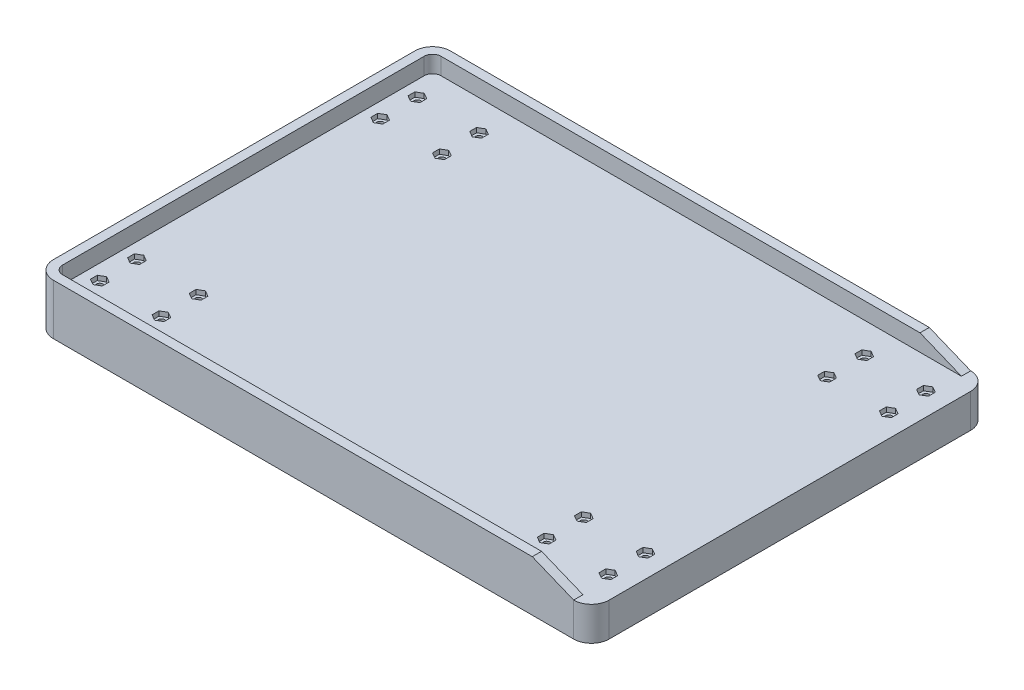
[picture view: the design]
ISO-10303-21;
HEADER;
FILE_DESCRIPTION(('STEP AP214'),'2;1');
FILE_NAME('part.step','',(''),(''),'','','');
FILE_SCHEMA(('AUTOMOTIVE_DESIGN { 1 0 10303 214 1 1 1 1 }'));
ENDSEC;
DATA;
#1=APPLICATION_CONTEXT('core data for automotive mechanical design processes');
#2=APPLICATION_PROTOCOL_DEFINITION('international standard','automotive_design',2000,#1);
#3=PRODUCT_CONTEXT('',#1,'mechanical');
#4=PRODUCT('Part','Part','',(#3));
#5=PRODUCT_RELATED_PRODUCT_CATEGORY('part','',(#4));
#6=PRODUCT_DEFINITION_FORMATION('','',#4);
#7=PRODUCT_DEFINITION_CONTEXT('part definition',#1,'design');
#8=PRODUCT_DEFINITION('design','',#6,#7);
#9=PRODUCT_DEFINITION_SHAPE('','',#8);
#10=(LENGTH_UNIT() NAMED_UNIT(*) SI_UNIT(.MILLI.,.METRE.));
#11=(NAMED_UNIT(*) PLANE_ANGLE_UNIT() SI_UNIT($,.RADIAN.));
#12=(NAMED_UNIT(*) SI_UNIT($,.STERADIAN.) SOLID_ANGLE_UNIT());
#13=UNCERTAINTY_MEASURE_WITH_UNIT(LENGTH_MEASURE(1.E-05),#10,'distance_accuracy_value','');
#14=(GEOMETRIC_REPRESENTATION_CONTEXT(3) GLOBAL_UNCERTAINTY_ASSIGNED_CONTEXT((#13)) GLOBAL_UNIT_ASSIGNED_CONTEXT((#10,
#11,#12)) REPRESENTATION_CONTEXT('',''));
#15=CARTESIAN_POINT('',(0.,0.,0.));
#16=DIRECTION('',(0.,0.,1.));
#17=DIRECTION('',(1.,0.,0.));
#18=AXIS2_PLACEMENT_3D('',#15,#16,#17);
#19=CARTESIAN_POINT('',(329.,60.,-214.));
#20=DIRECTION('',(-1.,0.,0.));
#21=DIRECTION('',(0.,0.,1.));
#22=AXIS2_PLACEMENT_3D('',#19,#20,#21);
#23=PLANE('',#22);
#24=DIRECTION('',(0.,0.,-1.));
#25=VECTOR('',#24,1.);
#26=CARTESIAN_POINT('',(329.,40.,-214.));
#27=LINE('',#26,#25);
#28=CARTESIAN_POINT('',(329.,40.,214.));
#29=VERTEX_POINT('',#28);
#30=CARTESIAN_POINT('',(329.,40.,-214.));
#31=VERTEX_POINT('',#30);
#32=EDGE_CURVE('E1550',#29,#31,#27,.T.);
#33=ORIENTED_EDGE('',*,*,#32,.F.);
#34=DIRECTION('',(0.,-1.,0.));
#35=VECTOR('',#34,1.);
#36=CARTESIAN_POINT('',(329.,60.,214.));
#37=LINE('',#36,#35);
#38=CARTESIAN_POINT('',(329.,0.,214.));
#39=VERTEX_POINT('',#38);
#40=EDGE_CURVE('E1606',#29,#39,#37,.T.);
#41=ORIENTED_EDGE('',*,*,#40,.T.);
#42=DIRECTION('',(0.,0.,-1.));
#43=VECTOR('',#42,1.);
#44=CARTESIAN_POINT('',(329.,0.,-214.));
#45=LINE('',#44,#43);
#46=CARTESIAN_POINT('',(329.,0.,-214.));
#47=VERTEX_POINT('',#46);
#48=EDGE_CURVE('E1583',#39,#47,#45,.T.);
#49=ORIENTED_EDGE('',*,*,#48,.T.);
#50=DIRECTION('',(0.,-1.,0.));
#51=VECTOR('',#50,1.);
#52=CARTESIAN_POINT('',(329.,60.,-214.));
#53=LINE('',#52,#51);
#54=EDGE_CURVE('E1604',#31,#47,#53,.T.);
#55=ORIENTED_EDGE('',*,*,#54,.F.);
#56=EDGE_LOOP('',(#33,#41,#49,#55));
#57=FACE_BOUND('',#56,.T.);
#58=ADVANCED_FACE('F44',(#57),#23,.F.);
#59=CARTESIAN_POINT('',(-308.,60.,214.));
#60=DIRECTION('',(0.,-1.,0.));
#61=DIRECTION('',(0.,0.,-1.));
#62=AXIS2_PLACEMENT_3D('',#59,#60,#61);
#63=CYLINDRICAL_SURFACE('',#62,21.0000000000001);
#64=CARTESIAN_POINT('',(-308.,0.,214.));
#65=DIRECTION('',(0.,1.,0.));
#66=DIRECTION('',(0.,0.,1.));
#67=AXIS2_PLACEMENT_3D('',#64,#65,#66);
#68=CIRCLE('',#67,21.0000000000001);
#69=CARTESIAN_POINT('',(-329.,0.,214.));
#70=VERTEX_POINT('',#69);
#71=CARTESIAN_POINT('',(-308.,0.,235.));
#72=VERTEX_POINT('',#71);
#73=EDGE_CURVE('E1560',#70,#72,#68,.T.);
#74=ORIENTED_EDGE('',*,*,#73,.T.);
#75=DIRECTION('',(0.,-1.,0.));
#76=VECTOR('',#75,1.);
#77=CARTESIAN_POINT('',(-308.,60.,235.));
#78=LINE('',#77,#76);
#79=CARTESIAN_POINT('',(-308.,60.,235.));
#80=VERTEX_POINT('',#79);
#81=EDGE_CURVE('E1610',#80,#72,#78,.T.);
#82=ORIENTED_EDGE('',*,*,#81,.F.);
#83=CARTESIAN_POINT('',(-308.,60.,214.));
#84=DIRECTION('',(0.,1.,0.));
#85=DIRECTION('',(0.,0.,1.));
#86=AXIS2_PLACEMENT_3D('',#83,#84,#85);
#87=CIRCLE('',#86,21.0000000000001);
#88=CARTESIAN_POINT('',(-329.,60.,214.));
#89=VERTEX_POINT('',#88);
#90=EDGE_CURVE('E1561',#89,#80,#87,.T.);
#91=ORIENTED_EDGE('',*,*,#90,.F.);
#92=DIRECTION('',(0.,-1.,0.));
#93=VECTOR('',#92,1.);
#94=CARTESIAN_POINT('',(-329.,60.,214.));
#95=LINE('',#94,#93);
#96=EDGE_CURVE('E1574',#89,#70,#95,.T.);
#97=ORIENTED_EDGE('',*,*,#96,.T.);
#98=EDGE_LOOP('',(#74,#82,#91,#97));
#99=FACE_BOUND('',#98,.T.);
#100=ADVANCED_FACE('F46',(#99),#63,.T.);
#101=CARTESIAN_POINT('',(-308.,60.,235.));
#102=DIRECTION('',(0.,0.,-1.));
#103=DIRECTION('',(-1.,0.,0.));
#104=AXIS2_PLACEMENT_3D('',#101,#102,#103);
#105=PLANE('',#104);
#106=DIRECTION('',(0.,-1.,0.));
#107=VECTOR('',#106,1.);
#108=CARTESIAN_POINT('',(308.,60.,235.));
#109=LINE('',#108,#107);
#110=CARTESIAN_POINT('',(308.,40.,235.));
#111=VERTEX_POINT('',#110);
#112=CARTESIAN_POINT('',(308.,0.,235.));
#113=VERTEX_POINT('',#112);
#114=EDGE_CURVE('E1608',#111,#113,#109,.T.);
#115=ORIENTED_EDGE('',*,*,#114,.F.);
#116=DIRECTION('',(-0.925847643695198,0.377896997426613,0.));
#117=VECTOR('',#116,1.);
#118=CARTESIAN_POINT('',(-227.028918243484,258.379150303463,235.));
#119=LINE('',#118,#117);
#120=CARTESIAN_POINT('',(259.,60.,235.));
#121=VERTEX_POINT('',#120);
#122=EDGE_CURVE('E1518',#111,#121,#119,.T.);
#123=ORIENTED_EDGE('',*,*,#122,.T.);
#124=DIRECTION('',(1.,0.,0.));
#125=VECTOR('',#124,1.);
#126=CARTESIAN_POINT('',(-308.,60.,235.));
#127=LINE('',#126,#125);
#128=EDGE_CURVE('E1564',#80,#121,#127,.T.);
#129=ORIENTED_EDGE('',*,*,#128,.F.);
#130=ORIENTED_EDGE('',*,*,#81,.T.);
#131=DIRECTION('',(1.,0.,0.));
#132=VECTOR('',#131,1.);
#133=CARTESIAN_POINT('',(-308.,0.,235.));
#134=LINE('',#133,#132);
#135=EDGE_CURVE('E1577',#72,#113,#134,.T.);
#136=ORIENTED_EDGE('',*,*,#135,.T.);
#137=EDGE_LOOP('',(#115,#123,#129,#130,#136));
#138=FACE_BOUND('',#137,.T.);
#139=ADVANCED_FACE('F1732',(#138),#105,.F.);
#140=CARTESIAN_POINT('',(308.,60.,214.));
#141=DIRECTION('',(0.,-1.,0.));
#142=DIRECTION('',(0.,0.,-1.));
#143=AXIS2_PLACEMENT_3D('',#140,#141,#142);
#144=CYLINDRICAL_SURFACE('',#143,21.);
#145=CARTESIAN_POINT('',(308.,40.,214.));
#146=DIRECTION('',(0.,1.,0.));
#147=DIRECTION('',(0.,0.,1.));
#148=AXIS2_PLACEMENT_3D('',#145,#146,#147);
#149=CIRCLE('',#148,21.);
#150=EDGE_CURVE('E1558',#111,#29,#149,.T.);
#151=ORIENTED_EDGE('',*,*,#150,.F.);
#152=ORIENTED_EDGE('',*,*,#114,.T.);
#153=CARTESIAN_POINT('',(308.,0.,214.));
#154=DIRECTION('',(0.,1.,0.));
#155=DIRECTION('',(0.,0.,1.));
#156=AXIS2_PLACEMENT_3D('',#153,#154,#155);
#157=CIRCLE('',#156,21.);
#158=EDGE_CURVE('E1580',#113,#39,#157,.T.);
#159=ORIENTED_EDGE('',*,*,#158,.T.);
#160=ORIENTED_EDGE('',*,*,#40,.F.);
#161=EDGE_LOOP('',(#151,#152,#159,#160));
#162=FACE_BOUND('',#161,.T.);
#163=ADVANCED_FACE('F1739',(#162),#144,.T.);
#164=CARTESIAN_POINT('',(308.,60.,-214.));
#165=DIRECTION('',(0.,-1.,0.));
#166=DIRECTION('',(0.,0.,-1.));
#167=AXIS2_PLACEMENT_3D('',#164,#165,#166);
#168=CYLINDRICAL_SURFACE('',#167,21.);
#169=DIRECTION('',(0.,-1.,0.));
#170=VECTOR('',#169,1.);
#171=CARTESIAN_POINT('',(308.,60.,-235.));
#172=LINE('',#171,#170);
#173=CARTESIAN_POINT('',(308.,40.,-235.));
#174=VERTEX_POINT('',#173);
#175=CARTESIAN_POINT('',(308.,0.,-235.));
#176=VERTEX_POINT('',#175);
#177=EDGE_CURVE('E1602',#174,#176,#172,.T.);
#178=ORIENTED_EDGE('',*,*,#177,.F.);
#179=CARTESIAN_POINT('',(308.,40.,-214.));
#180=DIRECTION('',(0.,1.,0.));
#181=DIRECTION('',(0.,0.,1.));
#182=AXIS2_PLACEMENT_3D('',#179,#180,#181);
#183=CIRCLE('',#182,21.);
#184=EDGE_CURVE('E53',#31,#174,#183,.T.);
#185=ORIENTED_EDGE('',*,*,#184,.F.);
#186=ORIENTED_EDGE('',*,*,#54,.T.);
#187=CARTESIAN_POINT('',(308.,0.,-214.));
#188=DIRECTION('',(0.,1.,0.));
#189=DIRECTION('',(0.,0.,-1.));
#190=AXIS2_PLACEMENT_3D('',#187,#188,#189);
#191=CIRCLE('',#190,21.);
#192=EDGE_CURVE('E1586',#47,#176,#191,.T.);
#193=ORIENTED_EDGE('',*,*,#192,.T.);
#194=EDGE_LOOP('',(#178,#185,#186,#193));
#195=FACE_BOUND('',#194,.T.);
#196=ADVANCED_FACE('F1737',(#195),#168,.T.);
#197=CARTESIAN_POINT('',(-308.,60.,-235.));
#198=DIRECTION('',(0.,0.,1.));
#199=DIRECTION('',(1.,0.,0.));
#200=AXIS2_PLACEMENT_3D('',#197,#198,#199);
#201=PLANE('',#200);
#202=DIRECTION('',(-1.,0.,0.));
#203=VECTOR('',#202,1.);
#204=CARTESIAN_POINT('',(-308.,60.,-235.));
#205=LINE('',#204,#203);
#206=CARTESIAN_POINT('',(259.,60.,-235.));
#207=VERTEX_POINT('',#206);
#208=CARTESIAN_POINT('',(-308.,60.,-235.));
#209=VERTEX_POINT('',#208);
#210=EDGE_CURVE('E1568',#207,#209,#205,.T.);
#211=ORIENTED_EDGE('',*,*,#210,.F.);
#212=DIRECTION('',(0.925847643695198,-0.377896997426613,0.));
#213=VECTOR('',#212,1.);
#214=CARTESIAN_POINT('',(-227.028918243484,258.379150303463,-235.));
#215=LINE('',#214,#213);
#216=EDGE_CURVE('E1515',#207,#174,#215,.T.);
#217=ORIENTED_EDGE('',*,*,#216,.T.);
#218=ORIENTED_EDGE('',*,*,#177,.T.);
#219=DIRECTION('',(-1.,0.,0.));
#220=VECTOR('',#219,1.);
#221=CARTESIAN_POINT('',(-308.,0.,-235.));
#222=LINE('',#221,#220);
#223=CARTESIAN_POINT('',(-308.,0.,-235.));
#224=VERTEX_POINT('',#223);
#225=EDGE_CURVE('E1589',#176,#224,#222,.T.);
#226=ORIENTED_EDGE('',*,*,#225,.T.);
#227=DIRECTION('',(0.,-1.,0.));
#228=VECTOR('',#227,1.);
#229=CARTESIAN_POINT('',(-308.,60.,-235.));
#230=LINE('',#229,#228);
#231=EDGE_CURVE('E1599',#209,#224,#230,.T.);
#232=ORIENTED_EDGE('',*,*,#231,.F.);
#233=EDGE_LOOP('',(#211,#217,#218,#226,#232));
#234=FACE_BOUND('',#233,.T.);
#235=ADVANCED_FACE('F1782',(#234),#201,.F.);
#236=CARTESIAN_POINT('',(-308.,60.,-214.));
#237=DIRECTION('',(0.,-1.,0.));
#238=DIRECTION('',(0.,0.,-1.));
#239=AXIS2_PLACEMENT_3D('',#236,#237,#238);
#240=CYLINDRICAL_SURFACE('',#239,21.0000000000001);
#241=CARTESIAN_POINT('',(-308.,0.,-214.));
#242=DIRECTION('',(0.,1.,0.));
#243=DIRECTION('',(0.,0.,1.));
#244=AXIS2_PLACEMENT_3D('',#241,#242,#243);
#245=CIRCLE('',#244,21.0000000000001);
#246=CARTESIAN_POINT('',(-329.,0.,-214.));
#247=VERTEX_POINT('',#246);
#248=EDGE_CURVE('E1591',#224,#247,#245,.T.);
#249=ORIENTED_EDGE('',*,*,#248,.T.);
#250=DIRECTION('',(0.,-1.,0.));
#251=VECTOR('',#250,1.);
#252=CARTESIAN_POINT('',(-329.,60.,-214.));
#253=LINE('',#252,#251);
#254=CARTESIAN_POINT('',(-329.,60.,-214.));
#255=VERTEX_POINT('',#254);
#256=EDGE_CURVE('E1596',#255,#247,#253,.T.);
#257=ORIENTED_EDGE('',*,*,#256,.F.);
#258=CARTESIAN_POINT('',(-308.,60.,-214.));
#259=DIRECTION('',(0.,1.,0.));
#260=DIRECTION('',(0.,0.,1.));
#261=AXIS2_PLACEMENT_3D('',#258,#259,#260);
#262=CIRCLE('',#261,21.0000000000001);
#263=EDGE_CURVE('E1570',#209,#255,#262,.T.);
#264=ORIENTED_EDGE('',*,*,#263,.F.);
#265=ORIENTED_EDGE('',*,*,#231,.T.);
#266=EDGE_LOOP('',(#249,#257,#264,#265));
#267=FACE_BOUND('',#266,.T.);
#268=ADVANCED_FACE('F1822',(#267),#240,.T.);
#269=CARTESIAN_POINT('',(-329.,60.,-214.));
#270=DIRECTION('',(1.,0.,0.));
#271=DIRECTION('',(0.,0.,-1.));
#272=AXIS2_PLACEMENT_3D('',#269,#270,#271);
#273=PLANE('',#272);
#274=DIRECTION('',(0.,0.,1.));
#275=VECTOR('',#274,1.);
#276=CARTESIAN_POINT('',(-329.,0.,-214.));
#277=LINE('',#276,#275);
#278=EDGE_CURVE('E1565',#247,#70,#277,.T.);
#279=ORIENTED_EDGE('',*,*,#278,.T.);
#280=ORIENTED_EDGE('',*,*,#96,.F.);
#281=DIRECTION('',(0.,0.,1.));
#282=VECTOR('',#281,1.);
#283=CARTESIAN_POINT('',(-329.,60.,-214.));
#284=LINE('',#283,#282);
#285=EDGE_CURVE('E1572',#255,#89,#284,.T.);
#286=ORIENTED_EDGE('',*,*,#285,.F.);
#287=ORIENTED_EDGE('',*,*,#256,.T.);
#288=EDGE_LOOP('',(#279,#280,#286,#287));
#289=FACE_BOUND('',#288,.T.);
#290=ADVANCED_FACE('F1816',(#289),#273,.F.);
#291=CARTESIAN_POINT('',(-308.,60.,214.));
#292=DIRECTION('',(0.,1.,0.));
#293=DIRECTION('',(0.,0.,1.));
#294=AXIS2_PLACEMENT_3D('',#291,#292,#293);
#295=PLANE('',#294);
#296=DIRECTION('',(0.,0.,1.));
#297=VECTOR('',#296,1.);
#298=CARTESIAN_POINT('',(259.,60.,-300.));
#299=LINE('',#298,#297);
#300=CARTESIAN_POINT('',(259.,60.0000000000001,-224.));
#301=VERTEX_POINT('',#300);
#302=EDGE_CURVE('E1510',#207,#301,#299,.T.);
#303=ORIENTED_EDGE('',*,*,#302,.F.);
#304=ORIENTED_EDGE('',*,*,#210,.T.);
#305=ORIENTED_EDGE('',*,*,#263,.T.);
#306=ORIENTED_EDGE('',*,*,#285,.T.);
#307=ORIENTED_EDGE('',*,*,#90,.T.);
#308=ORIENTED_EDGE('',*,*,#128,.T.);
#309=CARTESIAN_POINT('',(259.,60.,224.));
#310=VERTEX_POINT('',#309);
#311=EDGE_CURVE('E1495',#310,#121,#299,.T.);
#312=ORIENTED_EDGE('',*,*,#311,.F.);
#313=DIRECTION('',(1.,0.,0.));
#314=VECTOR('',#313,1.);
#315=CARTESIAN_POINT('',(352.266350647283,60.,224.));
#316=LINE('',#315,#314);
#317=CARTESIAN_POINT('',(-308.,60.,224.));
#318=VERTEX_POINT('',#317);
#319=EDGE_CURVE('E1525',#318,#310,#316,.T.);
#320=ORIENTED_EDGE('',*,*,#319,.F.);
#321=CARTESIAN_POINT('',(-308.,60.,214.));
#322=DIRECTION('',(0.,1.,0.));
#323=DIRECTION('',(0.,0.,1.));
#324=AXIS2_PLACEMENT_3D('',#321,#322,#323);
#325=CIRCLE('',#324,10.0000000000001);
#326=CARTESIAN_POINT('',(-318.,60.,214.));
#327=VERTEX_POINT('',#326);
#328=EDGE_CURVE('E1543',#327,#318,#325,.T.);
#329=ORIENTED_EDGE('',*,*,#328,.F.);
#330=DIRECTION('',(0.,0.,1.));
#331=VECTOR('',#330,1.);
#332=CARTESIAN_POINT('',(-318.,60.,-214.));
#333=LINE('',#332,#331);
#334=CARTESIAN_POINT('',(-318.,60.,-214.));
#335=VERTEX_POINT('',#334);
#336=EDGE_CURVE('E1540',#335,#327,#333,.T.);
#337=ORIENTED_EDGE('',*,*,#336,.F.);
#338=CARTESIAN_POINT('',(-308.,60.,-214.));
#339=DIRECTION('',(0.,1.,0.));
#340=DIRECTION('',(0.,0.,1.));
#341=AXIS2_PLACEMENT_3D('',#338,#339,#340);
#342=CIRCLE('',#341,10.0000000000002);
#343=CARTESIAN_POINT('',(-308.,60.,-224.));
#344=VERTEX_POINT('',#343);
#345=EDGE_CURVE('E1521',#344,#335,#342,.T.);
#346=ORIENTED_EDGE('',*,*,#345,.F.);
#347=DIRECTION('',(-1.,0.,0.));
#348=VECTOR('',#347,1.);
#349=CARTESIAN_POINT('',(-308.,60.,-224.));
#350=LINE('',#349,#348);
#351=EDGE_CURVE('E1613',#301,#344,#350,.T.);
#352=ORIENTED_EDGE('',*,*,#351,.F.);
#353=EDGE_LOOP('',(#303,#304,#305,#306,#307,#308,#312,#320,#329,#337,#346,#352));
#354=FACE_BOUND('',#353,.T.);
#355=ADVANCED_FACE('F1763',(#354),#295,.T.);
#356=CARTESIAN_POINT('',(-308.,0.,214.));
#357=DIRECTION('',(0.,1.,0.));
#358=DIRECTION('',(0.,0.,1.));
#359=AXIS2_PLACEMENT_3D('',#356,#357,#358);
#360=PLANE('',#359);
#361=CARTESIAN_POINT('',(302.,0.,-188.));
#362=DIRECTION('',(0.,1.,0.));
#363=DIRECTION('',(0.,0.,1.));
#364=AXIS2_PLACEMENT_3D('',#361,#362,#363);
#365=CIRCLE('',#364,3.99999999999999);
#366=CARTESIAN_POINT('',(302.,0.,-184.));
#367=VERTEX_POINT('',#366);
#368=EDGE_CURVE('E1681',#367,#367,#365,.T.);
#369=ORIENTED_EDGE('',*,*,#368,.T.);
#370=EDGE_LOOP('',(#369));
#371=FACE_BOUND('',#370,.T.);
#372=CARTESIAN_POINT('',(302.,0.,-144.));
#373=DIRECTION('',(0.,1.,0.));
#374=DIRECTION('',(0.,0.,1.));
#375=AXIS2_PLACEMENT_3D('',#372,#373,#374);
#376=CIRCLE('',#375,3.99999999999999);
#377=CARTESIAN_POINT('',(302.,0.,-140.));
#378=VERTEX_POINT('',#377);
#379=EDGE_CURVE('E1671',#378,#378,#376,.T.);
#380=ORIENTED_EDGE('',*,*,#379,.T.);
#381=EDGE_LOOP('',(#380));
#382=FACE_BOUND('',#381,.T.);
#383=CARTESIAN_POINT('',(229.,0.,-144.));
#384=DIRECTION('',(0.,1.,0.));
#385=DIRECTION('',(0.,0.,1.));
#386=AXIS2_PLACEMENT_3D('',#383,#384,#385);
#387=CIRCLE('',#386,3.99999999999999);
#388=CARTESIAN_POINT('',(229.,0.,-140.));
#389=VERTEX_POINT('',#388);
#390=EDGE_CURVE('E1668',#389,#389,#387,.T.);
#391=ORIENTED_EDGE('',*,*,#390,.T.);
#392=EDGE_LOOP('',(#391));
#393=FACE_BOUND('',#392,.T.);
#394=CARTESIAN_POINT('',(229.,0.,-188.));
#395=DIRECTION('',(0.,1.,0.));
#396=DIRECTION('',(0.,0.,1.));
#397=AXIS2_PLACEMENT_3D('',#394,#395,#396);
#398=CIRCLE('',#397,3.99999999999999);
#399=CARTESIAN_POINT('',(229.,0.,-184.));
#400=VERTEX_POINT('',#399);
#401=EDGE_CURVE('E1665',#400,#400,#398,.T.);
#402=ORIENTED_EDGE('',*,*,#401,.T.);
#403=EDGE_LOOP('',(#402));
#404=FACE_BOUND('',#403,.T.);
#405=CARTESIAN_POINT('',(302.,0.,144.));
#406=DIRECTION('',(0.,1.,0.));
#407=DIRECTION('',(0.,0.,1.));
#408=AXIS2_PLACEMENT_3D('',#405,#406,#407);
#409=CIRCLE('',#408,3.99999999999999);
#410=CARTESIAN_POINT('',(302.,0.,148.));
#411=VERTEX_POINT('',#410);
#412=EDGE_CURVE('E1661',#411,#411,#409,.T.);
#413=ORIENTED_EDGE('',*,*,#412,.T.);
#414=EDGE_LOOP('',(#413));
#415=FACE_BOUND('',#414,.T.);
#416=CARTESIAN_POINT('',(302.,0.,188.));
#417=DIRECTION('',(0.,1.,0.));
#418=DIRECTION('',(0.,0.,1.));
#419=AXIS2_PLACEMENT_3D('',#416,#417,#418);
#420=CIRCLE('',#419,3.99999999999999);
#421=CARTESIAN_POINT('',(302.,0.,192.));
#422=VERTEX_POINT('',#421);
#423=EDGE_CURVE('E1657',#422,#422,#420,.T.);
#424=ORIENTED_EDGE('',*,*,#423,.T.);
#425=EDGE_LOOP('',(#424));
#426=FACE_BOUND('',#425,.T.);
#427=CARTESIAN_POINT('',(229.,0.,188.));
#428=DIRECTION('',(0.,1.,0.));
#429=DIRECTION('',(0.,0.,1.));
#430=AXIS2_PLACEMENT_3D('',#427,#428,#429);
#431=CIRCLE('',#430,3.99999999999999);
#432=CARTESIAN_POINT('',(229.,0.,192.));
#433=VERTEX_POINT('',#432);
#434=EDGE_CURVE('E1653',#433,#433,#431,.T.);
#435=ORIENTED_EDGE('',*,*,#434,.T.);
#436=EDGE_LOOP('',(#435));
#437=FACE_BOUND('',#436,.T.);
#438=CARTESIAN_POINT('',(229.,0.,144.));
#439=DIRECTION('',(0.,1.,0.));
#440=DIRECTION('',(0.,0.,1.));
#441=AXIS2_PLACEMENT_3D('',#438,#439,#440);
#442=CIRCLE('',#441,3.99999999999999);
#443=CARTESIAN_POINT('',(229.,0.,148.));
#444=VERTEX_POINT('',#443);
#445=EDGE_CURVE('E1649',#444,#444,#442,.T.);
#446=ORIENTED_EDGE('',*,*,#445,.T.);
#447=EDGE_LOOP('',(#446));
#448=FACE_BOUND('',#447,.T.);
#449=CARTESIAN_POINT('',(-227.,0.,144.));
#450=DIRECTION('',(0.,1.,0.));
#451=DIRECTION('',(0.,0.,1.));
#452=AXIS2_PLACEMENT_3D('',#449,#450,#451);
#453=CIRCLE('',#452,3.99999999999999);
#454=CARTESIAN_POINT('',(-227.,0.,148.));
#455=VERTEX_POINT('',#454);
#456=EDGE_CURVE('E1645',#455,#455,#453,.T.);
#457=ORIENTED_EDGE('',*,*,#456,.T.);
#458=EDGE_LOOP('',(#457));
#459=FACE_BOUND('',#458,.T.);
#460=CARTESIAN_POINT('',(-227.,0.,188.));
#461=DIRECTION('',(0.,1.,0.));
#462=DIRECTION('',(0.,0.,1.));
#463=AXIS2_PLACEMENT_3D('',#460,#461,#462);
#464=CIRCLE('',#463,3.99999999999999);
#465=CARTESIAN_POINT('',(-227.,0.,192.));
#466=VERTEX_POINT('',#465);
#467=EDGE_CURVE('E1641',#466,#466,#464,.T.);
#468=ORIENTED_EDGE('',*,*,#467,.T.);
#469=EDGE_LOOP('',(#468));
#470=FACE_BOUND('',#469,.T.);
#471=CARTESIAN_POINT('',(-300.,0.,188.));
#472=DIRECTION('',(0.,1.,0.));
#473=DIRECTION('',(0.,0.,1.));
#474=AXIS2_PLACEMENT_3D('',#471,#472,#473);
#475=CIRCLE('',#474,3.99999999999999);
#476=CARTESIAN_POINT('',(-300.,0.,192.));
#477=VERTEX_POINT('',#476);
#478=EDGE_CURVE('E1637',#477,#477,#475,.T.);
#479=ORIENTED_EDGE('',*,*,#478,.T.);
#480=EDGE_LOOP('',(#479));
#481=FACE_BOUND('',#480,.T.);
#482=CARTESIAN_POINT('',(-300.,0.,144.));
#483=DIRECTION('',(0.,1.,0.));
#484=DIRECTION('',(0.,0.,1.));
#485=AXIS2_PLACEMENT_3D('',#482,#483,#484);
#486=CIRCLE('',#485,3.99999999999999);
#487=CARTESIAN_POINT('',(-300.,0.,148.));
#488=VERTEX_POINT('',#487);
#489=EDGE_CURVE('E1633',#488,#488,#486,.T.);
#490=ORIENTED_EDGE('',*,*,#489,.T.);
#491=EDGE_LOOP('',(#490));
#492=FACE_BOUND('',#491,.T.);
#493=CARTESIAN_POINT('',(-227.,0.,-188.));
#494=DIRECTION('',(0.,1.,0.));
#495=DIRECTION('',(0.,0.,1.));
#496=AXIS2_PLACEMENT_3D('',#493,#494,#495);
#497=CIRCLE('',#496,3.99999999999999);
#498=CARTESIAN_POINT('',(-227.,0.,-184.));
#499=VERTEX_POINT('',#498);
#500=EDGE_CURVE('E1629',#499,#499,#497,.T.);
#501=ORIENTED_EDGE('',*,*,#500,.T.);
#502=EDGE_LOOP('',(#501));
#503=FACE_BOUND('',#502,.T.);
#504=CARTESIAN_POINT('',(-227.,0.,-144.));
#505=DIRECTION('',(0.,1.,0.));
#506=DIRECTION('',(0.,0.,1.));
#507=AXIS2_PLACEMENT_3D('',#504,#505,#506);
#508=CIRCLE('',#507,3.99999999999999);
#509=CARTESIAN_POINT('',(-227.,0.,-140.));
#510=VERTEX_POINT('',#509);
#511=EDGE_CURVE('E1625',#510,#510,#508,.T.);
#512=ORIENTED_EDGE('',*,*,#511,.T.);
#513=EDGE_LOOP('',(#512));
#514=FACE_BOUND('',#513,.T.);
#515=CARTESIAN_POINT('',(-300.,0.,-144.));
#516=DIRECTION('',(0.,1.,0.));
#517=DIRECTION('',(0.,0.,1.));
#518=AXIS2_PLACEMENT_3D('',#515,#516,#517);
#519=CIRCLE('',#518,3.99999999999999);
#520=CARTESIAN_POINT('',(-300.,0.,-140.));
#521=VERTEX_POINT('',#520);
#522=EDGE_CURVE('E1621',#521,#521,#519,.T.);
#523=ORIENTED_EDGE('',*,*,#522,.T.);
#524=EDGE_LOOP('',(#523));
#525=FACE_BOUND('',#524,.T.);
#526=CARTESIAN_POINT('',(-300.,0.,-188.));
#527=DIRECTION('',(0.,1.,0.));
#528=DIRECTION('',(0.,0.,1.));
#529=AXIS2_PLACEMENT_3D('',#526,#527,#528);
#530=CIRCLE('',#529,3.99999999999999);
#531=CARTESIAN_POINT('',(-300.,0.,-184.));
#532=VERTEX_POINT('',#531);
#533=EDGE_CURVE('E756',#532,#532,#530,.T.);
#534=ORIENTED_EDGE('',*,*,#533,.T.);
#535=EDGE_LOOP('',(#534));
#536=FACE_BOUND('',#535,.T.);
#537=ORIENTED_EDGE('',*,*,#73,.F.);
#538=ORIENTED_EDGE('',*,*,#278,.F.);
#539=ORIENTED_EDGE('',*,*,#248,.F.);
#540=ORIENTED_EDGE('',*,*,#225,.F.);
#541=ORIENTED_EDGE('',*,*,#192,.F.);
#542=ORIENTED_EDGE('',*,*,#48,.F.);
#543=ORIENTED_EDGE('',*,*,#158,.F.);
#544=ORIENTED_EDGE('',*,*,#135,.F.);
#545=EDGE_LOOP('',(#537,#538,#539,#540,#541,#542,#543,#544));
#546=FACE_BOUND('',#545,.T.);
#547=ADVANCED_FACE('F1708',(#371,#382,#393,#404,#415,#426,#437,#448,#459,#470,#481,#492,#503,
#514,#525,#536,#546),#360,.F.);
#548=CARTESIAN_POINT('',(-308.,40.,214.));
#549=DIRECTION('',(0.,1.,0.));
#550=DIRECTION('',(0.,0.,1.));
#551=AXIS2_PLACEMENT_3D('',#548,#549,#550);
#552=PLANE('',#551);
#553=DIRECTION('',(0.,0.,-1.));
#554=VECTOR('',#553,1.);
#555=CARTESIAN_POINT('',(309.,40.,192.041451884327));
#556=LINE('',#555,#554);
#557=CARTESIAN_POINT('',(309.,40.,192.041451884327));
#558=VERTEX_POINT('',#557);
#559=CARTESIAN_POINT('',(309.,40.,183.958548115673));
#560=VERTEX_POINT('',#559);
#561=EDGE_CURVE('E61',#558,#560,#556,.T.);
#562=ORIENTED_EDGE('',*,*,#561,.F.);
#563=DIRECTION('',(0.866025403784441,0.,-0.499999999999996));
#564=VECTOR('',#563,1.);
#565=CARTESIAN_POINT('',(302.,40.,196.082903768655));
#566=LINE('',#565,#564);
#567=CARTESIAN_POINT('',(302.,40.,196.082903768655));
#568=VERTEX_POINT('',#567);
#569=EDGE_CURVE('E750',#568,#558,#566,.T.);
#570=ORIENTED_EDGE('',*,*,#569,.F.);
#571=DIRECTION('',(0.866025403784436,0.,0.500000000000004));
#572=VECTOR('',#571,1.);
#573=CARTESIAN_POINT('',(295.,40.,192.041451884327));
#574=LINE('',#573,#572);
#575=CARTESIAN_POINT('',(295.,40.,192.041451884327));
#576=VERTEX_POINT('',#575);
#577=EDGE_CURVE('E753',#576,#568,#574,.T.);
#578=ORIENTED_EDGE('',*,*,#577,.F.);
#579=DIRECTION('',(0.,0.,1.));
#580=VECTOR('',#579,1.);
#581=CARTESIAN_POINT('',(295.,40.,183.958548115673));
#582=LINE('',#581,#580);
#583=CARTESIAN_POINT('',(295.,40.,183.958548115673));
#584=VERTEX_POINT('',#583);
#585=EDGE_CURVE('E773',#584,#576,#582,.T.);
#586=ORIENTED_EDGE('',*,*,#585,.F.);
#587=DIRECTION('',(-0.866025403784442,0.,0.499999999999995));
#588=VECTOR('',#587,1.);
#589=CARTESIAN_POINT('',(302.,40.,179.917096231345));
#590=LINE('',#589,#588);
#591=CARTESIAN_POINT('',(302.,40.,179.917096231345));
#592=VERTEX_POINT('',#591);
#593=EDGE_CURVE('E770',#592,#584,#590,.T.);
#594=ORIENTED_EDGE('',*,*,#593,.F.);
#595=DIRECTION('',(-0.866025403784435,0.,-0.500000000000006));
#596=VECTOR('',#595,1.);
#597=CARTESIAN_POINT('',(309.,40.,183.958548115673));
#598=LINE('',#597,#596);
#599=EDGE_CURVE('E767',#560,#592,#598,.T.);
#600=ORIENTED_EDGE('',*,*,#599,.F.);
#601=EDGE_LOOP('',(#562,#570,#578,#586,#594,#600));
#602=FACE_BOUND('',#601,.T.);
#603=DIRECTION('',(0.,0.,-1.));
#604=VECTOR('',#603,1.);
#605=CARTESIAN_POINT('',(309.,40.,148.041451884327));
#606=LINE('',#605,#604);
#607=CARTESIAN_POINT('',(309.,40.,148.041451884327));
#608=VERTEX_POINT('',#607);
#609=CARTESIAN_POINT('',(309.,40.,139.958548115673));
#610=VERTEX_POINT('',#609);
#611=EDGE_CURVE('E69',#608,#610,#606,.T.);
#612=ORIENTED_EDGE('',*,*,#611,.F.);
#613=DIRECTION('',(0.866025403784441,0.,-0.499999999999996));
#614=VECTOR('',#613,1.);
#615=CARTESIAN_POINT('',(302.,40.,152.082903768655));
#616=LINE('',#615,#614);
#617=CARTESIAN_POINT('',(302.,40.,152.082903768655));
#618=VERTEX_POINT('',#617);
#619=EDGE_CURVE('E791',#618,#608,#616,.T.);
#620=ORIENTED_EDGE('',*,*,#619,.F.);
#621=DIRECTION('',(0.866025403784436,0.,0.500000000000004));
#622=VECTOR('',#621,1.);
#623=CARTESIAN_POINT('',(295.,40.,148.041451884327));
#624=LINE('',#623,#622);
#625=CARTESIAN_POINT('',(295.,40.,148.041451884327));
#626=VERTEX_POINT('',#625);
#627=EDGE_CURVE('E817',#626,#618,#624,.T.);
#628=ORIENTED_EDGE('',*,*,#627,.F.);
#629=DIRECTION('',(0.,0.,1.));
#630=VECTOR('',#629,1.);
#631=CARTESIAN_POINT('',(295.,40.,139.958548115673));
#632=LINE('',#631,#630);
#633=CARTESIAN_POINT('',(295.,40.,139.958548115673));
#634=VERTEX_POINT('',#633);
#635=EDGE_CURVE('E814',#634,#626,#632,.T.);
#636=ORIENTED_EDGE('',*,*,#635,.F.);
#637=DIRECTION('',(-0.866025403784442,0.,0.499999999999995));
#638=VECTOR('',#637,1.);
#639=CARTESIAN_POINT('',(302.,40.,135.917096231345));
#640=LINE('',#639,#638);
#641=CARTESIAN_POINT('',(302.,40.,135.917096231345));
#642=VERTEX_POINT('',#641);
#643=EDGE_CURVE('E811',#642,#634,#640,.T.);
#644=ORIENTED_EDGE('',*,*,#643,.F.);
#645=DIRECTION('',(-0.866025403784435,0.,-0.500000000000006));
#646=VECTOR('',#645,1.);
#647=CARTESIAN_POINT('',(309.,40.,139.958548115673));
#648=LINE('',#647,#646);
#649=EDGE_CURVE('E808',#610,#642,#648,.T.);
#650=ORIENTED_EDGE('',*,*,#649,.F.);
#651=EDGE_LOOP('',(#612,#620,#628,#636,#644,#650));
#652=FACE_BOUND('',#651,.T.);
#653=DIRECTION('',(0.,0.,-1.));
#654=VECTOR('',#653,1.);
#655=CARTESIAN_POINT('',(236.,40.,192.041451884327));
#656=LINE('',#655,#654);
#657=CARTESIAN_POINT('',(236.,40.,192.041451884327));
#658=VERTEX_POINT('',#657);
#659=CARTESIAN_POINT('',(236.,40.,183.958548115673));
#660=VERTEX_POINT('',#659);
#661=EDGE_CURVE('E824',#658,#660,#656,.T.);
#662=ORIENTED_EDGE('',*,*,#661,.F.);
#663=DIRECTION('',(0.866025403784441,0.,-0.499999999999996));
#664=VECTOR('',#663,1.);
#665=CARTESIAN_POINT('',(229.,40.,196.082903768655));
#666=LINE('',#665,#664);
#667=CARTESIAN_POINT('',(229.,40.,196.082903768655));
#668=VERTEX_POINT('',#667);
#669=EDGE_CURVE('E838',#668,#658,#666,.T.);
#670=ORIENTED_EDGE('',*,*,#669,.F.);
#671=DIRECTION('',(0.866025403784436,0.,0.500000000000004));
#672=VECTOR('',#671,1.);
#673=CARTESIAN_POINT('',(222.,40.,192.041451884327));
#674=LINE('',#673,#672);
#675=CARTESIAN_POINT('',(222.,40.,192.041451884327));
#676=VERTEX_POINT('',#675);
#677=EDGE_CURVE('E864',#676,#668,#674,.T.);
#678=ORIENTED_EDGE('',*,*,#677,.F.);
#679=DIRECTION('',(0.,0.,1.));
#680=VECTOR('',#679,1.);
#681=CARTESIAN_POINT('',(222.,40.,183.958548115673));
#682=LINE('',#681,#680);
#683=CARTESIAN_POINT('',(222.,40.,183.958548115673));
#684=VERTEX_POINT('',#683);
#685=EDGE_CURVE('E861',#684,#676,#682,.T.);
#686=ORIENTED_EDGE('',*,*,#685,.F.);
#687=DIRECTION('',(-0.866025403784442,0.,0.499999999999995));
#688=VECTOR('',#687,1.);
#689=CARTESIAN_POINT('',(229.,40.,179.917096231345));
#690=LINE('',#689,#688);
#691=CARTESIAN_POINT('',(229.,40.,179.917096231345));
#692=VERTEX_POINT('',#691);
#693=EDGE_CURVE('E858',#692,#684,#690,.T.);
#694=ORIENTED_EDGE('',*,*,#693,.F.);
#695=DIRECTION('',(-0.866025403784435,0.,-0.500000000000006));
#696=VECTOR('',#695,1.);
#697=CARTESIAN_POINT('',(236.,40.,183.958548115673));
#698=LINE('',#697,#696);
#699=EDGE_CURVE('E855',#660,#692,#698,.T.);
#700=ORIENTED_EDGE('',*,*,#699,.F.);
#701=EDGE_LOOP('',(#662,#670,#678,#686,#694,#700));
#702=FACE_BOUND('',#701,.T.);
#703=DIRECTION('',(0.,0.,-1.));
#704=VECTOR('',#703,1.);
#705=CARTESIAN_POINT('',(236.,40.,148.041451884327));
#706=LINE('',#705,#704);
#707=CARTESIAN_POINT('',(236.,40.,148.041451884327));
#708=VERTEX_POINT('',#707);
#709=CARTESIAN_POINT('',(236.,40.,139.958548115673));
#710=VERTEX_POINT('',#709);
#711=EDGE_CURVE('E871',#708,#710,#706,.T.);
#712=ORIENTED_EDGE('',*,*,#711,.F.);
#713=DIRECTION('',(0.866025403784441,0.,-0.499999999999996));
#714=VECTOR('',#713,1.);
#715=CARTESIAN_POINT('',(229.,40.,152.082903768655));
#716=LINE('',#715,#714);
#717=CARTESIAN_POINT('',(229.,40.,152.082903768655));
#718=VERTEX_POINT('',#717);
#719=EDGE_CURVE('E886',#718,#708,#716,.T.);
#720=ORIENTED_EDGE('',*,*,#719,.F.);
#721=DIRECTION('',(0.866025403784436,0.,0.500000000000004));
#722=VECTOR('',#721,1.);
#723=CARTESIAN_POINT('',(222.,40.,148.041451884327));
#724=LINE('',#723,#722);
#725=CARTESIAN_POINT('',(222.,40.,148.041451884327));
#726=VERTEX_POINT('',#725);
#727=EDGE_CURVE('E912',#726,#718,#724,.T.);
#728=ORIENTED_EDGE('',*,*,#727,.F.);
#729=DIRECTION('',(0.,0.,1.));
#730=VECTOR('',#729,1.);
#731=CARTESIAN_POINT('',(222.,40.,139.958548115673));
#732=LINE('',#731,#730);
#733=CARTESIAN_POINT('',(222.,40.,139.958548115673));
#734=VERTEX_POINT('',#733);
#735=EDGE_CURVE('E909',#734,#726,#732,.T.);
#736=ORIENTED_EDGE('',*,*,#735,.F.);
#737=DIRECTION('',(-0.866025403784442,0.,0.499999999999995));
#738=VECTOR('',#737,1.);
#739=CARTESIAN_POINT('',(229.,40.,135.917096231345));
#740=LINE('',#739,#738);
#741=CARTESIAN_POINT('',(229.,40.,135.917096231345));
#742=VERTEX_POINT('',#741);
#743=EDGE_CURVE('E906',#742,#734,#740,.T.);
#744=ORIENTED_EDGE('',*,*,#743,.F.);
#745=DIRECTION('',(-0.866025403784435,0.,-0.500000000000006));
#746=VECTOR('',#745,1.);
#747=CARTESIAN_POINT('',(236.,40.,139.958548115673));
#748=LINE('',#747,#746);
#749=EDGE_CURVE('E903',#710,#742,#748,.T.);
#750=ORIENTED_EDGE('',*,*,#749,.F.);
#751=EDGE_LOOP('',(#712,#720,#728,#736,#744,#750));
#752=FACE_BOUND('',#751,.T.);
#753=DIRECTION('',(0.,0.,-1.));
#754=VECTOR('',#753,1.);
#755=CARTESIAN_POINT('',(-220.,40.,192.041451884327));
#756=LINE('',#755,#754);
#757=CARTESIAN_POINT('',(-220.,40.,192.041451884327));
#758=VERTEX_POINT('',#757);
#759=CARTESIAN_POINT('',(-220.,40.,183.958548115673));
#760=VERTEX_POINT('',#759);
#761=EDGE_CURVE('E919',#758,#760,#756,.T.);
#762=ORIENTED_EDGE('',*,*,#761,.F.);
#763=DIRECTION('',(0.866025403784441,0.,-0.499999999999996));
#764=VECTOR('',#763,1.);
#765=CARTESIAN_POINT('',(-227.,40.,196.082903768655));
#766=LINE('',#765,#764);
#767=CARTESIAN_POINT('',(-227.,40.,196.082903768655));
#768=VERTEX_POINT('',#767);
#769=EDGE_CURVE('E934',#768,#758,#766,.T.);
#770=ORIENTED_EDGE('',*,*,#769,.F.);
#771=DIRECTION('',(0.866025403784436,0.,0.500000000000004));
#772=VECTOR('',#771,1.);
#773=CARTESIAN_POINT('',(-234.,40.,192.041451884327));
#774=LINE('',#773,#772);
#775=CARTESIAN_POINT('',(-234.,40.,192.041451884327));
#776=VERTEX_POINT('',#775);
#777=EDGE_CURVE('E960',#776,#768,#774,.T.);
#778=ORIENTED_EDGE('',*,*,#777,.F.);
#779=DIRECTION('',(0.,0.,1.));
#780=VECTOR('',#779,1.);
#781=CARTESIAN_POINT('',(-234.,40.,183.958548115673));
#782=LINE('',#781,#780);
#783=CARTESIAN_POINT('',(-234.,40.,183.958548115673));
#784=VERTEX_POINT('',#783);
#785=EDGE_CURVE('E957',#784,#776,#782,.T.);
#786=ORIENTED_EDGE('',*,*,#785,.F.);
#787=DIRECTION('',(-0.866025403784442,0.,0.499999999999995));
#788=VECTOR('',#787,1.);
#789=CARTESIAN_POINT('',(-227.,40.,179.917096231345));
#790=LINE('',#789,#788);
#791=CARTESIAN_POINT('',(-227.,40.,179.917096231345));
#792=VERTEX_POINT('',#791);
#793=EDGE_CURVE('E954',#792,#784,#790,.T.);
#794=ORIENTED_EDGE('',*,*,#793,.F.);
#795=DIRECTION('',(-0.866025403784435,0.,-0.500000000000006));
#796=VECTOR('',#795,1.);
#797=CARTESIAN_POINT('',(-220.,40.,183.958548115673));
#798=LINE('',#797,#796);
#799=EDGE_CURVE('E951',#760,#792,#798,.T.);
#800=ORIENTED_EDGE('',*,*,#799,.F.);
#801=EDGE_LOOP('',(#762,#770,#778,#786,#794,#800));
#802=FACE_BOUND('',#801,.T.);
#803=DIRECTION('',(0.,0.,-1.));
#804=VECTOR('',#803,1.);
#805=CARTESIAN_POINT('',(-293.,40.,192.041451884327));
#806=LINE('',#805,#804);
#807=CARTESIAN_POINT('',(-293.,40.,192.041451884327));
#808=VERTEX_POINT('',#807);
#809=CARTESIAN_POINT('',(-293.,40.,183.958548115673));
#810=VERTEX_POINT('',#809);
#811=EDGE_CURVE('E967',#808,#810,#806,.T.);
#812=ORIENTED_EDGE('',*,*,#811,.F.);
#813=DIRECTION('',(0.866025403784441,0.,-0.499999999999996));
#814=VECTOR('',#813,1.);
#815=CARTESIAN_POINT('',(-300.,40.,196.082903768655));
#816=LINE('',#815,#814);
#817=CARTESIAN_POINT('',(-300.,40.,196.082903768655));
#818=VERTEX_POINT('',#817);
#819=EDGE_CURVE('E982',#818,#808,#816,.T.);
#820=ORIENTED_EDGE('',*,*,#819,.F.);
#821=DIRECTION('',(0.866025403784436,0.,0.500000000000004));
#822=VECTOR('',#821,1.);
#823=CARTESIAN_POINT('',(-307.,40.,192.041451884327));
#824=LINE('',#823,#822);
#825=CARTESIAN_POINT('',(-307.,40.,192.041451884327));
#826=VERTEX_POINT('',#825);
#827=EDGE_CURVE('E1008',#826,#818,#824,.T.);
#828=ORIENTED_EDGE('',*,*,#827,.F.);
#829=DIRECTION('',(0.,0.,1.));
#830=VECTOR('',#829,1.);
#831=CARTESIAN_POINT('',(-307.,40.,183.958548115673));
#832=LINE('',#831,#830);
#833=CARTESIAN_POINT('',(-307.,40.,183.958548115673));
#834=VERTEX_POINT('',#833);
#835=EDGE_CURVE('E1005',#834,#826,#832,.T.);
#836=ORIENTED_EDGE('',*,*,#835,.F.);
#837=DIRECTION('',(-0.866025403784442,0.,0.499999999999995));
#838=VECTOR('',#837,1.);
#839=CARTESIAN_POINT('',(-300.,40.,179.917096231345));
#840=LINE('',#839,#838);
#841=CARTESIAN_POINT('',(-300.,40.,179.917096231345));
#842=VERTEX_POINT('',#841);
#843=EDGE_CURVE('E1002',#842,#834,#840,.T.);
#844=ORIENTED_EDGE('',*,*,#843,.F.);
#845=DIRECTION('',(-0.866025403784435,0.,-0.500000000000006));
#846=VECTOR('',#845,1.);
#847=CARTESIAN_POINT('',(-293.,40.,183.958548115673));
#848=LINE('',#847,#846);
#849=EDGE_CURVE('E999',#810,#842,#848,.T.);
#850=ORIENTED_EDGE('',*,*,#849,.F.);
#851=EDGE_LOOP('',(#812,#820,#828,#836,#844,#850));
#852=FACE_BOUND('',#851,.T.);
#853=DIRECTION('',(0.,0.,-1.));
#854=VECTOR('',#853,1.);
#855=CARTESIAN_POINT('',(-220.,40.,148.041451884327));
#856=LINE('',#855,#854);
#857=CARTESIAN_POINT('',(-220.,40.,148.041451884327));
#858=VERTEX_POINT('',#857);
#859=CARTESIAN_POINT('',(-220.,40.,139.958548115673));
#860=VERTEX_POINT('',#859);
#861=EDGE_CURVE('E1015',#858,#860,#856,.T.);
#862=ORIENTED_EDGE('',*,*,#861,.F.);
#863=DIRECTION('',(0.866025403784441,0.,-0.499999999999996));
#864=VECTOR('',#863,1.);
#865=CARTESIAN_POINT('',(-227.,40.,152.082903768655));
#866=LINE('',#865,#864);
#867=CARTESIAN_POINT('',(-227.,40.,152.082903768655));
#868=VERTEX_POINT('',#867);
#869=EDGE_CURVE('E1030',#868,#858,#866,.T.);
#870=ORIENTED_EDGE('',*,*,#869,.F.);
#871=DIRECTION('',(0.866025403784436,0.,0.500000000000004));
#872=VECTOR('',#871,1.);
#873=CARTESIAN_POINT('',(-234.,40.,148.041451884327));
#874=LINE('',#873,#872);
#875=CARTESIAN_POINT('',(-234.,40.,148.041451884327));
#876=VERTEX_POINT('',#875);
#877=EDGE_CURVE('E1056',#876,#868,#874,.T.);
#878=ORIENTED_EDGE('',*,*,#877,.F.);
#879=DIRECTION('',(0.,0.,1.));
#880=VECTOR('',#879,1.);
#881=CARTESIAN_POINT('',(-234.,40.,139.958548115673));
#882=LINE('',#881,#880);
#883=CARTESIAN_POINT('',(-234.,40.,139.958548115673));
#884=VERTEX_POINT('',#883);
#885=EDGE_CURVE('E1053',#884,#876,#882,.T.);
#886=ORIENTED_EDGE('',*,*,#885,.F.);
#887=DIRECTION('',(-0.866025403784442,0.,0.499999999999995));
#888=VECTOR('',#887,1.);
#889=CARTESIAN_POINT('',(-227.,40.,135.917096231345));
#890=LINE('',#889,#888);
#891=CARTESIAN_POINT('',(-227.,40.,135.917096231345));
#892=VERTEX_POINT('',#891);
#893=EDGE_CURVE('E1050',#892,#884,#890,.T.);
#894=ORIENTED_EDGE('',*,*,#893,.F.);
#895=DIRECTION('',(-0.866025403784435,0.,-0.500000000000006));
#896=VECTOR('',#895,1.);
#897=CARTESIAN_POINT('',(-220.,40.,139.958548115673));
#898=LINE('',#897,#896);
#899=EDGE_CURVE('E1047',#860,#892,#898,.T.);
#900=ORIENTED_EDGE('',*,*,#899,.F.);
#901=EDGE_LOOP('',(#862,#870,#878,#886,#894,#900));
#902=FACE_BOUND('',#901,.T.);
#903=DIRECTION('',(0.,0.,-1.));
#904=VECTOR('',#903,1.);
#905=CARTESIAN_POINT('',(-293.,40.,148.041451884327));
#906=LINE('',#905,#904);
#907=CARTESIAN_POINT('',(-293.,40.,148.041451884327));
#908=VERTEX_POINT('',#907);
#909=CARTESIAN_POINT('',(-293.,40.,139.958548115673));
#910=VERTEX_POINT('',#909);
#911=EDGE_CURVE('E1063',#908,#910,#906,.T.);
#912=ORIENTED_EDGE('',*,*,#911,.F.);
#913=DIRECTION('',(0.866025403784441,0.,-0.499999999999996));
#914=VECTOR('',#913,1.);
#915=CARTESIAN_POINT('',(-300.,40.,152.082903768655));
#916=LINE('',#915,#914);
#917=CARTESIAN_POINT('',(-300.,40.,152.082903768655));
#918=VERTEX_POINT('',#917);
#919=EDGE_CURVE('E1078',#918,#908,#916,.T.);
#920=ORIENTED_EDGE('',*,*,#919,.F.);
#921=DIRECTION('',(0.866025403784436,0.,0.500000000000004));
#922=VECTOR('',#921,1.);
#923=CARTESIAN_POINT('',(-307.,40.,148.041451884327));
#924=LINE('',#923,#922);
#925=CARTESIAN_POINT('',(-307.,40.,148.041451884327));
#926=VERTEX_POINT('',#925);
#927=EDGE_CURVE('E1104',#926,#918,#924,.T.);
#928=ORIENTED_EDGE('',*,*,#927,.F.);
#929=DIRECTION('',(0.,0.,1.));
#930=VECTOR('',#929,1.);
#931=CARTESIAN_POINT('',(-307.,40.,139.958548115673));
#932=LINE('',#931,#930);
#933=CARTESIAN_POINT('',(-307.,40.,139.958548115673));
#934=VERTEX_POINT('',#933);
#935=EDGE_CURVE('E1101',#934,#926,#932,.T.);
#936=ORIENTED_EDGE('',*,*,#935,.F.);
#937=DIRECTION('',(-0.866025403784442,0.,0.499999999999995));
#938=VECTOR('',#937,1.);
#939=CARTESIAN_POINT('',(-300.,40.,135.917096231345));
#940=LINE('',#939,#938);
#941=CARTESIAN_POINT('',(-300.,40.,135.917096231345));
#942=VERTEX_POINT('',#941);
#943=EDGE_CURVE('E1098',#942,#934,#940,.T.);
#944=ORIENTED_EDGE('',*,*,#943,.F.);
#945=DIRECTION('',(-0.866025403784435,0.,-0.500000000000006));
#946=VECTOR('',#945,1.);
#947=CARTESIAN_POINT('',(-293.,40.,139.958548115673));
#948=LINE('',#947,#946);
#949=EDGE_CURVE('E1095',#910,#942,#948,.T.);
#950=ORIENTED_EDGE('',*,*,#949,.F.);
#951=EDGE_LOOP('',(#912,#920,#928,#936,#944,#950));
#952=FACE_BOUND('',#951,.T.);
#953=DIRECTION('',(0.,0.,-1.));
#954=VECTOR('',#953,1.);
#955=CARTESIAN_POINT('',(-220.,40.,-139.958548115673));
#956=LINE('',#955,#954);
#957=CARTESIAN_POINT('',(-220.,40.,-139.958548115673));
#958=VERTEX_POINT('',#957);
#959=CARTESIAN_POINT('',(-220.,40.,-148.041451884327));
#960=VERTEX_POINT('',#959);
#961=EDGE_CURVE('E1111',#958,#960,#956,.T.);
#962=ORIENTED_EDGE('',*,*,#961,.F.);
#963=DIRECTION('',(0.866025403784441,0.,-0.499999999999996));
#964=VECTOR('',#963,1.);
#965=CARTESIAN_POINT('',(-227.,40.,-135.917096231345));
#966=LINE('',#965,#964);
#967=CARTESIAN_POINT('',(-227.,40.,-135.917096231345));
#968=VERTEX_POINT('',#967);
#969=EDGE_CURVE('E1126',#968,#958,#966,.T.);
#970=ORIENTED_EDGE('',*,*,#969,.F.);
#971=DIRECTION('',(0.866025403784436,0.,0.500000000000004));
#972=VECTOR('',#971,1.);
#973=CARTESIAN_POINT('',(-234.,40.,-139.958548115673));
#974=LINE('',#973,#972);
#975=CARTESIAN_POINT('',(-234.,40.,-139.958548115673));
#976=VERTEX_POINT('',#975);
#977=EDGE_CURVE('E1152',#976,#968,#974,.T.);
#978=ORIENTED_EDGE('',*,*,#977,.F.);
#979=DIRECTION('',(0.,0.,1.));
#980=VECTOR('',#979,1.);
#981=CARTESIAN_POINT('',(-234.,40.,-148.041451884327));
#982=LINE('',#981,#980);
#983=CARTESIAN_POINT('',(-234.,40.,-148.041451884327));
#984=VERTEX_POINT('',#983);
#985=EDGE_CURVE('E1149',#984,#976,#982,.T.);
#986=ORIENTED_EDGE('',*,*,#985,.F.);
#987=DIRECTION('',(-0.866025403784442,0.,0.499999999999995));
#988=VECTOR('',#987,1.);
#989=CARTESIAN_POINT('',(-227.,40.,-152.082903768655));
#990=LINE('',#989,#988);
#991=CARTESIAN_POINT('',(-227.,40.,-152.082903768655));
#992=VERTEX_POINT('',#991);
#993=EDGE_CURVE('E1146',#992,#984,#990,.T.);
#994=ORIENTED_EDGE('',*,*,#993,.F.);
#995=DIRECTION('',(-0.866025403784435,0.,-0.500000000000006));
#996=VECTOR('',#995,1.);
#997=CARTESIAN_POINT('',(-220.,40.,-148.041451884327));
#998=LINE('',#997,#996);
#999=EDGE_CURVE('E1143',#960,#992,#998,.T.);
#1000=ORIENTED_EDGE('',*,*,#999,.F.);
#1001=EDGE_LOOP('',(#962,#970,#978,#986,#994,#1000));
#1002=FACE_BOUND('',#1001,.T.);
#1003=DIRECTION('',(0.,0.,-1.));
#1004=VECTOR('',#1003,1.);
#1005=CARTESIAN_POINT('',(-293.,40.,-139.958548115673));
#1006=LINE('',#1005,#1004);
#1007=CARTESIAN_POINT('',(-293.,40.,-139.958548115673));
#1008=VERTEX_POINT('',#1007);
#1009=CARTESIAN_POINT('',(-293.,40.,-148.041451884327));
#1010=VERTEX_POINT('',#1009);
#1011=EDGE_CURVE('E1159',#1008,#1010,#1006,.T.);
#1012=ORIENTED_EDGE('',*,*,#1011,.F.);
#1013=DIRECTION('',(0.866025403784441,0.,-0.499999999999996));
#1014=VECTOR('',#1013,1.);
#1015=CARTESIAN_POINT('',(-300.,40.,-135.917096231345));
#1016=LINE('',#1015,#1014);
#1017=CARTESIAN_POINT('',(-300.,40.,-135.917096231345));
#1018=VERTEX_POINT('',#1017);
#1019=EDGE_CURVE('E1174',#1018,#1008,#1016,.T.);
#1020=ORIENTED_EDGE('',*,*,#1019,.F.);
#1021=DIRECTION('',(0.866025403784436,0.,0.500000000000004));
#1022=VECTOR('',#1021,1.);
#1023=CARTESIAN_POINT('',(-307.,40.,-139.958548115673));
#1024=LINE('',#1023,#1022);
#1025=CARTESIAN_POINT('',(-307.,40.,-139.958548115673));
#1026=VERTEX_POINT('',#1025);
#1027=EDGE_CURVE('E1200',#1026,#1018,#1024,.T.);
#1028=ORIENTED_EDGE('',*,*,#1027,.F.);
#1029=DIRECTION('',(0.,0.,1.));
#1030=VECTOR('',#1029,1.);
#1031=CARTESIAN_POINT('',(-307.,40.,-148.041451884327));
#1032=LINE('',#1031,#1030);
#1033=CARTESIAN_POINT('',(-307.,40.,-148.041451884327));
#1034=VERTEX_POINT('',#1033);
#1035=EDGE_CURVE('E1197',#1034,#1026,#1032,.T.);
#1036=ORIENTED_EDGE('',*,*,#1035,.F.);
#1037=DIRECTION('',(-0.866025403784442,0.,0.499999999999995));
#1038=VECTOR('',#1037,1.);
#1039=CARTESIAN_POINT('',(-300.,40.,-152.082903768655));
#1040=LINE('',#1039,#1038);
#1041=CARTESIAN_POINT('',(-300.,40.,-152.082903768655));
#1042=VERTEX_POINT('',#1041);
#1043=EDGE_CURVE('E1194',#1042,#1034,#1040,.T.);
#1044=ORIENTED_EDGE('',*,*,#1043,.F.);
#1045=DIRECTION('',(-0.866025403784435,0.,-0.500000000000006));
#1046=VECTOR('',#1045,1.);
#1047=CARTESIAN_POINT('',(-293.,40.,-148.041451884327));
#1048=LINE('',#1047,#1046);
#1049=EDGE_CURVE('E1191',#1010,#1042,#1048,.T.);
#1050=ORIENTED_EDGE('',*,*,#1049,.F.);
#1051=EDGE_LOOP('',(#1012,#1020,#1028,#1036,#1044,#1050));
#1052=FACE_BOUND('',#1051,.T.);
#1053=DIRECTION('',(0.,0.,-1.));
#1054=VECTOR('',#1053,1.);
#1055=CARTESIAN_POINT('',(-293.,40.,-183.958548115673));
#1056=LINE('',#1055,#1054);
#1057=CARTESIAN_POINT('',(-293.,40.,-183.958548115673));
#1058=VERTEX_POINT('',#1057);
#1059=CARTESIAN_POINT('',(-293.,40.,-192.041451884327));
#1060=VERTEX_POINT('',#1059);
#1061=EDGE_CURVE('E1207',#1058,#1060,#1056,.T.);
#1062=ORIENTED_EDGE('',*,*,#1061,.F.);
#1063=DIRECTION('',(0.866025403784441,0.,-0.499999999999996));
#1064=VECTOR('',#1063,1.);
#1065=CARTESIAN_POINT('',(-300.,40.,-179.917096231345));
#1066=LINE('',#1065,#1064);
#1067=CARTESIAN_POINT('',(-300.,40.,-179.917096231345));
#1068=VERTEX_POINT('',#1067);
#1069=EDGE_CURVE('E1222',#1068,#1058,#1066,.T.);
#1070=ORIENTED_EDGE('',*,*,#1069,.F.);
#1071=DIRECTION('',(0.866025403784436,0.,0.500000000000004));
#1072=VECTOR('',#1071,1.);
#1073=CARTESIAN_POINT('',(-307.,40.,-183.958548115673));
#1074=LINE('',#1073,#1072);
#1075=CARTESIAN_POINT('',(-307.,40.,-183.958548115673));
#1076=VERTEX_POINT('',#1075);
#1077=EDGE_CURVE('E1248',#1076,#1068,#1074,.T.);
#1078=ORIENTED_EDGE('',*,*,#1077,.F.);
#1079=DIRECTION('',(0.,0.,1.));
#1080=VECTOR('',#1079,1.);
#1081=CARTESIAN_POINT('',(-307.,40.,-192.041451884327));
#1082=LINE('',#1081,#1080);
#1083=CARTESIAN_POINT('',(-307.,40.,-192.041451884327));
#1084=VERTEX_POINT('',#1083);
#1085=EDGE_CURVE('E1245',#1084,#1076,#1082,.T.);
#1086=ORIENTED_EDGE('',*,*,#1085,.F.);
#1087=DIRECTION('',(-0.866025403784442,0.,0.499999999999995));
#1088=VECTOR('',#1087,1.);
#1089=CARTESIAN_POINT('',(-300.,40.,-196.082903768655));
#1090=LINE('',#1089,#1088);
#1091=CARTESIAN_POINT('',(-300.,40.,-196.082903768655));
#1092=VERTEX_POINT('',#1091);
#1093=EDGE_CURVE('E1242',#1092,#1084,#1090,.T.);
#1094=ORIENTED_EDGE('',*,*,#1093,.F.);
#1095=DIRECTION('',(-0.866025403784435,0.,-0.500000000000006));
#1096=VECTOR('',#1095,1.);
#1097=CARTESIAN_POINT('',(-293.,40.,-192.041451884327));
#1098=LINE('',#1097,#1096);
#1099=EDGE_CURVE('E1239',#1060,#1092,#1098,.T.);
#1100=ORIENTED_EDGE('',*,*,#1099,.F.);
#1101=EDGE_LOOP('',(#1062,#1070,#1078,#1086,#1094,#1100));
#1102=FACE_BOUND('',#1101,.T.);
#1103=DIRECTION('',(0.,0.,-1.));
#1104=VECTOR('',#1103,1.);
#1105=CARTESIAN_POINT('',(-220.,40.,-183.958548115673));
#1106=LINE('',#1105,#1104);
#1107=CARTESIAN_POINT('',(-220.,40.,-183.958548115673));
#1108=VERTEX_POINT('',#1107);
#1109=CARTESIAN_POINT('',(-220.,40.,-192.041451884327));
#1110=VERTEX_POINT('',#1109);
#1111=EDGE_CURVE('E1255',#1108,#1110,#1106,.T.);
#1112=ORIENTED_EDGE('',*,*,#1111,.F.);
#1113=DIRECTION('',(0.866025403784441,0.,-0.499999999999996));
#1114=VECTOR('',#1113,1.);
#1115=CARTESIAN_POINT('',(-227.,40.,-179.917096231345));
#1116=LINE('',#1115,#1114);
#1117=CARTESIAN_POINT('',(-227.,40.,-179.917096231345));
#1118=VERTEX_POINT('',#1117);
#1119=EDGE_CURVE('E1270',#1118,#1108,#1116,.T.);
#1120=ORIENTED_EDGE('',*,*,#1119,.F.);
#1121=DIRECTION('',(0.866025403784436,0.,0.500000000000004));
#1122=VECTOR('',#1121,1.);
#1123=CARTESIAN_POINT('',(-234.,40.,-183.958548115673));
#1124=LINE('',#1123,#1122);
#1125=CARTESIAN_POINT('',(-234.,40.,-183.958548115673));
#1126=VERTEX_POINT('',#1125);
#1127=EDGE_CURVE('E1296',#1126,#1118,#1124,.T.);
#1128=ORIENTED_EDGE('',*,*,#1127,.F.);
#1129=DIRECTION('',(0.,0.,1.));
#1130=VECTOR('',#1129,1.);
#1131=CARTESIAN_POINT('',(-234.,40.,-192.041451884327));
#1132=LINE('',#1131,#1130);
#1133=CARTESIAN_POINT('',(-234.,40.,-192.041451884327));
#1134=VERTEX_POINT('',#1133);
#1135=EDGE_CURVE('E1293',#1134,#1126,#1132,.T.);
#1136=ORIENTED_EDGE('',*,*,#1135,.F.);
#1137=DIRECTION('',(-0.866025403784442,0.,0.499999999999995));
#1138=VECTOR('',#1137,1.);
#1139=CARTESIAN_POINT('',(-227.,40.,-196.082903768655));
#1140=LINE('',#1139,#1138);
#1141=CARTESIAN_POINT('',(-227.,40.,-196.082903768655));
#1142=VERTEX_POINT('',#1141);
#1143=EDGE_CURVE('E1290',#1142,#1134,#1140,.T.);
#1144=ORIENTED_EDGE('',*,*,#1143,.F.);
#1145=DIRECTION('',(-0.866025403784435,0.,-0.500000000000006));
#1146=VECTOR('',#1145,1.);
#1147=CARTESIAN_POINT('',(-220.,40.,-192.041451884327));
#1148=LINE('',#1147,#1146);
#1149=EDGE_CURVE('E1287',#1110,#1142,#1148,.T.);
#1150=ORIENTED_EDGE('',*,*,#1149,.F.);
#1151=EDGE_LOOP('',(#1112,#1120,#1128,#1136,#1144,#1150));
#1152=FACE_BOUND('',#1151,.T.);
#1153=DIRECTION('',(0.,0.,-1.));
#1154=VECTOR('',#1153,1.);
#1155=CARTESIAN_POINT('',(236.,40.,-183.958548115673));
#1156=LINE('',#1155,#1154);
#1157=CARTESIAN_POINT('',(236.,40.,-183.958548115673));
#1158=VERTEX_POINT('',#1157);
#1159=CARTESIAN_POINT('',(236.,40.,-192.041451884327));
#1160=VERTEX_POINT('',#1159);
#1161=EDGE_CURVE('E1303',#1158,#1160,#1156,.T.);
#1162=ORIENTED_EDGE('',*,*,#1161,.F.);
#1163=DIRECTION('',(0.866025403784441,0.,-0.499999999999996));
#1164=VECTOR('',#1163,1.);
#1165=CARTESIAN_POINT('',(229.,40.,-179.917096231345));
#1166=LINE('',#1165,#1164);
#1167=CARTESIAN_POINT('',(229.,40.,-179.917096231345));
#1168=VERTEX_POINT('',#1167);
#1169=EDGE_CURVE('E1318',#1168,#1158,#1166,.T.);
#1170=ORIENTED_EDGE('',*,*,#1169,.F.);
#1171=DIRECTION('',(0.866025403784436,0.,0.500000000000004));
#1172=VECTOR('',#1171,1.);
#1173=CARTESIAN_POINT('',(222.,40.,-183.958548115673));
#1174=LINE('',#1173,#1172);
#1175=CARTESIAN_POINT('',(222.,40.,-183.958548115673));
#1176=VERTEX_POINT('',#1175);
#1177=EDGE_CURVE('E1344',#1176,#1168,#1174,.T.);
#1178=ORIENTED_EDGE('',*,*,#1177,.F.);
#1179=DIRECTION('',(0.,0.,1.));
#1180=VECTOR('',#1179,1.);
#1181=CARTESIAN_POINT('',(222.,40.,-192.041451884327));
#1182=LINE('',#1181,#1180);
#1183=CARTESIAN_POINT('',(222.,40.,-192.041451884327));
#1184=VERTEX_POINT('',#1183);
#1185=EDGE_CURVE('E1341',#1184,#1176,#1182,.T.);
#1186=ORIENTED_EDGE('',*,*,#1185,.F.);
#1187=DIRECTION('',(-0.866025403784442,0.,0.499999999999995));
#1188=VECTOR('',#1187,1.);
#1189=CARTESIAN_POINT('',(229.,40.,-196.082903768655));
#1190=LINE('',#1189,#1188);
#1191=CARTESIAN_POINT('',(229.,40.,-196.082903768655));
#1192=VERTEX_POINT('',#1191);
#1193=EDGE_CURVE('E1338',#1192,#1184,#1190,.T.);
#1194=ORIENTED_EDGE('',*,*,#1193,.F.);
#1195=DIRECTION('',(-0.866025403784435,0.,-0.500000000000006));
#1196=VECTOR('',#1195,1.);
#1197=CARTESIAN_POINT('',(236.,40.,-192.041451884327));
#1198=LINE('',#1197,#1196);
#1199=EDGE_CURVE('E1335',#1160,#1192,#1198,.T.);
#1200=ORIENTED_EDGE('',*,*,#1199,.F.);
#1201=EDGE_LOOP('',(#1162,#1170,#1178,#1186,#1194,#1200));
#1202=FACE_BOUND('',#1201,.T.);
#1203=DIRECTION('',(0.,0.,-1.));
#1204=VECTOR('',#1203,1.);
#1205=CARTESIAN_POINT('',(236.,40.,-139.958548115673));
#1206=LINE('',#1205,#1204);
#1207=CARTESIAN_POINT('',(236.,40.,-139.958548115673));
#1208=VERTEX_POINT('',#1207);
#1209=CARTESIAN_POINT('',(236.,40.,-148.041451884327));
#1210=VERTEX_POINT('',#1209);
#1211=EDGE_CURVE('E1351',#1208,#1210,#1206,.T.);
#1212=ORIENTED_EDGE('',*,*,#1211,.F.);
#1213=DIRECTION('',(0.866025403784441,0.,-0.499999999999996));
#1214=VECTOR('',#1213,1.);
#1215=CARTESIAN_POINT('',(229.,40.,-135.917096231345));
#1216=LINE('',#1215,#1214);
#1217=CARTESIAN_POINT('',(229.,40.,-135.917096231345));
#1218=VERTEX_POINT('',#1217);
#1219=EDGE_CURVE('E1366',#1218,#1208,#1216,.T.);
#1220=ORIENTED_EDGE('',*,*,#1219,.F.);
#1221=DIRECTION('',(0.866025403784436,0.,0.500000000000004));
#1222=VECTOR('',#1221,1.);
#1223=CARTESIAN_POINT('',(222.,40.,-139.958548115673));
#1224=LINE('',#1223,#1222);
#1225=CARTESIAN_POINT('',(222.,40.,-139.958548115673));
#1226=VERTEX_POINT('',#1225);
#1227=EDGE_CURVE('E1392',#1226,#1218,#1224,.T.);
#1228=ORIENTED_EDGE('',*,*,#1227,.F.);
#1229=DIRECTION('',(0.,0.,1.));
#1230=VECTOR('',#1229,1.);
#1231=CARTESIAN_POINT('',(222.,40.,-148.041451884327));
#1232=LINE('',#1231,#1230);
#1233=CARTESIAN_POINT('',(222.,40.,-148.041451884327));
#1234=VERTEX_POINT('',#1233);
#1235=EDGE_CURVE('E1389',#1234,#1226,#1232,.T.);
#1236=ORIENTED_EDGE('',*,*,#1235,.F.);
#1237=DIRECTION('',(-0.866025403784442,0.,0.499999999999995));
#1238=VECTOR('',#1237,1.);
#1239=CARTESIAN_POINT('',(229.,40.,-152.082903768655));
#1240=LINE('',#1239,#1238);
#1241=CARTESIAN_POINT('',(229.,40.,-152.082903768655));
#1242=VERTEX_POINT('',#1241);
#1243=EDGE_CURVE('E1386',#1242,#1234,#1240,.T.);
#1244=ORIENTED_EDGE('',*,*,#1243,.F.);
#1245=DIRECTION('',(-0.866025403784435,0.,-0.500000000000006));
#1246=VECTOR('',#1245,1.);
#1247=CARTESIAN_POINT('',(236.,40.,-148.041451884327));
#1248=LINE('',#1247,#1246);
#1249=EDGE_CURVE('E1383',#1210,#1242,#1248,.T.);
#1250=ORIENTED_EDGE('',*,*,#1249,.F.);
#1251=EDGE_LOOP('',(#1212,#1220,#1228,#1236,#1244,#1250));
#1252=FACE_BOUND('',#1251,.T.);
#1253=DIRECTION('',(0.866025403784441,0.,-0.499999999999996));
#1254=VECTOR('',#1253,1.);
#1255=CARTESIAN_POINT('',(302.,40.,-179.917096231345));
#1256=LINE('',#1255,#1254);
#1257=CARTESIAN_POINT('',(302.,40.,-179.917096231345));
#1258=VERTEX_POINT('',#1257);
#1259=CARTESIAN_POINT('',(309.,40.,-183.958548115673));
#1260=VERTEX_POINT('',#1259);
#1261=EDGE_CURVE('E1399',#1258,#1260,#1256,.T.);
#1262=ORIENTED_EDGE('',*,*,#1261,.F.);
#1263=DIRECTION('',(0.866025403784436,0.,0.500000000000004));
#1264=VECTOR('',#1263,1.);
#1265=CARTESIAN_POINT('',(295.,40.,-183.958548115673));
#1266=LINE('',#1265,#1264);
#1267=CARTESIAN_POINT('',(295.,40.,-183.958548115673));
#1268=VERTEX_POINT('',#1267);
#1269=EDGE_CURVE('E1414',#1268,#1258,#1266,.T.);
#1270=ORIENTED_EDGE('',*,*,#1269,.F.);
#1271=DIRECTION('',(0.,0.,1.));
#1272=VECTOR('',#1271,1.);
#1273=CARTESIAN_POINT('',(295.,40.,-192.041451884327));
#1274=LINE('',#1273,#1272);
#1275=CARTESIAN_POINT('',(295.,40.,-192.041451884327));
#1276=VERTEX_POINT('',#1275);
#1277=EDGE_CURVE('E1440',#1276,#1268,#1274,.T.);
#1278=ORIENTED_EDGE('',*,*,#1277,.F.);
#1279=DIRECTION('',(-0.866025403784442,0.,0.499999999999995));
#1280=VECTOR('',#1279,1.);
#1281=CARTESIAN_POINT('',(302.,40.,-196.082903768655));
#1282=LINE('',#1281,#1280);
#1283=CARTESIAN_POINT('',(302.,40.,-196.082903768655));
#1284=VERTEX_POINT('',#1283);
#1285=EDGE_CURVE('E1437',#1284,#1276,#1282,.T.);
#1286=ORIENTED_EDGE('',*,*,#1285,.F.);
#1287=DIRECTION('',(-0.866025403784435,0.,-0.500000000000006));
#1288=VECTOR('',#1287,1.);
#1289=CARTESIAN_POINT('',(309.,40.,-192.041451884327));
#1290=LINE('',#1289,#1288);
#1291=CARTESIAN_POINT('',(309.,40.,-192.041451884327));
#1292=VERTEX_POINT('',#1291);
#1293=EDGE_CURVE('E1434',#1292,#1284,#1290,.T.);
#1294=ORIENTED_EDGE('',*,*,#1293,.F.);
#1295=DIRECTION('',(0.,0.,-1.));
#1296=VECTOR('',#1295,1.);
#1297=CARTESIAN_POINT('',(309.,40.,-183.958548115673));
#1298=LINE('',#1297,#1296);
#1299=EDGE_CURVE('E1431',#1260,#1292,#1298,.T.);
#1300=ORIENTED_EDGE('',*,*,#1299,.F.);
#1301=EDGE_LOOP('',(#1262,#1270,#1278,#1286,#1294,#1300));
#1302=FACE_BOUND('',#1301,.T.);
#1303=DIRECTION('',(0.,0.,-1.));
#1304=VECTOR('',#1303,1.);
#1305=CARTESIAN_POINT('',(309.,40.,-139.958548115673));
#1306=LINE('',#1305,#1304);
#1307=CARTESIAN_POINT('',(309.,40.,-139.958548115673));
#1308=VERTEX_POINT('',#1307);
#1309=CARTESIAN_POINT('',(309.,40.,-148.041451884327));
#1310=VERTEX_POINT('',#1309);
#1311=EDGE_CURVE('E1447',#1308,#1310,#1306,.T.);
#1312=ORIENTED_EDGE('',*,*,#1311,.F.);
#1313=DIRECTION('',(0.866025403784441,0.,-0.499999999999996));
#1314=VECTOR('',#1313,1.);
#1315=CARTESIAN_POINT('',(302.,40.,-135.917096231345));
#1316=LINE('',#1315,#1314);
#1317=CARTESIAN_POINT('',(302.,40.,-135.917096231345));
#1318=VERTEX_POINT('',#1317);
#1319=EDGE_CURVE('E1462',#1318,#1308,#1316,.T.);
#1320=ORIENTED_EDGE('',*,*,#1319,.F.);
#1321=DIRECTION('',(0.866025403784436,0.,0.500000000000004));
#1322=VECTOR('',#1321,1.);
#1323=CARTESIAN_POINT('',(295.,40.,-139.958548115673));
#1324=LINE('',#1323,#1322);
#1325=CARTESIAN_POINT('',(295.,40.,-139.958548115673));
#1326=VERTEX_POINT('',#1325);
#1327=EDGE_CURVE('E1488',#1326,#1318,#1324,.T.);
#1328=ORIENTED_EDGE('',*,*,#1327,.F.);
#1329=DIRECTION('',(0.,0.,1.));
#1330=VECTOR('',#1329,1.);
#1331=CARTESIAN_POINT('',(295.,40.,-148.041451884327));
#1332=LINE('',#1331,#1330);
#1333=CARTESIAN_POINT('',(295.,40.,-148.041451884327));
#1334=VERTEX_POINT('',#1333);
#1335=EDGE_CURVE('E1485',#1334,#1326,#1332,.T.);
#1336=ORIENTED_EDGE('',*,*,#1335,.F.);
#1337=DIRECTION('',(-0.866025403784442,0.,0.499999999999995));
#1338=VECTOR('',#1337,1.);
#1339=CARTESIAN_POINT('',(302.,40.,-152.082903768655));
#1340=LINE('',#1339,#1338);
#1341=CARTESIAN_POINT('',(302.,40.,-152.082903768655));
#1342=VERTEX_POINT('',#1341);
#1343=EDGE_CURVE('E1482',#1342,#1334,#1340,.T.);
#1344=ORIENTED_EDGE('',*,*,#1343,.F.);
#1345=DIRECTION('',(-0.866025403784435,0.,-0.500000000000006));
#1346=VECTOR('',#1345,1.);
#1347=CARTESIAN_POINT('',(309.,40.,-148.041451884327));
#1348=LINE('',#1347,#1346);
#1349=EDGE_CURVE('E1479',#1310,#1342,#1348,.T.);
#1350=ORIENTED_EDGE('',*,*,#1349,.F.);
#1351=EDGE_LOOP('',(#1312,#1320,#1328,#1336,#1344,#1350));
#1352=FACE_BOUND('',#1351,.T.);
#1353=DIRECTION('',(1.,0.,0.));
#1354=VECTOR('',#1353,1.);
#1355=CARTESIAN_POINT('',(-308.,40.,224.));
#1356=LINE('',#1355,#1354);
#1357=CARTESIAN_POINT('',(-308.,40.,224.));
#1358=VERTEX_POINT('',#1357);
#1359=CARTESIAN_POINT('',(308.,40.,224.));
#1360=VERTEX_POINT('',#1359);
#1361=EDGE_CURVE('E1534',#1358,#1360,#1356,.T.);
#1362=ORIENTED_EDGE('',*,*,#1361,.T.);
#1363=DIRECTION('',(0.,0.,1.));
#1364=VECTOR('',#1363,1.);
#1365=CARTESIAN_POINT('',(308.,40.,-300.));
#1366=LINE('',#1365,#1364);
#1367=EDGE_CURVE('E1506',#1360,#111,#1366,.T.);
#1368=ORIENTED_EDGE('',*,*,#1367,.T.);
#1369=ORIENTED_EDGE('',*,*,#150,.T.);
#1370=ORIENTED_EDGE('',*,*,#32,.T.);
#1371=ORIENTED_EDGE('',*,*,#184,.T.);
#1372=CARTESIAN_POINT('',(308.,40.,-224.));
#1373=VERTEX_POINT('',#1372);
#1374=EDGE_CURVE('E1509',#174,#1373,#1366,.T.);
#1375=ORIENTED_EDGE('',*,*,#1374,.T.);
#1376=DIRECTION('',(-1.,0.,0.));
#1377=VECTOR('',#1376,1.);
#1378=CARTESIAN_POINT('',(308.,40.,-224.));
#1379=LINE('',#1378,#1377);
#1380=CARTESIAN_POINT('',(-308.,40.,-224.));
#1381=VERTEX_POINT('',#1380);
#1382=EDGE_CURVE('E1522',#1373,#1381,#1379,.T.);
#1383=ORIENTED_EDGE('',*,*,#1382,.T.);
#1384=CARTESIAN_POINT('',(-308.,40.,-214.));
#1385=DIRECTION('',(0.,1.,0.));
#1386=DIRECTION('',(0.,0.,1.));
#1387=AXIS2_PLACEMENT_3D('',#1384,#1385,#1386);
#1388=CIRCLE('',#1387,10.0000000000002);
#1389=CARTESIAN_POINT('',(-318.,40.,-214.));
#1390=VERTEX_POINT('',#1389);
#1391=EDGE_CURVE('E1524',#1381,#1390,#1388,.T.);
#1392=ORIENTED_EDGE('',*,*,#1391,.T.);
#1393=DIRECTION('',(0.,0.,1.));
#1394=VECTOR('',#1393,1.);
#1395=CARTESIAN_POINT('',(-318.,40.,-214.));
#1396=LINE('',#1395,#1394);
#1397=CARTESIAN_POINT('',(-318.,40.,214.));
#1398=VERTEX_POINT('',#1397);
#1399=EDGE_CURVE('E1528',#1390,#1398,#1396,.T.);
#1400=ORIENTED_EDGE('',*,*,#1399,.T.);
#1401=CARTESIAN_POINT('',(-308.,40.,214.));
#1402=DIRECTION('',(0.,1.,0.));
#1403=DIRECTION('',(0.,0.,1.));
#1404=AXIS2_PLACEMENT_3D('',#1401,#1402,#1403);
#1405=CIRCLE('',#1404,10.0000000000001);
#1406=EDGE_CURVE('E1531',#1398,#1358,#1405,.T.);
#1407=ORIENTED_EDGE('',*,*,#1406,.T.);
#1408=EDGE_LOOP('',(#1362,#1368,#1369,#1370,#1371,#1375,#1383,#1392,#1400,#1407));
#1409=FACE_BOUND('',#1408,.T.);
#1410=ADVANCED_FACE('F1755',(#602,#652,#702,#752,#802,#852,#902,#952,#1002,#1052,#1102,#1152,
#1202,#1252,#1302,#1352,#1409),#552,.T.);
#1411=CARTESIAN_POINT('',(352.266350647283,40.,224.));
#1412=DIRECTION('',(0.,0.,1.));
#1413=DIRECTION('',(1.,0.,0.));
#1414=AXIS2_PLACEMENT_3D('',#1411,#1412,#1413);
#1415=PLANE('',#1414);
#1416=ORIENTED_EDGE('',*,*,#319,.T.);
#1417=DIRECTION('',(0.925847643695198,-0.377896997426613,0.));
#1418=VECTOR('',#1417,1.);
#1419=CARTESIAN_POINT('',(345.944843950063,24.512308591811,224.));
#1420=LINE('',#1419,#1418);
#1421=EDGE_CURVE('E1512',#310,#1360,#1420,.T.);
#1422=ORIENTED_EDGE('',*,*,#1421,.T.);
#1423=ORIENTED_EDGE('',*,*,#1361,.F.);
#1424=DIRECTION('',(0.,1.,0.));
#1425=VECTOR('',#1424,1.);
#1426=CARTESIAN_POINT('',(-308.,40.,224.));
#1427=LINE('',#1426,#1425);
#1428=EDGE_CURVE('E1548',#1358,#318,#1427,.T.);
#1429=ORIENTED_EDGE('',*,*,#1428,.T.);
#1430=EDGE_LOOP('',(#1416,#1422,#1423,#1429));
#1431=FACE_BOUND('',#1430,.T.);
#1432=ADVANCED_FACE('F1759',(#1431),#1415,.F.);
#1433=CARTESIAN_POINT('',(308.,40.,-224.));
#1434=DIRECTION('',(0.,0.,-1.));
#1435=DIRECTION('',(-1.,0.,0.));
#1436=AXIS2_PLACEMENT_3D('',#1433,#1434,#1435);
#1437=PLANE('',#1436);
#1438=ORIENTED_EDGE('',*,*,#1382,.F.);
#1439=DIRECTION('',(-0.925847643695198,0.377896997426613,0.));
#1440=VECTOR('',#1439,1.);
#1441=CARTESIAN_POINT('',(308.,40.,-224.));
#1442=LINE('',#1441,#1440);
#1443=EDGE_CURVE('E13',#1373,#301,#1442,.T.);
#1444=ORIENTED_EDGE('',*,*,#1443,.T.);
#1445=ORIENTED_EDGE('',*,*,#351,.T.);
#1446=DIRECTION('',(0.,1.,0.));
#1447=VECTOR('',#1446,1.);
#1448=CARTESIAN_POINT('',(-308.,40.,-224.));
#1449=LINE('',#1448,#1447);
#1450=EDGE_CURVE('E1537',#1381,#344,#1449,.T.);
#1451=ORIENTED_EDGE('',*,*,#1450,.F.);
#1452=EDGE_LOOP('',(#1438,#1444,#1445,#1451));
#1453=FACE_BOUND('',#1452,.T.);
#1454=ADVANCED_FACE('F1792',(#1453),#1437,.F.);
#1455=CARTESIAN_POINT('',(-308.,40.,214.));
#1456=DIRECTION('',(0.,1.,0.));
#1457=DIRECTION('',(0.,0.,1.));
#1458=AXIS2_PLACEMENT_3D('',#1455,#1456,#1457);
#1459=CYLINDRICAL_SURFACE('',#1458,10.0000000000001);
#1460=ORIENTED_EDGE('',*,*,#328,.T.);
#1461=ORIENTED_EDGE('',*,*,#1428,.F.);
#1462=ORIENTED_EDGE('',*,*,#1406,.F.);
#1463=DIRECTION('',(0.,1.,0.));
#1464=VECTOR('',#1463,1.);
#1465=CARTESIAN_POINT('',(-318.,40.,214.));
#1466=LINE('',#1465,#1464);
#1467=EDGE_CURVE('E1551',#1398,#327,#1466,.T.);
#1468=ORIENTED_EDGE('',*,*,#1467,.T.);
#1469=EDGE_LOOP('',(#1460,#1461,#1462,#1468));
#1470=FACE_BOUND('',#1469,.T.);
#1471=ADVANCED_FACE('F1800',(#1470),#1459,.F.);
#1472=CARTESIAN_POINT('',(-318.,40.,-214.));
#1473=DIRECTION('',(-1.,0.,0.));
#1474=DIRECTION('',(0.,0.,1.));
#1475=AXIS2_PLACEMENT_3D('',#1472,#1473,#1474);
#1476=PLANE('',#1475);
#1477=ORIENTED_EDGE('',*,*,#336,.T.);
#1478=ORIENTED_EDGE('',*,*,#1467,.F.);
#1479=ORIENTED_EDGE('',*,*,#1399,.F.);
#1480=DIRECTION('',(0.,1.,0.));
#1481=VECTOR('',#1480,1.);
#1482=CARTESIAN_POINT('',(-318.,40.,-214.));
#1483=LINE('',#1482,#1481);
#1484=EDGE_CURVE('E1553',#1390,#335,#1483,.T.);
#1485=ORIENTED_EDGE('',*,*,#1484,.T.);
#1486=EDGE_LOOP('',(#1477,#1478,#1479,#1485));
#1487=FACE_BOUND('',#1486,.T.);
#1488=ADVANCED_FACE('F1798',(#1487),#1476,.F.);
#1489=CARTESIAN_POINT('',(-308.,40.,-214.));
#1490=DIRECTION('',(0.,1.,0.));
#1491=DIRECTION('',(0.,0.,1.));
#1492=AXIS2_PLACEMENT_3D('',#1489,#1490,#1491);
#1493=CYLINDRICAL_SURFACE('',#1492,10.0000000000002);
#1494=ORIENTED_EDGE('',*,*,#345,.T.);
#1495=ORIENTED_EDGE('',*,*,#1484,.F.);
#1496=ORIENTED_EDGE('',*,*,#1391,.F.);
#1497=ORIENTED_EDGE('',*,*,#1450,.T.);
#1498=EDGE_LOOP('',(#1494,#1495,#1496,#1497));
#1499=FACE_BOUND('',#1498,.T.);
#1500=ADVANCED_FACE('F1795',(#1499),#1493,.F.);
#1501=CARTESIAN_POINT('',(308.,40.,-300.));
#1502=DIRECTION('',(-0.377896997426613,-0.925847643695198,0.));
#1503=DIRECTION('',(0.925847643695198,-0.377896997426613,0.));
#1504=AXIS2_PLACEMENT_3D('',#1501,#1502,#1503);
#1505=PLANE('',#1504);
#1506=ORIENTED_EDGE('',*,*,#302,.T.);
#1507=ORIENTED_EDGE('',*,*,#1443,.F.);
#1508=ORIENTED_EDGE('',*,*,#1374,.F.);
#1509=ORIENTED_EDGE('',*,*,#216,.F.);
#1510=EDGE_LOOP('',(#1506,#1507,#1508,#1509));
#1511=FACE_BOUND('',#1510,.T.);
#1512=ADVANCED_FACE('F1785',(#1511),#1505,.F.);
#1513=ORIENTED_EDGE('',*,*,#1367,.F.);
#1514=ORIENTED_EDGE('',*,*,#1421,.F.);
#1515=ORIENTED_EDGE('',*,*,#311,.T.);
#1516=ORIENTED_EDGE('',*,*,#122,.F.);
#1517=EDGE_LOOP('',(#1513,#1514,#1515,#1516));
#1518=FACE_BOUND('',#1517,.T.);
#1519=ADVANCED_FACE('F1753',(#1518),#1505,.F.);
#1520=CARTESIAN_POINT('',(309.,34.5,-139.958548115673));
#1521=DIRECTION('',(1.,0.,0.));
#1522=DIRECTION('',(0.,0.,-1.));
#1523=AXIS2_PLACEMENT_3D('',#1520,#1521,#1522);
#1524=PLANE('',#1523);
#1525=ORIENTED_EDGE('',*,*,#1311,.T.);
#1526=DIRECTION('',(0.,1.,0.));
#1527=VECTOR('',#1526,1.);
#1528=CARTESIAN_POINT('',(309.,34.5,-148.041451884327));
#1529=LINE('',#1528,#1527);
#1530=CARTESIAN_POINT('',(309.,34.5,-148.041451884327));
#1531=VERTEX_POINT('',#1530);
#1532=EDGE_CURVE('E1477',#1531,#1310,#1529,.T.);
#1533=ORIENTED_EDGE('',*,*,#1532,.F.);
#1534=DIRECTION('',(0.,0.,-1.));
#1535=VECTOR('',#1534,1.);
#1536=CARTESIAN_POINT('',(309.,34.5,-139.958548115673));
#1537=LINE('',#1536,#1535);
#1538=CARTESIAN_POINT('',(309.,34.5,-139.958548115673));
#1539=VERTEX_POINT('',#1538);
#1540=EDGE_CURVE('E1458',#1539,#1531,#1537,.T.);
#1541=ORIENTED_EDGE('',*,*,#1540,.F.);
#1542=DIRECTION('',(0.,1.,0.));
#1543=VECTOR('',#1542,1.);
#1544=CARTESIAN_POINT('',(309.,34.5,-139.958548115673));
#1545=LINE('',#1544,#1543);
#1546=EDGE_CURVE('E1493',#1539,#1308,#1545,.T.);
#1547=ORIENTED_EDGE('',*,*,#1546,.T.);
#1548=EDGE_LOOP('',(#1525,#1533,#1541,#1547));
#1549=FACE_BOUND('',#1548,.T.);
#1550=ADVANCED_FACE('F1926',(#1549),#1524,.F.);
#1551=CARTESIAN_POINT('',(302.,34.5,-135.917096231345));
#1552=DIRECTION('',(0.499999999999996,0.,0.866025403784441));
#1553=DIRECTION('',(0.866025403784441,0.,-0.499999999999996));
#1554=AXIS2_PLACEMENT_3D('',#1551,#1552,#1553);
#1555=PLANE('',#1554);
#1556=ORIENTED_EDGE('',*,*,#1319,.T.);
#1557=ORIENTED_EDGE('',*,*,#1546,.F.);
#1558=DIRECTION('',(0.866025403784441,0.,-0.499999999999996));
#1559=VECTOR('',#1558,1.);
#1560=CARTESIAN_POINT('',(302.,34.5,-135.917096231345));
#1561=LINE('',#1560,#1559);
#1562=CARTESIAN_POINT('',(302.,34.5,-135.917096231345));
#1563=VERTEX_POINT('',#1562);
#1564=EDGE_CURVE('E1474',#1563,#1539,#1561,.T.);
#1565=ORIENTED_EDGE('',*,*,#1564,.F.);
#1566=DIRECTION('',(0.,1.,0.));
#1567=VECTOR('',#1566,1.);
#1568=CARTESIAN_POINT('',(302.,34.5,-135.917096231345));
#1569=LINE('',#1568,#1567);
#1570=EDGE_CURVE('E1496',#1563,#1318,#1569,.T.);
#1571=ORIENTED_EDGE('',*,*,#1570,.T.);
#1572=EDGE_LOOP('',(#1556,#1557,#1565,#1571));
#1573=FACE_BOUND('',#1572,.T.);
#1574=ADVANCED_FACE('F1940',(#1573),#1555,.F.);
#1575=CARTESIAN_POINT('',(295.,34.5,-139.958548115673));
#1576=DIRECTION('',(-0.500000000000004,0.,0.866025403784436));
#1577=DIRECTION('',(0.866025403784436,0.,0.500000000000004));
#1578=AXIS2_PLACEMENT_3D('',#1575,#1576,#1577);
#1579=PLANE('',#1578);
#1580=ORIENTED_EDGE('',*,*,#1327,.T.);
#1581=ORIENTED_EDGE('',*,*,#1570,.F.);
#1582=DIRECTION('',(0.866025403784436,0.,0.500000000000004));
#1583=VECTOR('',#1582,1.);
#1584=CARTESIAN_POINT('',(295.,34.5,-139.958548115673));
#1585=LINE('',#1584,#1583);
#1586=CARTESIAN_POINT('',(295.,34.5,-139.958548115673));
#1587=VERTEX_POINT('',#1586);
#1588=EDGE_CURVE('E1471',#1587,#1563,#1585,.T.);
#1589=ORIENTED_EDGE('',*,*,#1588,.F.);
#1590=DIRECTION('',(0.,1.,0.));
#1591=VECTOR('',#1590,1.);
#1592=CARTESIAN_POINT('',(295.,34.5,-139.958548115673));
#1593=LINE('',#1592,#1591);
#1594=EDGE_CURVE('E1498',#1587,#1326,#1593,.T.);
#1595=ORIENTED_EDGE('',*,*,#1594,.T.);
#1596=EDGE_LOOP('',(#1580,#1581,#1589,#1595));
#1597=FACE_BOUND('',#1596,.T.);
#1598=ADVANCED_FACE('F1950',(#1597),#1579,.F.);
#1599=CARTESIAN_POINT('',(295.,34.5,-148.041451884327));
#1600=DIRECTION('',(-1.,0.,0.));
#1601=DIRECTION('',(0.,0.,1.));
#1602=AXIS2_PLACEMENT_3D('',#1599,#1600,#1601);
#1603=PLANE('',#1602);
#1604=ORIENTED_EDGE('',*,*,#1335,.T.);
#1605=ORIENTED_EDGE('',*,*,#1594,.F.);
#1606=DIRECTION('',(0.,0.,1.));
#1607=VECTOR('',#1606,1.);
#1608=CARTESIAN_POINT('',(295.,34.5,-148.041451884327));
#1609=LINE('',#1608,#1607);
#1610=CARTESIAN_POINT('',(295.,34.5,-148.041451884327));
#1611=VERTEX_POINT('',#1610);
#1612=EDGE_CURVE('E1468',#1611,#1587,#1609,.T.);
#1613=ORIENTED_EDGE('',*,*,#1612,.F.);
#1614=DIRECTION('',(0.,1.,0.));
#1615=VECTOR('',#1614,1.);
#1616=CARTESIAN_POINT('',(295.,34.5,-148.041451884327));
#1617=LINE('',#1616,#1615);
#1618=EDGE_CURVE('E1500',#1611,#1334,#1617,.T.);
#1619=ORIENTED_EDGE('',*,*,#1618,.T.);
#1620=EDGE_LOOP('',(#1604,#1605,#1613,#1619));
#1621=FACE_BOUND('',#1620,.T.);
#1622=ADVANCED_FACE('F1960',(#1621),#1603,.F.);
#1623=CARTESIAN_POINT('',(302.,34.5,-152.082903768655));
#1624=DIRECTION('',(-0.499999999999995,0.,-0.866025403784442));
#1625=DIRECTION('',(-0.866025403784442,0.,0.499999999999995));
#1626=AXIS2_PLACEMENT_3D('',#1623,#1624,#1625);
#1627=PLANE('',#1626);
#1628=ORIENTED_EDGE('',*,*,#1343,.T.);
#1629=ORIENTED_EDGE('',*,*,#1618,.F.);
#1630=DIRECTION('',(-0.866025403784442,0.,0.499999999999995));
#1631=VECTOR('',#1630,1.);
#1632=CARTESIAN_POINT('',(302.,34.5,-152.082903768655));
#1633=LINE('',#1632,#1631);
#1634=CARTESIAN_POINT('',(302.,34.5,-152.082903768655));
#1635=VERTEX_POINT('',#1634);
#1636=EDGE_CURVE('E1465',#1635,#1611,#1633,.T.);
#1637=ORIENTED_EDGE('',*,*,#1636,.F.);
#1638=DIRECTION('',(0.,1.,0.));
#1639=VECTOR('',#1638,1.);
#1640=CARTESIAN_POINT('',(302.,34.5,-152.082903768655));
#1641=LINE('',#1640,#1639);
#1642=EDGE_CURVE('E1502',#1635,#1342,#1641,.T.);
#1643=ORIENTED_EDGE('',*,*,#1642,.T.);
#1644=EDGE_LOOP('',(#1628,#1629,#1637,#1643));
#1645=FACE_BOUND('',#1644,.T.);
#1646=ADVANCED_FACE('F1970',(#1645),#1627,.F.);
#1647=CARTESIAN_POINT('',(309.,34.5,-148.041451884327));
#1648=DIRECTION('',(0.500000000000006,0.,-0.866025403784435));
#1649=DIRECTION('',(-0.866025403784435,0.,-0.500000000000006));
#1650=AXIS2_PLACEMENT_3D('',#1647,#1648,#1649);
#1651=PLANE('',#1650);
#1652=ORIENTED_EDGE('',*,*,#1349,.T.);
#1653=ORIENTED_EDGE('',*,*,#1642,.F.);
#1654=DIRECTION('',(-0.866025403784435,0.,-0.500000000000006));
#1655=VECTOR('',#1654,1.);
#1656=CARTESIAN_POINT('',(309.,34.5,-148.041451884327));
#1657=LINE('',#1656,#1655);
#1658=EDGE_CURVE('E1461',#1531,#1635,#1657,.T.);
#1659=ORIENTED_EDGE('',*,*,#1658,.F.);
#1660=ORIENTED_EDGE('',*,*,#1532,.T.);
#1661=EDGE_LOOP('',(#1652,#1653,#1659,#1660));
#1662=FACE_BOUND('',#1661,.T.);
#1663=ADVANCED_FACE('F1980',(#1662),#1651,.F.);
#1664=CARTESIAN_POINT('',(0.,34.5,0.));
#1665=DIRECTION('',(0.,1.,0.));
#1666=DIRECTION('',(0.,0.,1.));
#1667=AXIS2_PLACEMENT_3D('',#1664,#1665,#1666);
#1668=PLANE('',#1667);
#1669=CARTESIAN_POINT('',(302.,34.5,-144.));
#1670=DIRECTION('',(0.,1.,0.));
#1671=DIRECTION('',(0.,0.,1.));
#1672=AXIS2_PLACEMENT_3D('',#1669,#1670,#1671);
#1673=CIRCLE('',#1672,3.99999999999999);
#1674=CARTESIAN_POINT('',(302.,34.5,-140.));
#1675=VERTEX_POINT('',#1674);
#1676=EDGE_CURVE('E1669',#1675,#1675,#1673,.T.);
#1677=ORIENTED_EDGE('',*,*,#1676,.F.);
#1678=EDGE_LOOP('',(#1677));
#1679=FACE_BOUND('',#1678,.T.);
#1680=ORIENTED_EDGE('',*,*,#1540,.T.);
#1681=ORIENTED_EDGE('',*,*,#1658,.T.);
#1682=ORIENTED_EDGE('',*,*,#1636,.T.);
#1683=ORIENTED_EDGE('',*,*,#1612,.T.);
#1684=ORIENTED_EDGE('',*,*,#1588,.T.);
#1685=ORIENTED_EDGE('',*,*,#1564,.T.);
#1686=EDGE_LOOP('',(#1680,#1681,#1682,#1683,#1684,#1685));
#1687=FACE_BOUND('',#1686,.T.);
#1688=ADVANCED_FACE('F1990',(#1679,#1687),#1668,.T.);
#1689=CARTESIAN_POINT('',(302.,34.5,-179.917096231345));
#1690=DIRECTION('',(0.499999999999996,0.,0.866025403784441));
#1691=DIRECTION('',(0.866025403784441,0.,-0.499999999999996));
#1692=AXIS2_PLACEMENT_3D('',#1689,#1690,#1691);
#1693=PLANE('',#1692);
#1694=ORIENTED_EDGE('',*,*,#1261,.T.);
#1695=DIRECTION('',(0.,1.,0.));
#1696=VECTOR('',#1695,1.);
#1697=CARTESIAN_POINT('',(309.,34.5,-183.958548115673));
#1698=LINE('',#1697,#1696);
#1699=CARTESIAN_POINT('',(309.,34.5,-183.958548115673));
#1700=VERTEX_POINT('',#1699);
#1701=EDGE_CURVE('E1429',#1700,#1260,#1698,.T.);
#1702=ORIENTED_EDGE('',*,*,#1701,.F.);
#1703=DIRECTION('',(0.866025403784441,0.,-0.499999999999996));
#1704=VECTOR('',#1703,1.);
#1705=CARTESIAN_POINT('',(302.,34.5,-179.917096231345));
#1706=LINE('',#1705,#1704);
#1707=CARTESIAN_POINT('',(302.,34.5,-179.917096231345));
#1708=VERTEX_POINT('',#1707);
#1709=EDGE_CURVE('E1410',#1708,#1700,#1706,.T.);
#1710=ORIENTED_EDGE('',*,*,#1709,.F.);
#1711=DIRECTION('',(0.,1.,0.));
#1712=VECTOR('',#1711,1.);
#1713=CARTESIAN_POINT('',(302.,34.5,-179.917096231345));
#1714=LINE('',#1713,#1712);
#1715=EDGE_CURVE('E1445',#1708,#1258,#1714,.T.);
#1716=ORIENTED_EDGE('',*,*,#1715,.T.);
#1717=EDGE_LOOP('',(#1694,#1702,#1710,#1716));
#1718=FACE_BOUND('',#1717,.T.);
#1719=ADVANCED_FACE('F1998',(#1718),#1693,.F.);
#1720=CARTESIAN_POINT('',(295.,34.5,-183.958548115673));
#1721=DIRECTION('',(-0.500000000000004,0.,0.866025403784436));
#1722=DIRECTION('',(0.866025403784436,0.,0.500000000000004));
#1723=AXIS2_PLACEMENT_3D('',#1720,#1721,#1722);
#1724=PLANE('',#1723);
#1725=ORIENTED_EDGE('',*,*,#1269,.T.);
#1726=ORIENTED_EDGE('',*,*,#1715,.F.);
#1727=DIRECTION('',(0.866025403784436,0.,0.500000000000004));
#1728=VECTOR('',#1727,1.);
#1729=CARTESIAN_POINT('',(295.,34.5,-183.958548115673));
#1730=LINE('',#1729,#1728);
#1731=CARTESIAN_POINT('',(295.,34.5,-183.958548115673));
#1732=VERTEX_POINT('',#1731);
#1733=EDGE_CURVE('E1426',#1732,#1708,#1730,.T.);
#1734=ORIENTED_EDGE('',*,*,#1733,.F.);
#1735=DIRECTION('',(0.,1.,0.));
#1736=VECTOR('',#1735,1.);
#1737=CARTESIAN_POINT('',(295.,34.5,-183.958548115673));
#1738=LINE('',#1737,#1736);
#1739=EDGE_CURVE('E1448',#1732,#1268,#1738,.T.);
#1740=ORIENTED_EDGE('',*,*,#1739,.T.);
#1741=EDGE_LOOP('',(#1725,#1726,#1734,#1740));
#1742=FACE_BOUND('',#1741,.T.);
#1743=ADVANCED_FACE('F2003',(#1742),#1724,.F.);
#1744=CARTESIAN_POINT('',(295.,34.5,-192.041451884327));
#1745=DIRECTION('',(-1.,0.,0.));
#1746=DIRECTION('',(0.,0.,1.));
#1747=AXIS2_PLACEMENT_3D('',#1744,#1745,#1746);
#1748=PLANE('',#1747);
#1749=ORIENTED_EDGE('',*,*,#1277,.T.);
#1750=ORIENTED_EDGE('',*,*,#1739,.F.);
#1751=DIRECTION('',(0.,0.,1.));
#1752=VECTOR('',#1751,1.);
#1753=CARTESIAN_POINT('',(295.,34.5,-192.041451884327));
#1754=LINE('',#1753,#1752);
#1755=CARTESIAN_POINT('',(295.,34.5,-192.041451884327));
#1756=VERTEX_POINT('',#1755);
#1757=EDGE_CURVE('E1423',#1756,#1732,#1754,.T.);
#1758=ORIENTED_EDGE('',*,*,#1757,.F.);
#1759=DIRECTION('',(0.,1.,0.));
#1760=VECTOR('',#1759,1.);
#1761=CARTESIAN_POINT('',(295.,34.5,-192.041451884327));
#1762=LINE('',#1761,#1760);
#1763=EDGE_CURVE('E1450',#1756,#1276,#1762,.T.);
#1764=ORIENTED_EDGE('',*,*,#1763,.T.);
#1765=EDGE_LOOP('',(#1749,#1750,#1758,#1764));
#1766=FACE_BOUND('',#1765,.T.);
#1767=ADVANCED_FACE('F2013',(#1766),#1748,.F.);
#1768=CARTESIAN_POINT('',(302.,34.5,-196.082903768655));
#1769=DIRECTION('',(-0.499999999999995,0.,-0.866025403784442));
#1770=DIRECTION('',(-0.866025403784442,0.,0.499999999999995));
#1771=AXIS2_PLACEMENT_3D('',#1768,#1769,#1770);
#1772=PLANE('',#1771);
#1773=ORIENTED_EDGE('',*,*,#1285,.T.);
#1774=ORIENTED_EDGE('',*,*,#1763,.F.);
#1775=DIRECTION('',(-0.866025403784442,0.,0.499999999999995));
#1776=VECTOR('',#1775,1.);
#1777=CARTESIAN_POINT('',(302.,34.5,-196.082903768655));
#1778=LINE('',#1777,#1776);
#1779=CARTESIAN_POINT('',(302.,34.5,-196.082903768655));
#1780=VERTEX_POINT('',#1779);
#1781=EDGE_CURVE('E1420',#1780,#1756,#1778,.T.);
#1782=ORIENTED_EDGE('',*,*,#1781,.F.);
#1783=DIRECTION('',(0.,1.,0.));
#1784=VECTOR('',#1783,1.);
#1785=CARTESIAN_POINT('',(302.,34.5,-196.082903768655));
#1786=LINE('',#1785,#1784);
#1787=EDGE_CURVE('E1452',#1780,#1284,#1786,.T.);
#1788=ORIENTED_EDGE('',*,*,#1787,.T.);
#1789=EDGE_LOOP('',(#1773,#1774,#1782,#1788));
#1790=FACE_BOUND('',#1789,.T.);
#1791=ADVANCED_FACE('F2023',(#1790),#1772,.F.);
#1792=CARTESIAN_POINT('',(309.,34.5,-192.041451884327));
#1793=DIRECTION('',(0.500000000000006,0.,-0.866025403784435));
#1794=DIRECTION('',(-0.866025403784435,0.,-0.500000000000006));
#1795=AXIS2_PLACEMENT_3D('',#1792,#1793,#1794);
#1796=PLANE('',#1795);
#1797=ORIENTED_EDGE('',*,*,#1293,.T.);
#1798=ORIENTED_EDGE('',*,*,#1787,.F.);
#1799=DIRECTION('',(-0.866025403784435,0.,-0.500000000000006));
#1800=VECTOR('',#1799,1.);
#1801=CARTESIAN_POINT('',(309.,34.5,-192.041451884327));
#1802=LINE('',#1801,#1800);
#1803=CARTESIAN_POINT('',(309.,34.5,-192.041451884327));
#1804=VERTEX_POINT('',#1803);
#1805=EDGE_CURVE('E1417',#1804,#1780,#1802,.T.);
#1806=ORIENTED_EDGE('',*,*,#1805,.F.);
#1807=DIRECTION('',(0.,1.,0.));
#1808=VECTOR('',#1807,1.);
#1809=CARTESIAN_POINT('',(309.,34.5,-192.041451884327));
#1810=LINE('',#1809,#1808);
#1811=EDGE_CURVE('E1454',#1804,#1292,#1810,.T.);
#1812=ORIENTED_EDGE('',*,*,#1811,.T.);
#1813=EDGE_LOOP('',(#1797,#1798,#1806,#1812));
#1814=FACE_BOUND('',#1813,.T.);
#1815=ADVANCED_FACE('F2033',(#1814),#1796,.F.);
#1816=CARTESIAN_POINT('',(309.,34.5,-183.958548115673));
#1817=DIRECTION('',(1.,0.,0.));
#1818=DIRECTION('',(0.,0.,-1.));
#1819=AXIS2_PLACEMENT_3D('',#1816,#1817,#1818);
#1820=PLANE('',#1819);
#1821=ORIENTED_EDGE('',*,*,#1299,.T.);
#1822=ORIENTED_EDGE('',*,*,#1811,.F.);
#1823=DIRECTION('',(0.,0.,-1.));
#1824=VECTOR('',#1823,1.);
#1825=CARTESIAN_POINT('',(309.,34.5,-183.958548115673));
#1826=LINE('',#1825,#1824);
#1827=EDGE_CURVE('E1413',#1700,#1804,#1826,.T.);
#1828=ORIENTED_EDGE('',*,*,#1827,.F.);
#1829=ORIENTED_EDGE('',*,*,#1701,.T.);
#1830=EDGE_LOOP('',(#1821,#1822,#1828,#1829));
#1831=FACE_BOUND('',#1830,.T.);
#1832=ADVANCED_FACE('F2043',(#1831),#1820,.F.);
#1833=CARTESIAN_POINT('',(0.,34.5,0.));
#1834=DIRECTION('',(0.,1.,0.));
#1835=DIRECTION('',(0.,0.,1.));
#1836=AXIS2_PLACEMENT_3D('',#1833,#1834,#1835);
#1837=PLANE('',#1836);
#1838=CARTESIAN_POINT('',(302.,34.5,-188.));
#1839=DIRECTION('',(0.,1.,0.));
#1840=DIRECTION('',(0.,0.,1.));
#1841=AXIS2_PLACEMENT_3D('',#1838,#1839,#1840);
#1842=CIRCLE('',#1841,3.99999999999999);
#1843=CARTESIAN_POINT('',(302.,34.5,-184.));
#1844=VERTEX_POINT('',#1843);
#1845=EDGE_CURVE('E48',#1844,#1844,#1842,.T.);
#1846=ORIENTED_EDGE('',*,*,#1845,.F.);
#1847=EDGE_LOOP('',(#1846));
#1848=FACE_BOUND('',#1847,.T.);
#1849=ORIENTED_EDGE('',*,*,#1709,.T.);
#1850=ORIENTED_EDGE('',*,*,#1827,.T.);
#1851=ORIENTED_EDGE('',*,*,#1805,.T.);
#1852=ORIENTED_EDGE('',*,*,#1781,.T.);
#1853=ORIENTED_EDGE('',*,*,#1757,.T.);
#1854=ORIENTED_EDGE('',*,*,#1733,.T.);
#1855=EDGE_LOOP('',(#1849,#1850,#1851,#1852,#1853,#1854));
#1856=FACE_BOUND('',#1855,.T.);
#1857=ADVANCED_FACE('F2053',(#1848,#1856),#1837,.T.);
#1858=CARTESIAN_POINT('',(236.,34.5,-139.958548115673));
#1859=DIRECTION('',(1.,0.,0.));
#1860=DIRECTION('',(0.,0.,-1.));
#1861=AXIS2_PLACEMENT_3D('',#1858,#1859,#1860);
#1862=PLANE('',#1861);
#1863=ORIENTED_EDGE('',*,*,#1211,.T.);
#1864=DIRECTION('',(0.,1.,0.));
#1865=VECTOR('',#1864,1.);
#1866=CARTESIAN_POINT('',(236.,34.5,-148.041451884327));
#1867=LINE('',#1866,#1865);
#1868=CARTESIAN_POINT('',(236.,34.5,-148.041451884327));
#1869=VERTEX_POINT('',#1868);
#1870=EDGE_CURVE('E1381',#1869,#1210,#1867,.T.);
#1871=ORIENTED_EDGE('',*,*,#1870,.F.);
#1872=DIRECTION('',(0.,0.,-1.));
#1873=VECTOR('',#1872,1.);
#1874=CARTESIAN_POINT('',(236.,34.5,-139.958548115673));
#1875=LINE('',#1874,#1873);
#1876=CARTESIAN_POINT('',(236.,34.5,-139.958548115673));
#1877=VERTEX_POINT('',#1876);
#1878=EDGE_CURVE('E1362',#1877,#1869,#1875,.T.);
#1879=ORIENTED_EDGE('',*,*,#1878,.F.);
#1880=DIRECTION('',(0.,1.,0.));
#1881=VECTOR('',#1880,1.);
#1882=CARTESIAN_POINT('',(236.,34.5,-139.958548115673));
#1883=LINE('',#1882,#1881);
#1884=EDGE_CURVE('E1397',#1877,#1208,#1883,.T.);
#1885=ORIENTED_EDGE('',*,*,#1884,.T.);
#1886=EDGE_LOOP('',(#1863,#1871,#1879,#1885));
#1887=FACE_BOUND('',#1886,.T.);
#1888=ADVANCED_FACE('F2061',(#1887),#1862,.F.);
#1889=CARTESIAN_POINT('',(229.,34.5,-135.917096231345));
#1890=DIRECTION('',(0.499999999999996,0.,0.866025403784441));
#1891=DIRECTION('',(0.866025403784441,0.,-0.499999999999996));
#1892=AXIS2_PLACEMENT_3D('',#1889,#1890,#1891);
#1893=PLANE('',#1892);
#1894=ORIENTED_EDGE('',*,*,#1219,.T.);
#1895=ORIENTED_EDGE('',*,*,#1884,.F.);
#1896=DIRECTION('',(0.866025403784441,0.,-0.499999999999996));
#1897=VECTOR('',#1896,1.);
#1898=CARTESIAN_POINT('',(229.,34.5,-135.917096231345));
#1899=LINE('',#1898,#1897);
#1900=CARTESIAN_POINT('',(229.,34.5,-135.917096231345));
#1901=VERTEX_POINT('',#1900);
#1902=EDGE_CURVE('E1378',#1901,#1877,#1899,.T.);
#1903=ORIENTED_EDGE('',*,*,#1902,.F.);
#1904=DIRECTION('',(0.,1.,0.));
#1905=VECTOR('',#1904,1.);
#1906=CARTESIAN_POINT('',(229.,34.5,-135.917096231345));
#1907=LINE('',#1906,#1905);
#1908=EDGE_CURVE('E1400',#1901,#1218,#1907,.T.);
#1909=ORIENTED_EDGE('',*,*,#1908,.T.);
#1910=EDGE_LOOP('',(#1894,#1895,#1903,#1909));
#1911=FACE_BOUND('',#1910,.T.);
#1912=ADVANCED_FACE('F2066',(#1911),#1893,.F.);
#1913=CARTESIAN_POINT('',(222.,34.5,-139.958548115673));
#1914=DIRECTION('',(-0.500000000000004,0.,0.866025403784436));
#1915=DIRECTION('',(0.866025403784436,0.,0.500000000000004));
#1916=AXIS2_PLACEMENT_3D('',#1913,#1914,#1915);
#1917=PLANE('',#1916);
#1918=ORIENTED_EDGE('',*,*,#1227,.T.);
#1919=ORIENTED_EDGE('',*,*,#1908,.F.);
#1920=DIRECTION('',(0.866025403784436,0.,0.500000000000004));
#1921=VECTOR('',#1920,1.);
#1922=CARTESIAN_POINT('',(222.,34.5,-139.958548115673));
#1923=LINE('',#1922,#1921);
#1924=CARTESIAN_POINT('',(222.,34.5,-139.958548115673));
#1925=VERTEX_POINT('',#1924);
#1926=EDGE_CURVE('E1375',#1925,#1901,#1923,.T.);
#1927=ORIENTED_EDGE('',*,*,#1926,.F.);
#1928=DIRECTION('',(0.,1.,0.));
#1929=VECTOR('',#1928,1.);
#1930=CARTESIAN_POINT('',(222.,34.5,-139.958548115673));
#1931=LINE('',#1930,#1929);
#1932=EDGE_CURVE('E1402',#1925,#1226,#1931,.T.);
#1933=ORIENTED_EDGE('',*,*,#1932,.T.);
#1934=EDGE_LOOP('',(#1918,#1919,#1927,#1933));
#1935=FACE_BOUND('',#1934,.T.);
#1936=ADVANCED_FACE('F2076',(#1935),#1917,.F.);
#1937=CARTESIAN_POINT('',(222.,34.5,-148.041451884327));
#1938=DIRECTION('',(-1.,0.,0.));
#1939=DIRECTION('',(0.,0.,1.));
#1940=AXIS2_PLACEMENT_3D('',#1937,#1938,#1939);
#1941=PLANE('',#1940);
#1942=ORIENTED_EDGE('',*,*,#1235,.T.);
#1943=ORIENTED_EDGE('',*,*,#1932,.F.);
#1944=DIRECTION('',(0.,0.,1.));
#1945=VECTOR('',#1944,1.);
#1946=CARTESIAN_POINT('',(222.,34.5,-148.041451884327));
#1947=LINE('',#1946,#1945);
#1948=CARTESIAN_POINT('',(222.,34.5,-148.041451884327));
#1949=VERTEX_POINT('',#1948);
#1950=EDGE_CURVE('E1372',#1949,#1925,#1947,.T.);
#1951=ORIENTED_EDGE('',*,*,#1950,.F.);
#1952=DIRECTION('',(0.,1.,0.));
#1953=VECTOR('',#1952,1.);
#1954=CARTESIAN_POINT('',(222.,34.5,-148.041451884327));
#1955=LINE('',#1954,#1953);
#1956=EDGE_CURVE('E1404',#1949,#1234,#1955,.T.);
#1957=ORIENTED_EDGE('',*,*,#1956,.T.);
#1958=EDGE_LOOP('',(#1942,#1943,#1951,#1957));
#1959=FACE_BOUND('',#1958,.T.);
#1960=ADVANCED_FACE('F2086',(#1959),#1941,.F.);
#1961=CARTESIAN_POINT('',(229.,34.5,-152.082903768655));
#1962=DIRECTION('',(-0.499999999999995,0.,-0.866025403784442));
#1963=DIRECTION('',(-0.866025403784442,0.,0.499999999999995));
#1964=AXIS2_PLACEMENT_3D('',#1961,#1962,#1963);
#1965=PLANE('',#1964);
#1966=ORIENTED_EDGE('',*,*,#1243,.T.);
#1967=ORIENTED_EDGE('',*,*,#1956,.F.);
#1968=DIRECTION('',(-0.866025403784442,0.,0.499999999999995));
#1969=VECTOR('',#1968,1.);
#1970=CARTESIAN_POINT('',(229.,34.5,-152.082903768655));
#1971=LINE('',#1970,#1969);
#1972=CARTESIAN_POINT('',(229.,34.5,-152.082903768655));
#1973=VERTEX_POINT('',#1972);
#1974=EDGE_CURVE('E1369',#1973,#1949,#1971,.T.);
#1975=ORIENTED_EDGE('',*,*,#1974,.F.);
#1976=DIRECTION('',(0.,1.,0.));
#1977=VECTOR('',#1976,1.);
#1978=CARTESIAN_POINT('',(229.,34.5,-152.082903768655));
#1979=LINE('',#1978,#1977);
#1980=EDGE_CURVE('E1406',#1973,#1242,#1979,.T.);
#1981=ORIENTED_EDGE('',*,*,#1980,.T.);
#1982=EDGE_LOOP('',(#1966,#1967,#1975,#1981));
#1983=FACE_BOUND('',#1982,.T.);
#1984=ADVANCED_FACE('F2096',(#1983),#1965,.F.);
#1985=CARTESIAN_POINT('',(236.,34.5,-148.041451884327));
#1986=DIRECTION('',(0.500000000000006,0.,-0.866025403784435));
#1987=DIRECTION('',(-0.866025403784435,0.,-0.500000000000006));
#1988=AXIS2_PLACEMENT_3D('',#1985,#1986,#1987);
#1989=PLANE('',#1988);
#1990=ORIENTED_EDGE('',*,*,#1249,.T.);
#1991=ORIENTED_EDGE('',*,*,#1980,.F.);
#1992=DIRECTION('',(-0.866025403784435,0.,-0.500000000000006));
#1993=VECTOR('',#1992,1.);
#1994=CARTESIAN_POINT('',(236.,34.5,-148.041451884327));
#1995=LINE('',#1994,#1993);
#1996=EDGE_CURVE('E1365',#1869,#1973,#1995,.T.);
#1997=ORIENTED_EDGE('',*,*,#1996,.F.);
#1998=ORIENTED_EDGE('',*,*,#1870,.T.);
#1999=EDGE_LOOP('',(#1990,#1991,#1997,#1998));
#2000=FACE_BOUND('',#1999,.T.);
#2001=ADVANCED_FACE('F2106',(#2000),#1989,.F.);
#2002=CARTESIAN_POINT('',(0.,34.5,0.));
#2003=DIRECTION('',(0.,1.,0.));
#2004=DIRECTION('',(0.,0.,1.));
#2005=AXIS2_PLACEMENT_3D('',#2002,#2003,#2004);
#2006=PLANE('',#2005);
#2007=CARTESIAN_POINT('',(229.,34.5,-144.));
#2008=DIRECTION('',(0.,1.,0.));
#2009=DIRECTION('',(0.,0.,1.));
#2010=AXIS2_PLACEMENT_3D('',#2007,#2008,#2009);
#2011=CIRCLE('',#2010,3.99999999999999);
#2012=CARTESIAN_POINT('',(229.,34.5,-140.));
#2013=VERTEX_POINT('',#2012);
#2014=EDGE_CURVE('E1666',#2013,#2013,#2011,.T.);
#2015=ORIENTED_EDGE('',*,*,#2014,.F.);
#2016=EDGE_LOOP('',(#2015));
#2017=FACE_BOUND('',#2016,.T.);
#2018=ORIENTED_EDGE('',*,*,#1878,.T.);
#2019=ORIENTED_EDGE('',*,*,#1996,.T.);
#2020=ORIENTED_EDGE('',*,*,#1974,.T.);
#2021=ORIENTED_EDGE('',*,*,#1950,.T.);
#2022=ORIENTED_EDGE('',*,*,#1926,.T.);
#2023=ORIENTED_EDGE('',*,*,#1902,.T.);
#2024=EDGE_LOOP('',(#2018,#2019,#2020,#2021,#2022,#2023));
#2025=FACE_BOUND('',#2024,.T.);
#2026=ADVANCED_FACE('F2116',(#2017,#2025),#2006,.T.);
#2027=CARTESIAN_POINT('',(236.,34.5,-183.958548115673));
#2028=DIRECTION('',(1.,0.,0.));
#2029=DIRECTION('',(0.,0.,-1.));
#2030=AXIS2_PLACEMENT_3D('',#2027,#2028,#2029);
#2031=PLANE('',#2030);
#2032=ORIENTED_EDGE('',*,*,#1161,.T.);
#2033=DIRECTION('',(0.,1.,0.));
#2034=VECTOR('',#2033,1.);
#2035=CARTESIAN_POINT('',(236.,34.5,-192.041451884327));
#2036=LINE('',#2035,#2034);
#2037=CARTESIAN_POINT('',(236.,34.5,-192.041451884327));
#2038=VERTEX_POINT('',#2037);
#2039=EDGE_CURVE('E1333',#2038,#1160,#2036,.T.);
#2040=ORIENTED_EDGE('',*,*,#2039,.F.);
#2041=DIRECTION('',(0.,0.,-1.));
#2042=VECTOR('',#2041,1.);
#2043=CARTESIAN_POINT('',(236.,34.5,-183.958548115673));
#2044=LINE('',#2043,#2042);
#2045=CARTESIAN_POINT('',(236.,34.5,-183.958548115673));
#2046=VERTEX_POINT('',#2045);
#2047=EDGE_CURVE('E1314',#2046,#2038,#2044,.T.);
#2048=ORIENTED_EDGE('',*,*,#2047,.F.);
#2049=DIRECTION('',(0.,1.,0.));
#2050=VECTOR('',#2049,1.);
#2051=CARTESIAN_POINT('',(236.,34.5,-183.958548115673));
#2052=LINE('',#2051,#2050);
#2053=EDGE_CURVE('E1349',#2046,#1158,#2052,.T.);
#2054=ORIENTED_EDGE('',*,*,#2053,.T.);
#2055=EDGE_LOOP('',(#2032,#2040,#2048,#2054));
#2056=FACE_BOUND('',#2055,.T.);
#2057=ADVANCED_FACE('F2124',(#2056),#2031,.F.);
#2058=CARTESIAN_POINT('',(229.,34.5,-179.917096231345));
#2059=DIRECTION('',(0.499999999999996,0.,0.866025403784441));
#2060=DIRECTION('',(0.866025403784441,0.,-0.499999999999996));
#2061=AXIS2_PLACEMENT_3D('',#2058,#2059,#2060);
#2062=PLANE('',#2061);
#2063=ORIENTED_EDGE('',*,*,#1169,.T.);
#2064=ORIENTED_EDGE('',*,*,#2053,.F.);
#2065=DIRECTION('',(0.866025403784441,0.,-0.499999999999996));
#2066=VECTOR('',#2065,1.);
#2067=CARTESIAN_POINT('',(229.,34.5,-179.917096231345));
#2068=LINE('',#2067,#2066);
#2069=CARTESIAN_POINT('',(229.,34.5,-179.917096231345));
#2070=VERTEX_POINT('',#2069);
#2071=EDGE_CURVE('E1330',#2070,#2046,#2068,.T.);
#2072=ORIENTED_EDGE('',*,*,#2071,.F.);
#2073=DIRECTION('',(0.,1.,0.));
#2074=VECTOR('',#2073,1.);
#2075=CARTESIAN_POINT('',(229.,34.5,-179.917096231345));
#2076=LINE('',#2075,#2074);
#2077=EDGE_CURVE('E1352',#2070,#1168,#2076,.T.);
#2078=ORIENTED_EDGE('',*,*,#2077,.T.);
#2079=EDGE_LOOP('',(#2063,#2064,#2072,#2078));
#2080=FACE_BOUND('',#2079,.T.);
#2081=ADVANCED_FACE('F2129',(#2080),#2062,.F.);
#2082=CARTESIAN_POINT('',(222.,34.5,-183.958548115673));
#2083=DIRECTION('',(-0.500000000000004,0.,0.866025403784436));
#2084=DIRECTION('',(0.866025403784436,0.,0.500000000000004));
#2085=AXIS2_PLACEMENT_3D('',#2082,#2083,#2084);
#2086=PLANE('',#2085);
#2087=ORIENTED_EDGE('',*,*,#1177,.T.);
#2088=ORIENTED_EDGE('',*,*,#2077,.F.);
#2089=DIRECTION('',(0.866025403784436,0.,0.500000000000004));
#2090=VECTOR('',#2089,1.);
#2091=CARTESIAN_POINT('',(222.,34.5,-183.958548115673));
#2092=LINE('',#2091,#2090);
#2093=CARTESIAN_POINT('',(222.,34.5,-183.958548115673));
#2094=VERTEX_POINT('',#2093);
#2095=EDGE_CURVE('E1327',#2094,#2070,#2092,.T.);
#2096=ORIENTED_EDGE('',*,*,#2095,.F.);
#2097=DIRECTION('',(0.,1.,0.));
#2098=VECTOR('',#2097,1.);
#2099=CARTESIAN_POINT('',(222.,34.5,-183.958548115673));
#2100=LINE('',#2099,#2098);
#2101=EDGE_CURVE('E1354',#2094,#1176,#2100,.T.);
#2102=ORIENTED_EDGE('',*,*,#2101,.T.);
#2103=EDGE_LOOP('',(#2087,#2088,#2096,#2102));
#2104=FACE_BOUND('',#2103,.T.);
#2105=ADVANCED_FACE('F2139',(#2104),#2086,.F.);
#2106=CARTESIAN_POINT('',(222.,34.5,-192.041451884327));
#2107=DIRECTION('',(-1.,0.,0.));
#2108=DIRECTION('',(0.,0.,1.));
#2109=AXIS2_PLACEMENT_3D('',#2106,#2107,#2108);
#2110=PLANE('',#2109);
#2111=ORIENTED_EDGE('',*,*,#1185,.T.);
#2112=ORIENTED_EDGE('',*,*,#2101,.F.);
#2113=DIRECTION('',(0.,0.,1.));
#2114=VECTOR('',#2113,1.);
#2115=CARTESIAN_POINT('',(222.,34.5,-192.041451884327));
#2116=LINE('',#2115,#2114);
#2117=CARTESIAN_POINT('',(222.,34.5,-192.041451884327));
#2118=VERTEX_POINT('',#2117);
#2119=EDGE_CURVE('E1324',#2118,#2094,#2116,.T.);
#2120=ORIENTED_EDGE('',*,*,#2119,.F.);
#2121=DIRECTION('',(0.,1.,0.));
#2122=VECTOR('',#2121,1.);
#2123=CARTESIAN_POINT('',(222.,34.5,-192.041451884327));
#2124=LINE('',#2123,#2122);
#2125=EDGE_CURVE('E1356',#2118,#1184,#2124,.T.);
#2126=ORIENTED_EDGE('',*,*,#2125,.T.);
#2127=EDGE_LOOP('',(#2111,#2112,#2120,#2126));
#2128=FACE_BOUND('',#2127,.T.);
#2129=ADVANCED_FACE('F2149',(#2128),#2110,.F.);
#2130=CARTESIAN_POINT('',(229.,34.5,-196.082903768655));
#2131=DIRECTION('',(-0.499999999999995,0.,-0.866025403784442));
#2132=DIRECTION('',(-0.866025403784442,0.,0.499999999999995));
#2133=AXIS2_PLACEMENT_3D('',#2130,#2131,#2132);
#2134=PLANE('',#2133);
#2135=ORIENTED_EDGE('',*,*,#1193,.T.);
#2136=ORIENTED_EDGE('',*,*,#2125,.F.);
#2137=DIRECTION('',(-0.866025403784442,0.,0.499999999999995));
#2138=VECTOR('',#2137,1.);
#2139=CARTESIAN_POINT('',(229.,34.5,-196.082903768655));
#2140=LINE('',#2139,#2138);
#2141=CARTESIAN_POINT('',(229.,34.5,-196.082903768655));
#2142=VERTEX_POINT('',#2141);
#2143=EDGE_CURVE('E1321',#2142,#2118,#2140,.T.);
#2144=ORIENTED_EDGE('',*,*,#2143,.F.);
#2145=DIRECTION('',(0.,1.,0.));
#2146=VECTOR('',#2145,1.);
#2147=CARTESIAN_POINT('',(229.,34.5,-196.082903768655));
#2148=LINE('',#2147,#2146);
#2149=EDGE_CURVE('E1358',#2142,#1192,#2148,.T.);
#2150=ORIENTED_EDGE('',*,*,#2149,.T.);
#2151=EDGE_LOOP('',(#2135,#2136,#2144,#2150));
#2152=FACE_BOUND('',#2151,.T.);
#2153=ADVANCED_FACE('F2159',(#2152),#2134,.F.);
#2154=CARTESIAN_POINT('',(236.,34.5,-192.041451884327));
#2155=DIRECTION('',(0.500000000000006,0.,-0.866025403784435));
#2156=DIRECTION('',(-0.866025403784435,0.,-0.500000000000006));
#2157=AXIS2_PLACEMENT_3D('',#2154,#2155,#2156);
#2158=PLANE('',#2157);
#2159=ORIENTED_EDGE('',*,*,#1199,.T.);
#2160=ORIENTED_EDGE('',*,*,#2149,.F.);
#2161=DIRECTION('',(-0.866025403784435,0.,-0.500000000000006));
#2162=VECTOR('',#2161,1.);
#2163=CARTESIAN_POINT('',(236.,34.5,-192.041451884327));
#2164=LINE('',#2163,#2162);
#2165=EDGE_CURVE('E1317',#2038,#2142,#2164,.T.);
#2166=ORIENTED_EDGE('',*,*,#2165,.F.);
#2167=ORIENTED_EDGE('',*,*,#2039,.T.);
#2168=EDGE_LOOP('',(#2159,#2160,#2166,#2167));
#2169=FACE_BOUND('',#2168,.T.);
#2170=ADVANCED_FACE('F2169',(#2169),#2158,.F.);
#2171=CARTESIAN_POINT('',(0.,34.5,0.));
#2172=DIRECTION('',(0.,1.,0.));
#2173=DIRECTION('',(0.,0.,1.));
#2174=AXIS2_PLACEMENT_3D('',#2171,#2172,#2173);
#2175=PLANE('',#2174);
#2176=CARTESIAN_POINT('',(229.,34.5,-188.));
#2177=DIRECTION('',(0.,1.,0.));
#2178=DIRECTION('',(0.,0.,1.));
#2179=AXIS2_PLACEMENT_3D('',#2176,#2177,#2178);
#2180=CIRCLE('',#2179,3.99999999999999);
#2181=CARTESIAN_POINT('',(229.,34.5,-184.));
#2182=VERTEX_POINT('',#2181);
#2183=EDGE_CURVE('E1662',#2182,#2182,#2180,.T.);
#2184=ORIENTED_EDGE('',*,*,#2183,.F.);
#2185=EDGE_LOOP('',(#2184));
#2186=FACE_BOUND('',#2185,.T.);
#2187=ORIENTED_EDGE('',*,*,#2047,.T.);
#2188=ORIENTED_EDGE('',*,*,#2165,.T.);
#2189=ORIENTED_EDGE('',*,*,#2143,.T.);
#2190=ORIENTED_EDGE('',*,*,#2119,.T.);
#2191=ORIENTED_EDGE('',*,*,#2095,.T.);
#2192=ORIENTED_EDGE('',*,*,#2071,.T.);
#2193=EDGE_LOOP('',(#2187,#2188,#2189,#2190,#2191,#2192));
#2194=FACE_BOUND('',#2193,.T.);
#2195=ADVANCED_FACE('F2179',(#2186,#2194),#2175,.T.);
#2196=CARTESIAN_POINT('',(-220.,34.5,-183.958548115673));
#2197=DIRECTION('',(1.,0.,0.));
#2198=DIRECTION('',(0.,0.,-1.));
#2199=AXIS2_PLACEMENT_3D('',#2196,#2197,#2198);
#2200=PLANE('',#2199);
#2201=ORIENTED_EDGE('',*,*,#1111,.T.);
#2202=DIRECTION('',(0.,1.,0.));
#2203=VECTOR('',#2202,1.);
#2204=CARTESIAN_POINT('',(-220.,34.5,-192.041451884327));
#2205=LINE('',#2204,#2203);
#2206=CARTESIAN_POINT('',(-220.,34.5,-192.041451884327));
#2207=VERTEX_POINT('',#2206);
#2208=EDGE_CURVE('E1285',#2207,#1110,#2205,.T.);
#2209=ORIENTED_EDGE('',*,*,#2208,.F.);
#2210=DIRECTION('',(0.,0.,-1.));
#2211=VECTOR('',#2210,1.);
#2212=CARTESIAN_POINT('',(-220.,34.5,-183.958548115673));
#2213=LINE('',#2212,#2211);
#2214=CARTESIAN_POINT('',(-220.,34.5,-183.958548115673));
#2215=VERTEX_POINT('',#2214);
#2216=EDGE_CURVE('E1266',#2215,#2207,#2213,.T.);
#2217=ORIENTED_EDGE('',*,*,#2216,.F.);
#2218=DIRECTION('',(0.,1.,0.));
#2219=VECTOR('',#2218,1.);
#2220=CARTESIAN_POINT('',(-220.,34.5,-183.958548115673));
#2221=LINE('',#2220,#2219);
#2222=EDGE_CURVE('E1301',#2215,#1108,#2221,.T.);
#2223=ORIENTED_EDGE('',*,*,#2222,.T.);
#2224=EDGE_LOOP('',(#2201,#2209,#2217,#2223));
#2225=FACE_BOUND('',#2224,.T.);
#2226=ADVANCED_FACE('F2187',(#2225),#2200,.F.);
#2227=CARTESIAN_POINT('',(-227.,34.5,-179.917096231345));
#2228=DIRECTION('',(0.499999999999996,0.,0.866025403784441));
#2229=DIRECTION('',(0.866025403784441,0.,-0.499999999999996));
#2230=AXIS2_PLACEMENT_3D('',#2227,#2228,#2229);
#2231=PLANE('',#2230);
#2232=ORIENTED_EDGE('',*,*,#1119,.T.);
#2233=ORIENTED_EDGE('',*,*,#2222,.F.);
#2234=DIRECTION('',(0.866025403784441,0.,-0.499999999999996));
#2235=VECTOR('',#2234,1.);
#2236=CARTESIAN_POINT('',(-227.,34.5,-179.917096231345));
#2237=LINE('',#2236,#2235);
#2238=CARTESIAN_POINT('',(-227.,34.5,-179.917096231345));
#2239=VERTEX_POINT('',#2238);
#2240=EDGE_CURVE('E1282',#2239,#2215,#2237,.T.);
#2241=ORIENTED_EDGE('',*,*,#2240,.F.);
#2242=DIRECTION('',(0.,1.,0.));
#2243=VECTOR('',#2242,1.);
#2244=CARTESIAN_POINT('',(-227.,34.5,-179.917096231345));
#2245=LINE('',#2244,#2243);
#2246=EDGE_CURVE('E1304',#2239,#1118,#2245,.T.);
#2247=ORIENTED_EDGE('',*,*,#2246,.T.);
#2248=EDGE_LOOP('',(#2232,#2233,#2241,#2247));
#2249=FACE_BOUND('',#2248,.T.);
#2250=ADVANCED_FACE('F2192',(#2249),#2231,.F.);
#2251=CARTESIAN_POINT('',(-234.,34.5,-183.958548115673));
#2252=DIRECTION('',(-0.500000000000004,0.,0.866025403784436));
#2253=DIRECTION('',(0.866025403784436,0.,0.500000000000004));
#2254=AXIS2_PLACEMENT_3D('',#2251,#2252,#2253);
#2255=PLANE('',#2254);
#2256=ORIENTED_EDGE('',*,*,#1127,.T.);
#2257=ORIENTED_EDGE('',*,*,#2246,.F.);
#2258=DIRECTION('',(0.866025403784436,0.,0.500000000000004));
#2259=VECTOR('',#2258,1.);
#2260=CARTESIAN_POINT('',(-234.,34.5,-183.958548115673));
#2261=LINE('',#2260,#2259);
#2262=CARTESIAN_POINT('',(-234.,34.5,-183.958548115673));
#2263=VERTEX_POINT('',#2262);
#2264=EDGE_CURVE('E1279',#2263,#2239,#2261,.T.);
#2265=ORIENTED_EDGE('',*,*,#2264,.F.);
#2266=DIRECTION('',(0.,1.,0.));
#2267=VECTOR('',#2266,1.);
#2268=CARTESIAN_POINT('',(-234.,34.5,-183.958548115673));
#2269=LINE('',#2268,#2267);
#2270=EDGE_CURVE('E1306',#2263,#1126,#2269,.T.);
#2271=ORIENTED_EDGE('',*,*,#2270,.T.);
#2272=EDGE_LOOP('',(#2256,#2257,#2265,#2271));
#2273=FACE_BOUND('',#2272,.T.);
#2274=ADVANCED_FACE('F2202',(#2273),#2255,.F.);
#2275=CARTESIAN_POINT('',(-234.,34.5,-192.041451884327));
#2276=DIRECTION('',(-1.,0.,0.));
#2277=DIRECTION('',(0.,0.,1.));
#2278=AXIS2_PLACEMENT_3D('',#2275,#2276,#2277);
#2279=PLANE('',#2278);
#2280=ORIENTED_EDGE('',*,*,#1135,.T.);
#2281=ORIENTED_EDGE('',*,*,#2270,.F.);
#2282=DIRECTION('',(0.,0.,1.));
#2283=VECTOR('',#2282,1.);
#2284=CARTESIAN_POINT('',(-234.,34.5,-192.041451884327));
#2285=LINE('',#2284,#2283);
#2286=CARTESIAN_POINT('',(-234.,34.5,-192.041451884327));
#2287=VERTEX_POINT('',#2286);
#2288=EDGE_CURVE('E1276',#2287,#2263,#2285,.T.);
#2289=ORIENTED_EDGE('',*,*,#2288,.F.);
#2290=DIRECTION('',(0.,1.,0.));
#2291=VECTOR('',#2290,1.);
#2292=CARTESIAN_POINT('',(-234.,34.5,-192.041451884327));
#2293=LINE('',#2292,#2291);
#2294=EDGE_CURVE('E1308',#2287,#1134,#2293,.T.);
#2295=ORIENTED_EDGE('',*,*,#2294,.T.);
#2296=EDGE_LOOP('',(#2280,#2281,#2289,#2295));
#2297=FACE_BOUND('',#2296,.T.);
#2298=ADVANCED_FACE('F2212',(#2297),#2279,.F.);
#2299=CARTESIAN_POINT('',(-227.,34.5,-196.082903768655));
#2300=DIRECTION('',(-0.499999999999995,0.,-0.866025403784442));
#2301=DIRECTION('',(-0.866025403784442,0.,0.499999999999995));
#2302=AXIS2_PLACEMENT_3D('',#2299,#2300,#2301);
#2303=PLANE('',#2302);
#2304=ORIENTED_EDGE('',*,*,#1143,.T.);
#2305=ORIENTED_EDGE('',*,*,#2294,.F.);
#2306=DIRECTION('',(-0.866025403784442,0.,0.499999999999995));
#2307=VECTOR('',#2306,1.);
#2308=CARTESIAN_POINT('',(-227.,34.5,-196.082903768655));
#2309=LINE('',#2308,#2307);
#2310=CARTESIAN_POINT('',(-227.,34.5,-196.082903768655));
#2311=VERTEX_POINT('',#2310);
#2312=EDGE_CURVE('E1273',#2311,#2287,#2309,.T.);
#2313=ORIENTED_EDGE('',*,*,#2312,.F.);
#2314=DIRECTION('',(0.,1.,0.));
#2315=VECTOR('',#2314,1.);
#2316=CARTESIAN_POINT('',(-227.,34.5,-196.082903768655));
#2317=LINE('',#2316,#2315);
#2318=EDGE_CURVE('E1310',#2311,#1142,#2317,.T.);
#2319=ORIENTED_EDGE('',*,*,#2318,.T.);
#2320=EDGE_LOOP('',(#2304,#2305,#2313,#2319));
#2321=FACE_BOUND('',#2320,.T.);
#2322=ADVANCED_FACE('F2222',(#2321),#2303,.F.);
#2323=CARTESIAN_POINT('',(-220.,34.5,-192.041451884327));
#2324=DIRECTION('',(0.500000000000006,0.,-0.866025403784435));
#2325=DIRECTION('',(-0.866025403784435,0.,-0.500000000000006));
#2326=AXIS2_PLACEMENT_3D('',#2323,#2324,#2325);
#2327=PLANE('',#2326);
#2328=ORIENTED_EDGE('',*,*,#1149,.T.);
#2329=ORIENTED_EDGE('',*,*,#2318,.F.);
#2330=DIRECTION('',(-0.866025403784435,0.,-0.500000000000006));
#2331=VECTOR('',#2330,1.);
#2332=CARTESIAN_POINT('',(-220.,34.5,-192.041451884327));
#2333=LINE('',#2332,#2331);
#2334=EDGE_CURVE('E1269',#2207,#2311,#2333,.T.);
#2335=ORIENTED_EDGE('',*,*,#2334,.F.);
#2336=ORIENTED_EDGE('',*,*,#2208,.T.);
#2337=EDGE_LOOP('',(#2328,#2329,#2335,#2336));
#2338=FACE_BOUND('',#2337,.T.);
#2339=ADVANCED_FACE('F2232',(#2338),#2327,.F.);
#2340=CARTESIAN_POINT('',(0.,34.5,0.));
#2341=DIRECTION('',(0.,1.,0.));
#2342=DIRECTION('',(0.,0.,1.));
#2343=AXIS2_PLACEMENT_3D('',#2340,#2341,#2342);
#2344=PLANE('',#2343);
#2345=CARTESIAN_POINT('',(-227.,34.5,-188.));
#2346=DIRECTION('',(0.,1.,0.));
#2347=DIRECTION('',(0.,0.,1.));
#2348=AXIS2_PLACEMENT_3D('',#2345,#2346,#2347);
#2349=CIRCLE('',#2348,3.99999999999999);
#2350=CARTESIAN_POINT('',(-227.,34.5,-184.));
#2351=VERTEX_POINT('',#2350);
#2352=EDGE_CURVE('E1626',#2351,#2351,#2349,.T.);
#2353=ORIENTED_EDGE('',*,*,#2352,.F.);
#2354=EDGE_LOOP('',(#2353));
#2355=FACE_BOUND('',#2354,.T.);
#2356=ORIENTED_EDGE('',*,*,#2216,.T.);
#2357=ORIENTED_EDGE('',*,*,#2334,.T.);
#2358=ORIENTED_EDGE('',*,*,#2312,.T.);
#2359=ORIENTED_EDGE('',*,*,#2288,.T.);
#2360=ORIENTED_EDGE('',*,*,#2264,.T.);
#2361=ORIENTED_EDGE('',*,*,#2240,.T.);
#2362=EDGE_LOOP('',(#2356,#2357,#2358,#2359,#2360,#2361));
#2363=FACE_BOUND('',#2362,.T.);
#2364=ADVANCED_FACE('F2242',(#2355,#2363),#2344,.T.);
#2365=CARTESIAN_POINT('',(-293.,34.5,-183.958548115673));
#2366=DIRECTION('',(1.,0.,0.));
#2367=DIRECTION('',(0.,0.,-1.));
#2368=AXIS2_PLACEMENT_3D('',#2365,#2366,#2367);
#2369=PLANE('',#2368);
#2370=ORIENTED_EDGE('',*,*,#1061,.T.);
#2371=DIRECTION('',(0.,1.,0.));
#2372=VECTOR('',#2371,1.);
#2373=CARTESIAN_POINT('',(-293.,34.5,-192.041451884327));
#2374=LINE('',#2373,#2372);
#2375=CARTESIAN_POINT('',(-293.,34.5,-192.041451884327));
#2376=VERTEX_POINT('',#2375);
#2377=EDGE_CURVE('E1237',#2376,#1060,#2374,.T.);
#2378=ORIENTED_EDGE('',*,*,#2377,.F.);
#2379=DIRECTION('',(0.,0.,-1.));
#2380=VECTOR('',#2379,1.);
#2381=CARTESIAN_POINT('',(-293.,34.5,-183.958548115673));
#2382=LINE('',#2381,#2380);
#2383=CARTESIAN_POINT('',(-293.,34.5,-183.958548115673));
#2384=VERTEX_POINT('',#2383);
#2385=EDGE_CURVE('E1218',#2384,#2376,#2382,.T.);
#2386=ORIENTED_EDGE('',*,*,#2385,.F.);
#2387=DIRECTION('',(0.,1.,0.));
#2388=VECTOR('',#2387,1.);
#2389=CARTESIAN_POINT('',(-293.,34.5,-183.958548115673));
#2390=LINE('',#2389,#2388);
#2391=EDGE_CURVE('E1253',#2384,#1058,#2390,.T.);
#2392=ORIENTED_EDGE('',*,*,#2391,.T.);
#2393=EDGE_LOOP('',(#2370,#2378,#2386,#2392));
#2394=FACE_BOUND('',#2393,.T.);
#2395=ADVANCED_FACE('F2250',(#2394),#2369,.F.);
#2396=CARTESIAN_POINT('',(-300.,34.5,-179.917096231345));
#2397=DIRECTION('',(0.499999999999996,0.,0.866025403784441));
#2398=DIRECTION('',(0.866025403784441,0.,-0.499999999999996));
#2399=AXIS2_PLACEMENT_3D('',#2396,#2397,#2398);
#2400=PLANE('',#2399);
#2401=ORIENTED_EDGE('',*,*,#1069,.T.);
#2402=ORIENTED_EDGE('',*,*,#2391,.F.);
#2403=DIRECTION('',(0.866025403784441,0.,-0.499999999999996));
#2404=VECTOR('',#2403,1.);
#2405=CARTESIAN_POINT('',(-300.,34.5,-179.917096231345));
#2406=LINE('',#2405,#2404);
#2407=CARTESIAN_POINT('',(-300.,34.5,-179.917096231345));
#2408=VERTEX_POINT('',#2407);
#2409=EDGE_CURVE('E1234',#2408,#2384,#2406,.T.);
#2410=ORIENTED_EDGE('',*,*,#2409,.F.);
#2411=DIRECTION('',(0.,1.,0.));
#2412=VECTOR('',#2411,1.);
#2413=CARTESIAN_POINT('',(-300.,34.5,-179.917096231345));
#2414=LINE('',#2413,#2412);
#2415=EDGE_CURVE('E1256',#2408,#1068,#2414,.T.);
#2416=ORIENTED_EDGE('',*,*,#2415,.T.);
#2417=EDGE_LOOP('',(#2401,#2402,#2410,#2416));
#2418=FACE_BOUND('',#2417,.T.);
#2419=ADVANCED_FACE('F2255',(#2418),#2400,.F.);
#2420=CARTESIAN_POINT('',(-307.,34.5,-183.958548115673));
#2421=DIRECTION('',(-0.500000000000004,0.,0.866025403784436));
#2422=DIRECTION('',(0.866025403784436,0.,0.500000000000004));
#2423=AXIS2_PLACEMENT_3D('',#2420,#2421,#2422);
#2424=PLANE('',#2423);
#2425=ORIENTED_EDGE('',*,*,#1077,.T.);
#2426=ORIENTED_EDGE('',*,*,#2415,.F.);
#2427=DIRECTION('',(0.866025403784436,0.,0.500000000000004));
#2428=VECTOR('',#2427,1.);
#2429=CARTESIAN_POINT('',(-307.,34.5,-183.958548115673));
#2430=LINE('',#2429,#2428);
#2431=CARTESIAN_POINT('',(-307.,34.5,-183.958548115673));
#2432=VERTEX_POINT('',#2431);
#2433=EDGE_CURVE('E1231',#2432,#2408,#2430,.T.);
#2434=ORIENTED_EDGE('',*,*,#2433,.F.);
#2435=DIRECTION('',(0.,1.,0.));
#2436=VECTOR('',#2435,1.);
#2437=CARTESIAN_POINT('',(-307.,34.5,-183.958548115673));
#2438=LINE('',#2437,#2436);
#2439=EDGE_CURVE('E1258',#2432,#1076,#2438,.T.);
#2440=ORIENTED_EDGE('',*,*,#2439,.T.);
#2441=EDGE_LOOP('',(#2425,#2426,#2434,#2440));
#2442=FACE_BOUND('',#2441,.T.);
#2443=ADVANCED_FACE('F2265',(#2442),#2424,.F.);
#2444=CARTESIAN_POINT('',(-307.,34.5,-192.041451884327));
#2445=DIRECTION('',(-1.,0.,0.));
#2446=DIRECTION('',(0.,0.,1.));
#2447=AXIS2_PLACEMENT_3D('',#2444,#2445,#2446);
#2448=PLANE('',#2447);
#2449=ORIENTED_EDGE('',*,*,#1085,.T.);
#2450=ORIENTED_EDGE('',*,*,#2439,.F.);
#2451=DIRECTION('',(0.,0.,1.));
#2452=VECTOR('',#2451,1.);
#2453=CARTESIAN_POINT('',(-307.,34.5,-192.041451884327));
#2454=LINE('',#2453,#2452);
#2455=CARTESIAN_POINT('',(-307.,34.5,-192.041451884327));
#2456=VERTEX_POINT('',#2455);
#2457=EDGE_CURVE('E1228',#2456,#2432,#2454,.T.);
#2458=ORIENTED_EDGE('',*,*,#2457,.F.);
#2459=DIRECTION('',(0.,1.,0.));
#2460=VECTOR('',#2459,1.);
#2461=CARTESIAN_POINT('',(-307.,34.5,-192.041451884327));
#2462=LINE('',#2461,#2460);
#2463=EDGE_CURVE('E1260',#2456,#1084,#2462,.T.);
#2464=ORIENTED_EDGE('',*,*,#2463,.T.);
#2465=EDGE_LOOP('',(#2449,#2450,#2458,#2464));
#2466=FACE_BOUND('',#2465,.T.);
#2467=ADVANCED_FACE('F2275',(#2466),#2448,.F.);
#2468=CARTESIAN_POINT('',(-300.,34.5,-196.082903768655));
#2469=DIRECTION('',(-0.499999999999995,0.,-0.866025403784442));
#2470=DIRECTION('',(-0.866025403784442,0.,0.499999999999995));
#2471=AXIS2_PLACEMENT_3D('',#2468,#2469,#2470);
#2472=PLANE('',#2471);
#2473=ORIENTED_EDGE('',*,*,#1093,.T.);
#2474=ORIENTED_EDGE('',*,*,#2463,.F.);
#2475=DIRECTION('',(-0.866025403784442,0.,0.499999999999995));
#2476=VECTOR('',#2475,1.);
#2477=CARTESIAN_POINT('',(-300.,34.5,-196.082903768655));
#2478=LINE('',#2477,#2476);
#2479=CARTESIAN_POINT('',(-300.,34.5,-196.082903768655));
#2480=VERTEX_POINT('',#2479);
#2481=EDGE_CURVE('E1225',#2480,#2456,#2478,.T.);
#2482=ORIENTED_EDGE('',*,*,#2481,.F.);
#2483=DIRECTION('',(0.,1.,0.));
#2484=VECTOR('',#2483,1.);
#2485=CARTESIAN_POINT('',(-300.,34.5,-196.082903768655));
#2486=LINE('',#2485,#2484);
#2487=EDGE_CURVE('E1262',#2480,#1092,#2486,.T.);
#2488=ORIENTED_EDGE('',*,*,#2487,.T.);
#2489=EDGE_LOOP('',(#2473,#2474,#2482,#2488));
#2490=FACE_BOUND('',#2489,.T.);
#2491=ADVANCED_FACE('F2285',(#2490),#2472,.F.);
#2492=CARTESIAN_POINT('',(-293.,34.5,-192.041451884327));
#2493=DIRECTION('',(0.500000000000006,0.,-0.866025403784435));
#2494=DIRECTION('',(-0.866025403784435,0.,-0.500000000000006));
#2495=AXIS2_PLACEMENT_3D('',#2492,#2493,#2494);
#2496=PLANE('',#2495);
#2497=ORIENTED_EDGE('',*,*,#1099,.T.);
#2498=ORIENTED_EDGE('',*,*,#2487,.F.);
#2499=DIRECTION('',(-0.866025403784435,0.,-0.500000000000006));
#2500=VECTOR('',#2499,1.);
#2501=CARTESIAN_POINT('',(-293.,34.5,-192.041451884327));
#2502=LINE('',#2501,#2500);
#2503=EDGE_CURVE('E1221',#2376,#2480,#2502,.T.);
#2504=ORIENTED_EDGE('',*,*,#2503,.F.);
#2505=ORIENTED_EDGE('',*,*,#2377,.T.);
#2506=EDGE_LOOP('',(#2497,#2498,#2504,#2505));
#2507=FACE_BOUND('',#2506,.T.);
#2508=ADVANCED_FACE('F2295',(#2507),#2496,.F.);
#2509=CARTESIAN_POINT('',(0.,34.5,0.));
#2510=DIRECTION('',(0.,1.,0.));
#2511=DIRECTION('',(0.,0.,1.));
#2512=AXIS2_PLACEMENT_3D('',#2509,#2510,#2511);
#2513=PLANE('',#2512);
#2514=CARTESIAN_POINT('',(-300.,34.5,-188.));
#2515=DIRECTION('',(0.,1.,0.));
#2516=DIRECTION('',(0.,0.,1.));
#2517=AXIS2_PLACEMENT_3D('',#2514,#2515,#2516);
#2518=CIRCLE('',#2517,3.99999999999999);
#2519=CARTESIAN_POINT('',(-300.,34.5,-184.));
#2520=VERTEX_POINT('',#2519);
#2521=EDGE_CURVE('E768',#2520,#2520,#2518,.T.);
#2522=ORIENTED_EDGE('',*,*,#2521,.F.);
#2523=EDGE_LOOP('',(#2522));
#2524=FACE_BOUND('',#2523,.T.);
#2525=ORIENTED_EDGE('',*,*,#2385,.T.);
#2526=ORIENTED_EDGE('',*,*,#2503,.T.);
#2527=ORIENTED_EDGE('',*,*,#2481,.T.);
#2528=ORIENTED_EDGE('',*,*,#2457,.T.);
#2529=ORIENTED_EDGE('',*,*,#2433,.T.);
#2530=ORIENTED_EDGE('',*,*,#2409,.T.);
#2531=EDGE_LOOP('',(#2525,#2526,#2527,#2528,#2529,#2530));
#2532=FACE_BOUND('',#2531,.T.);
#2533=ADVANCED_FACE('F2305',(#2524,#2532),#2513,.T.);
#2534=CARTESIAN_POINT('',(-293.,34.5,-139.958548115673));
#2535=DIRECTION('',(1.,0.,0.));
#2536=DIRECTION('',(0.,0.,-1.));
#2537=AXIS2_PLACEMENT_3D('',#2534,#2535,#2536);
#2538=PLANE('',#2537);
#2539=ORIENTED_EDGE('',*,*,#1011,.T.);
#2540=DIRECTION('',(0.,1.,0.));
#2541=VECTOR('',#2540,1.);
#2542=CARTESIAN_POINT('',(-293.,34.5,-148.041451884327));
#2543=LINE('',#2542,#2541);
#2544=CARTESIAN_POINT('',(-293.,34.5,-148.041451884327));
#2545=VERTEX_POINT('',#2544);
#2546=EDGE_CURVE('E1189',#2545,#1010,#2543,.T.);
#2547=ORIENTED_EDGE('',*,*,#2546,.F.);
#2548=DIRECTION('',(0.,0.,-1.));
#2549=VECTOR('',#2548,1.);
#2550=CARTESIAN_POINT('',(-293.,34.5,-139.958548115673));
#2551=LINE('',#2550,#2549);
#2552=CARTESIAN_POINT('',(-293.,34.5,-139.958548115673));
#2553=VERTEX_POINT('',#2552);
#2554=EDGE_CURVE('E1170',#2553,#2545,#2551,.T.);
#2555=ORIENTED_EDGE('',*,*,#2554,.F.);
#2556=DIRECTION('',(0.,1.,0.));
#2557=VECTOR('',#2556,1.);
#2558=CARTESIAN_POINT('',(-293.,34.5,-139.958548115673));
#2559=LINE('',#2558,#2557);
#2560=EDGE_CURVE('E1205',#2553,#1008,#2559,.T.);
#2561=ORIENTED_EDGE('',*,*,#2560,.T.);
#2562=EDGE_LOOP('',(#2539,#2547,#2555,#2561));
#2563=FACE_BOUND('',#2562,.T.);
#2564=ADVANCED_FACE('F2313',(#2563),#2538,.F.);
#2565=CARTESIAN_POINT('',(-300.,34.5,-135.917096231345));
#2566=DIRECTION('',(0.499999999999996,0.,0.866025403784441));
#2567=DIRECTION('',(0.866025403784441,0.,-0.499999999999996));
#2568=AXIS2_PLACEMENT_3D('',#2565,#2566,#2567);
#2569=PLANE('',#2568);
#2570=ORIENTED_EDGE('',*,*,#1019,.T.);
#2571=ORIENTED_EDGE('',*,*,#2560,.F.);
#2572=DIRECTION('',(0.866025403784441,0.,-0.499999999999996));
#2573=VECTOR('',#2572,1.);
#2574=CARTESIAN_POINT('',(-300.,34.5,-135.917096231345));
#2575=LINE('',#2574,#2573);
#2576=CARTESIAN_POINT('',(-300.,34.5,-135.917096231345));
#2577=VERTEX_POINT('',#2576);
#2578=EDGE_CURVE('E1186',#2577,#2553,#2575,.T.);
#2579=ORIENTED_EDGE('',*,*,#2578,.F.);
#2580=DIRECTION('',(0.,1.,0.));
#2581=VECTOR('',#2580,1.);
#2582=CARTESIAN_POINT('',(-300.,34.5,-135.917096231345));
#2583=LINE('',#2582,#2581);
#2584=EDGE_CURVE('E1208',#2577,#1018,#2583,.T.);
#2585=ORIENTED_EDGE('',*,*,#2584,.T.);
#2586=EDGE_LOOP('',(#2570,#2571,#2579,#2585));
#2587=FACE_BOUND('',#2586,.T.);
#2588=ADVANCED_FACE('F2318',(#2587),#2569,.F.);
#2589=CARTESIAN_POINT('',(-307.,34.5,-139.958548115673));
#2590=DIRECTION('',(-0.500000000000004,0.,0.866025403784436));
#2591=DIRECTION('',(0.866025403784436,0.,0.500000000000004));
#2592=AXIS2_PLACEMENT_3D('',#2589,#2590,#2591);
#2593=PLANE('',#2592);
#2594=ORIENTED_EDGE('',*,*,#1027,.T.);
#2595=ORIENTED_EDGE('',*,*,#2584,.F.);
#2596=DIRECTION('',(0.866025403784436,0.,0.500000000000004));
#2597=VECTOR('',#2596,1.);
#2598=CARTESIAN_POINT('',(-307.,34.5,-139.958548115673));
#2599=LINE('',#2598,#2597);
#2600=CARTESIAN_POINT('',(-307.,34.5,-139.958548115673));
#2601=VERTEX_POINT('',#2600);
#2602=EDGE_CURVE('E1183',#2601,#2577,#2599,.T.);
#2603=ORIENTED_EDGE('',*,*,#2602,.F.);
#2604=DIRECTION('',(0.,1.,0.));
#2605=VECTOR('',#2604,1.);
#2606=CARTESIAN_POINT('',(-307.,34.5,-139.958548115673));
#2607=LINE('',#2606,#2605);
#2608=EDGE_CURVE('E1210',#2601,#1026,#2607,.T.);
#2609=ORIENTED_EDGE('',*,*,#2608,.T.);
#2610=EDGE_LOOP('',(#2594,#2595,#2603,#2609));
#2611=FACE_BOUND('',#2610,.T.);
#2612=ADVANCED_FACE('F2328',(#2611),#2593,.F.);
#2613=CARTESIAN_POINT('',(-307.,34.5,-148.041451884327));
#2614=DIRECTION('',(-1.,0.,0.));
#2615=DIRECTION('',(0.,0.,1.));
#2616=AXIS2_PLACEMENT_3D('',#2613,#2614,#2615);
#2617=PLANE('',#2616);
#2618=ORIENTED_EDGE('',*,*,#1035,.T.);
#2619=ORIENTED_EDGE('',*,*,#2608,.F.);
#2620=DIRECTION('',(0.,0.,1.));
#2621=VECTOR('',#2620,1.);
#2622=CARTESIAN_POINT('',(-307.,34.5,-148.041451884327));
#2623=LINE('',#2622,#2621);
#2624=CARTESIAN_POINT('',(-307.,34.5,-148.041451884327));
#2625=VERTEX_POINT('',#2624);
#2626=EDGE_CURVE('E1180',#2625,#2601,#2623,.T.);
#2627=ORIENTED_EDGE('',*,*,#2626,.F.);
#2628=DIRECTION('',(0.,1.,0.));
#2629=VECTOR('',#2628,1.);
#2630=CARTESIAN_POINT('',(-307.,34.5,-148.041451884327));
#2631=LINE('',#2630,#2629);
#2632=EDGE_CURVE('E1212',#2625,#1034,#2631,.T.);
#2633=ORIENTED_EDGE('',*,*,#2632,.T.);
#2634=EDGE_LOOP('',(#2618,#2619,#2627,#2633));
#2635=FACE_BOUND('',#2634,.T.);
#2636=ADVANCED_FACE('F2338',(#2635),#2617,.F.);
#2637=CARTESIAN_POINT('',(-300.,34.5,-152.082903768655));
#2638=DIRECTION('',(-0.499999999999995,0.,-0.866025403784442));
#2639=DIRECTION('',(-0.866025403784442,0.,0.499999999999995));
#2640=AXIS2_PLACEMENT_3D('',#2637,#2638,#2639);
#2641=PLANE('',#2640);
#2642=ORIENTED_EDGE('',*,*,#1043,.T.);
#2643=ORIENTED_EDGE('',*,*,#2632,.F.);
#2644=DIRECTION('',(-0.866025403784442,0.,0.499999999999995));
#2645=VECTOR('',#2644,1.);
#2646=CARTESIAN_POINT('',(-300.,34.5,-152.082903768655));
#2647=LINE('',#2646,#2645);
#2648=CARTESIAN_POINT('',(-300.,34.5,-152.082903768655));
#2649=VERTEX_POINT('',#2648);
#2650=EDGE_CURVE('E1177',#2649,#2625,#2647,.T.);
#2651=ORIENTED_EDGE('',*,*,#2650,.F.);
#2652=DIRECTION('',(0.,1.,0.));
#2653=VECTOR('',#2652,1.);
#2654=CARTESIAN_POINT('',(-300.,34.5,-152.082903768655));
#2655=LINE('',#2654,#2653);
#2656=EDGE_CURVE('E1214',#2649,#1042,#2655,.T.);
#2657=ORIENTED_EDGE('',*,*,#2656,.T.);
#2658=EDGE_LOOP('',(#2642,#2643,#2651,#2657));
#2659=FACE_BOUND('',#2658,.T.);
#2660=ADVANCED_FACE('F2348',(#2659),#2641,.F.);
#2661=CARTESIAN_POINT('',(-293.,34.5,-148.041451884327));
#2662=DIRECTION('',(0.500000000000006,0.,-0.866025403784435));
#2663=DIRECTION('',(-0.866025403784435,0.,-0.500000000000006));
#2664=AXIS2_PLACEMENT_3D('',#2661,#2662,#2663);
#2665=PLANE('',#2664);
#2666=ORIENTED_EDGE('',*,*,#1049,.T.);
#2667=ORIENTED_EDGE('',*,*,#2656,.F.);
#2668=DIRECTION('',(-0.866025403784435,0.,-0.500000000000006));
#2669=VECTOR('',#2668,1.);
#2670=CARTESIAN_POINT('',(-293.,34.5,-148.041451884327));
#2671=LINE('',#2670,#2669);
#2672=EDGE_CURVE('E1173',#2545,#2649,#2671,.T.);
#2673=ORIENTED_EDGE('',*,*,#2672,.F.);
#2674=ORIENTED_EDGE('',*,*,#2546,.T.);
#2675=EDGE_LOOP('',(#2666,#2667,#2673,#2674));
#2676=FACE_BOUND('',#2675,.T.);
#2677=ADVANCED_FACE('F2358',(#2676),#2665,.F.);
#2678=CARTESIAN_POINT('',(0.,34.5,0.));
#2679=DIRECTION('',(0.,1.,0.));
#2680=DIRECTION('',(0.,0.,1.));
#2681=AXIS2_PLACEMENT_3D('',#2678,#2679,#2680);
#2682=PLANE('',#2681);
#2683=CARTESIAN_POINT('',(-300.,34.5,-144.));
#2684=DIRECTION('',(0.,1.,0.));
#2685=DIRECTION('',(0.,0.,1.));
#2686=AXIS2_PLACEMENT_3D('',#2683,#2684,#2685);
#2687=CIRCLE('',#2686,3.99999999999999);
#2688=CARTESIAN_POINT('',(-300.,34.5,-140.));
#2689=VERTEX_POINT('',#2688);
#2690=EDGE_CURVE('E1618',#2689,#2689,#2687,.T.);
#2691=ORIENTED_EDGE('',*,*,#2690,.F.);
#2692=EDGE_LOOP('',(#2691));
#2693=FACE_BOUND('',#2692,.T.);
#2694=ORIENTED_EDGE('',*,*,#2554,.T.);
#2695=ORIENTED_EDGE('',*,*,#2672,.T.);
#2696=ORIENTED_EDGE('',*,*,#2650,.T.);
#2697=ORIENTED_EDGE('',*,*,#2626,.T.);
#2698=ORIENTED_EDGE('',*,*,#2602,.T.);
#2699=ORIENTED_EDGE('',*,*,#2578,.T.);
#2700=EDGE_LOOP('',(#2694,#2695,#2696,#2697,#2698,#2699));
#2701=FACE_BOUND('',#2700,.T.);
#2702=ADVANCED_FACE('F2368',(#2693,#2701),#2682,.T.);
#2703=CARTESIAN_POINT('',(-220.,34.5,-139.958548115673));
#2704=DIRECTION('',(1.,0.,0.));
#2705=DIRECTION('',(0.,0.,-1.));
#2706=AXIS2_PLACEMENT_3D('',#2703,#2704,#2705);
#2707=PLANE('',#2706);
#2708=ORIENTED_EDGE('',*,*,#961,.T.);
#2709=DIRECTION('',(0.,1.,0.));
#2710=VECTOR('',#2709,1.);
#2711=CARTESIAN_POINT('',(-220.,34.5,-148.041451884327));
#2712=LINE('',#2711,#2710);
#2713=CARTESIAN_POINT('',(-220.,34.5,-148.041451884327));
#2714=VERTEX_POINT('',#2713);
#2715=EDGE_CURVE('E1141',#2714,#960,#2712,.T.);
#2716=ORIENTED_EDGE('',*,*,#2715,.F.);
#2717=DIRECTION('',(0.,0.,-1.));
#2718=VECTOR('',#2717,1.);
#2719=CARTESIAN_POINT('',(-220.,34.5,-139.958548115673));
#2720=LINE('',#2719,#2718);
#2721=CARTESIAN_POINT('',(-220.,34.5,-139.958548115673));
#2722=VERTEX_POINT('',#2721);
#2723=EDGE_CURVE('E1122',#2722,#2714,#2720,.T.);
#2724=ORIENTED_EDGE('',*,*,#2723,.F.);
#2725=DIRECTION('',(0.,1.,0.));
#2726=VECTOR('',#2725,1.);
#2727=CARTESIAN_POINT('',(-220.,34.5,-139.958548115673));
#2728=LINE('',#2727,#2726);
#2729=EDGE_CURVE('E1157',#2722,#958,#2728,.T.);
#2730=ORIENTED_EDGE('',*,*,#2729,.T.);
#2731=EDGE_LOOP('',(#2708,#2716,#2724,#2730));
#2732=FACE_BOUND('',#2731,.T.);
#2733=ADVANCED_FACE('F2376',(#2732),#2707,.F.);
#2734=CARTESIAN_POINT('',(-227.,34.5,-135.917096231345));
#2735=DIRECTION('',(0.499999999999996,0.,0.866025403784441));
#2736=DIRECTION('',(0.866025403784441,0.,-0.499999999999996));
#2737=AXIS2_PLACEMENT_3D('',#2734,#2735,#2736);
#2738=PLANE('',#2737);
#2739=ORIENTED_EDGE('',*,*,#969,.T.);
#2740=ORIENTED_EDGE('',*,*,#2729,.F.);
#2741=DIRECTION('',(0.866025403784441,0.,-0.499999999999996));
#2742=VECTOR('',#2741,1.);
#2743=CARTESIAN_POINT('',(-227.,34.5,-135.917096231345));
#2744=LINE('',#2743,#2742);
#2745=CARTESIAN_POINT('',(-227.,34.5,-135.917096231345));
#2746=VERTEX_POINT('',#2745);
#2747=EDGE_CURVE('E1138',#2746,#2722,#2744,.T.);
#2748=ORIENTED_EDGE('',*,*,#2747,.F.);
#2749=DIRECTION('',(0.,1.,0.));
#2750=VECTOR('',#2749,1.);
#2751=CARTESIAN_POINT('',(-227.,34.5,-135.917096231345));
#2752=LINE('',#2751,#2750);
#2753=EDGE_CURVE('E1160',#2746,#968,#2752,.T.);
#2754=ORIENTED_EDGE('',*,*,#2753,.T.);
#2755=EDGE_LOOP('',(#2739,#2740,#2748,#2754));
#2756=FACE_BOUND('',#2755,.T.);
#2757=ADVANCED_FACE('F2381',(#2756),#2738,.F.);
#2758=CARTESIAN_POINT('',(-234.,34.5,-139.958548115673));
#2759=DIRECTION('',(-0.500000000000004,0.,0.866025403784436));
#2760=DIRECTION('',(0.866025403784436,0.,0.500000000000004));
#2761=AXIS2_PLACEMENT_3D('',#2758,#2759,#2760);
#2762=PLANE('',#2761);
#2763=ORIENTED_EDGE('',*,*,#977,.T.);
#2764=ORIENTED_EDGE('',*,*,#2753,.F.);
#2765=DIRECTION('',(0.866025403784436,0.,0.500000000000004));
#2766=VECTOR('',#2765,1.);
#2767=CARTESIAN_POINT('',(-234.,34.5,-139.958548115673));
#2768=LINE('',#2767,#2766);
#2769=CARTESIAN_POINT('',(-234.,34.5,-139.958548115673));
#2770=VERTEX_POINT('',#2769);
#2771=EDGE_CURVE('E1135',#2770,#2746,#2768,.T.);
#2772=ORIENTED_EDGE('',*,*,#2771,.F.);
#2773=DIRECTION('',(0.,1.,0.));
#2774=VECTOR('',#2773,1.);
#2775=CARTESIAN_POINT('',(-234.,34.5,-139.958548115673));
#2776=LINE('',#2775,#2774);
#2777=EDGE_CURVE('E1162',#2770,#976,#2776,.T.);
#2778=ORIENTED_EDGE('',*,*,#2777,.T.);
#2779=EDGE_LOOP('',(#2763,#2764,#2772,#2778));
#2780=FACE_BOUND('',#2779,.T.);
#2781=ADVANCED_FACE('F2391',(#2780),#2762,.F.);
#2782=CARTESIAN_POINT('',(-234.,34.5,-148.041451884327));
#2783=DIRECTION('',(-1.,0.,0.));
#2784=DIRECTION('',(0.,0.,1.));
#2785=AXIS2_PLACEMENT_3D('',#2782,#2783,#2784);
#2786=PLANE('',#2785);
#2787=ORIENTED_EDGE('',*,*,#985,.T.);
#2788=ORIENTED_EDGE('',*,*,#2777,.F.);
#2789=DIRECTION('',(0.,0.,1.));
#2790=VECTOR('',#2789,1.);
#2791=CARTESIAN_POINT('',(-234.,34.5,-148.041451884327));
#2792=LINE('',#2791,#2790);
#2793=CARTESIAN_POINT('',(-234.,34.5,-148.041451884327));
#2794=VERTEX_POINT('',#2793);
#2795=EDGE_CURVE('E1132',#2794,#2770,#2792,.T.);
#2796=ORIENTED_EDGE('',*,*,#2795,.F.);
#2797=DIRECTION('',(0.,1.,0.));
#2798=VECTOR('',#2797,1.);
#2799=CARTESIAN_POINT('',(-234.,34.5,-148.041451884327));
#2800=LINE('',#2799,#2798);
#2801=EDGE_CURVE('E1164',#2794,#984,#2800,.T.);
#2802=ORIENTED_EDGE('',*,*,#2801,.T.);
#2803=EDGE_LOOP('',(#2787,#2788,#2796,#2802));
#2804=FACE_BOUND('',#2803,.T.);
#2805=ADVANCED_FACE('F2401',(#2804),#2786,.F.);
#2806=CARTESIAN_POINT('',(-227.,34.5,-152.082903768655));
#2807=DIRECTION('',(-0.499999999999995,0.,-0.866025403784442));
#2808=DIRECTION('',(-0.866025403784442,0.,0.499999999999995));
#2809=AXIS2_PLACEMENT_3D('',#2806,#2807,#2808);
#2810=PLANE('',#2809);
#2811=ORIENTED_EDGE('',*,*,#993,.T.);
#2812=ORIENTED_EDGE('',*,*,#2801,.F.);
#2813=DIRECTION('',(-0.866025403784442,0.,0.499999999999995));
#2814=VECTOR('',#2813,1.);
#2815=CARTESIAN_POINT('',(-227.,34.5,-152.082903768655));
#2816=LINE('',#2815,#2814);
#2817=CARTESIAN_POINT('',(-227.,34.5,-152.082903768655));
#2818=VERTEX_POINT('',#2817);
#2819=EDGE_CURVE('E1129',#2818,#2794,#2816,.T.);
#2820=ORIENTED_EDGE('',*,*,#2819,.F.);
#2821=DIRECTION('',(0.,1.,0.));
#2822=VECTOR('',#2821,1.);
#2823=CARTESIAN_POINT('',(-227.,34.5,-152.082903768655));
#2824=LINE('',#2823,#2822);
#2825=EDGE_CURVE('E1166',#2818,#992,#2824,.T.);
#2826=ORIENTED_EDGE('',*,*,#2825,.T.);
#2827=EDGE_LOOP('',(#2811,#2812,#2820,#2826));
#2828=FACE_BOUND('',#2827,.T.);
#2829=ADVANCED_FACE('F2411',(#2828),#2810,.F.);
#2830=CARTESIAN_POINT('',(-220.,34.5,-148.041451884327));
#2831=DIRECTION('',(0.500000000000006,0.,-0.866025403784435));
#2832=DIRECTION('',(-0.866025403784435,0.,-0.500000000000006));
#2833=AXIS2_PLACEMENT_3D('',#2830,#2831,#2832);
#2834=PLANE('',#2833);
#2835=ORIENTED_EDGE('',*,*,#999,.T.);
#2836=ORIENTED_EDGE('',*,*,#2825,.F.);
#2837=DIRECTION('',(-0.866025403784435,0.,-0.500000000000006));
#2838=VECTOR('',#2837,1.);
#2839=CARTESIAN_POINT('',(-220.,34.5,-148.041451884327));
#2840=LINE('',#2839,#2838);
#2841=EDGE_CURVE('E1125',#2714,#2818,#2840,.T.);
#2842=ORIENTED_EDGE('',*,*,#2841,.F.);
#2843=ORIENTED_EDGE('',*,*,#2715,.T.);
#2844=EDGE_LOOP('',(#2835,#2836,#2842,#2843));
#2845=FACE_BOUND('',#2844,.T.);
#2846=ADVANCED_FACE('F2421',(#2845),#2834,.F.);
#2847=CARTESIAN_POINT('',(0.,34.5,0.));
#2848=DIRECTION('',(0.,1.,0.));
#2849=DIRECTION('',(0.,0.,1.));
#2850=AXIS2_PLACEMENT_3D('',#2847,#2848,#2849);
#2851=PLANE('',#2850);
#2852=CARTESIAN_POINT('',(-227.,34.5,-144.));
#2853=DIRECTION('',(0.,1.,0.));
#2854=DIRECTION('',(0.,0.,1.));
#2855=AXIS2_PLACEMENT_3D('',#2852,#2853,#2854);
#2856=CIRCLE('',#2855,3.99999999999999);
#2857=CARTESIAN_POINT('',(-227.,34.5,-140.));
#2858=VERTEX_POINT('',#2857);
#2859=EDGE_CURVE('E1622',#2858,#2858,#2856,.T.);
#2860=ORIENTED_EDGE('',*,*,#2859,.F.);
#2861=EDGE_LOOP('',(#2860));
#2862=FACE_BOUND('',#2861,.T.);
#2863=ORIENTED_EDGE('',*,*,#2723,.T.);
#2864=ORIENTED_EDGE('',*,*,#2841,.T.);
#2865=ORIENTED_EDGE('',*,*,#2819,.T.);
#2866=ORIENTED_EDGE('',*,*,#2795,.T.);
#2867=ORIENTED_EDGE('',*,*,#2771,.T.);
#2868=ORIENTED_EDGE('',*,*,#2747,.T.);
#2869=EDGE_LOOP('',(#2863,#2864,#2865,#2866,#2867,#2868));
#2870=FACE_BOUND('',#2869,.T.);
#2871=ADVANCED_FACE('F2431',(#2862,#2870),#2851,.T.);
#2872=CARTESIAN_POINT('',(-293.,34.5,148.041451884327));
#2873=DIRECTION('',(1.,0.,0.));
#2874=DIRECTION('',(0.,0.,-1.));
#2875=AXIS2_PLACEMENT_3D('',#2872,#2873,#2874);
#2876=PLANE('',#2875);
#2877=ORIENTED_EDGE('',*,*,#911,.T.);
#2878=DIRECTION('',(0.,1.,0.));
#2879=VECTOR('',#2878,1.);
#2880=CARTESIAN_POINT('',(-293.,34.5,139.958548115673));
#2881=LINE('',#2880,#2879);
#2882=CARTESIAN_POINT('',(-293.,34.5,139.958548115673));
#2883=VERTEX_POINT('',#2882);
#2884=EDGE_CURVE('E1093',#2883,#910,#2881,.T.);
#2885=ORIENTED_EDGE('',*,*,#2884,.F.);
#2886=DIRECTION('',(0.,0.,-1.));
#2887=VECTOR('',#2886,1.);
#2888=CARTESIAN_POINT('',(-293.,34.5,148.041451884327));
#2889=LINE('',#2888,#2887);
#2890=CARTESIAN_POINT('',(-293.,34.5,148.041451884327));
#2891=VERTEX_POINT('',#2890);
#2892=EDGE_CURVE('E1074',#2891,#2883,#2889,.T.);
#2893=ORIENTED_EDGE('',*,*,#2892,.F.);
#2894=DIRECTION('',(0.,1.,0.));
#2895=VECTOR('',#2894,1.);
#2896=CARTESIAN_POINT('',(-293.,34.5,148.041451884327));
#2897=LINE('',#2896,#2895);
#2898=EDGE_CURVE('E1109',#2891,#908,#2897,.T.);
#2899=ORIENTED_EDGE('',*,*,#2898,.T.);
#2900=EDGE_LOOP('',(#2877,#2885,#2893,#2899));
#2901=FACE_BOUND('',#2900,.T.);
#2902=ADVANCED_FACE('F2439',(#2901),#2876,.F.);
#2903=CARTESIAN_POINT('',(-300.,34.5,152.082903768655));
#2904=DIRECTION('',(0.499999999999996,0.,0.866025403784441));
#2905=DIRECTION('',(0.866025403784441,0.,-0.499999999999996));
#2906=AXIS2_PLACEMENT_3D('',#2903,#2904,#2905);
#2907=PLANE('',#2906);
#2908=ORIENTED_EDGE('',*,*,#919,.T.);
#2909=ORIENTED_EDGE('',*,*,#2898,.F.);
#2910=DIRECTION('',(0.866025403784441,0.,-0.499999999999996));
#2911=VECTOR('',#2910,1.);
#2912=CARTESIAN_POINT('',(-300.,34.5,152.082903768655));
#2913=LINE('',#2912,#2911);
#2914=CARTESIAN_POINT('',(-300.,34.5,152.082903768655));
#2915=VERTEX_POINT('',#2914);
#2916=EDGE_CURVE('E1090',#2915,#2891,#2913,.T.);
#2917=ORIENTED_EDGE('',*,*,#2916,.F.);
#2918=DIRECTION('',(0.,1.,0.));
#2919=VECTOR('',#2918,1.);
#2920=CARTESIAN_POINT('',(-300.,34.5,152.082903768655));
#2921=LINE('',#2920,#2919);
#2922=EDGE_CURVE('E1112',#2915,#918,#2921,.T.);
#2923=ORIENTED_EDGE('',*,*,#2922,.T.);
#2924=EDGE_LOOP('',(#2908,#2909,#2917,#2923));
#2925=FACE_BOUND('',#2924,.T.);
#2926=ADVANCED_FACE('F2444',(#2925),#2907,.F.);
#2927=CARTESIAN_POINT('',(-307.,34.5,148.041451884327));
#2928=DIRECTION('',(-0.500000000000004,0.,0.866025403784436));
#2929=DIRECTION('',(0.866025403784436,0.,0.500000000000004));
#2930=AXIS2_PLACEMENT_3D('',#2927,#2928,#2929);
#2931=PLANE('',#2930);
#2932=ORIENTED_EDGE('',*,*,#927,.T.);
#2933=ORIENTED_EDGE('',*,*,#2922,.F.);
#2934=DIRECTION('',(0.866025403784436,0.,0.500000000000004));
#2935=VECTOR('',#2934,1.);
#2936=CARTESIAN_POINT('',(-307.,34.5,148.041451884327));
#2937=LINE('',#2936,#2935);
#2938=CARTESIAN_POINT('',(-307.,34.5,148.041451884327));
#2939=VERTEX_POINT('',#2938);
#2940=EDGE_CURVE('E1087',#2939,#2915,#2937,.T.);
#2941=ORIENTED_EDGE('',*,*,#2940,.F.);
#2942=DIRECTION('',(0.,1.,0.));
#2943=VECTOR('',#2942,1.);
#2944=CARTESIAN_POINT('',(-307.,34.5,148.041451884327));
#2945=LINE('',#2944,#2943);
#2946=EDGE_CURVE('E1114',#2939,#926,#2945,.T.);
#2947=ORIENTED_EDGE('',*,*,#2946,.T.);
#2948=EDGE_LOOP('',(#2932,#2933,#2941,#2947));
#2949=FACE_BOUND('',#2948,.T.);
#2950=ADVANCED_FACE('F2454',(#2949),#2931,.F.);
#2951=CARTESIAN_POINT('',(-307.,34.5,139.958548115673));
#2952=DIRECTION('',(-1.,0.,0.));
#2953=DIRECTION('',(0.,0.,1.));
#2954=AXIS2_PLACEMENT_3D('',#2951,#2952,#2953);
#2955=PLANE('',#2954);
#2956=ORIENTED_EDGE('',*,*,#935,.T.);
#2957=ORIENTED_EDGE('',*,*,#2946,.F.);
#2958=DIRECTION('',(0.,0.,1.));
#2959=VECTOR('',#2958,1.);
#2960=CARTESIAN_POINT('',(-307.,34.5,139.958548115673));
#2961=LINE('',#2960,#2959);
#2962=CARTESIAN_POINT('',(-307.,34.5,139.958548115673));
#2963=VERTEX_POINT('',#2962);
#2964=EDGE_CURVE('E1084',#2963,#2939,#2961,.T.);
#2965=ORIENTED_EDGE('',*,*,#2964,.F.);
#2966=DIRECTION('',(0.,1.,0.));
#2967=VECTOR('',#2966,1.);
#2968=CARTESIAN_POINT('',(-307.,34.5,139.958548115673));
#2969=LINE('',#2968,#2967);
#2970=EDGE_CURVE('E1116',#2963,#934,#2969,.T.);
#2971=ORIENTED_EDGE('',*,*,#2970,.T.);
#2972=EDGE_LOOP('',(#2956,#2957,#2965,#2971));
#2973=FACE_BOUND('',#2972,.T.);
#2974=ADVANCED_FACE('F2464',(#2973),#2955,.F.);
#2975=CARTESIAN_POINT('',(-300.,34.5,135.917096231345));
#2976=DIRECTION('',(-0.499999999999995,0.,-0.866025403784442));
#2977=DIRECTION('',(-0.866025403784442,0.,0.499999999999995));
#2978=AXIS2_PLACEMENT_3D('',#2975,#2976,#2977);
#2979=PLANE('',#2978);
#2980=ORIENTED_EDGE('',*,*,#943,.T.);
#2981=ORIENTED_EDGE('',*,*,#2970,.F.);
#2982=DIRECTION('',(-0.866025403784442,0.,0.499999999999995));
#2983=VECTOR('',#2982,1.);
#2984=CARTESIAN_POINT('',(-300.,34.5,135.917096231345));
#2985=LINE('',#2984,#2983);
#2986=CARTESIAN_POINT('',(-300.,34.5,135.917096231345));
#2987=VERTEX_POINT('',#2986);
#2988=EDGE_CURVE('E1081',#2987,#2963,#2985,.T.);
#2989=ORIENTED_EDGE('',*,*,#2988,.F.);
#2990=DIRECTION('',(0.,1.,0.));
#2991=VECTOR('',#2990,1.);
#2992=CARTESIAN_POINT('',(-300.,34.5,135.917096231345));
#2993=LINE('',#2992,#2991);
#2994=EDGE_CURVE('E1118',#2987,#942,#2993,.T.);
#2995=ORIENTED_EDGE('',*,*,#2994,.T.);
#2996=EDGE_LOOP('',(#2980,#2981,#2989,#2995));
#2997=FACE_BOUND('',#2996,.T.);
#2998=ADVANCED_FACE('F2474',(#2997),#2979,.F.);
#2999=CARTESIAN_POINT('',(-293.,34.5,139.958548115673));
#3000=DIRECTION('',(0.500000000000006,0.,-0.866025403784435));
#3001=DIRECTION('',(-0.866025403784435,0.,-0.500000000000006));
#3002=AXIS2_PLACEMENT_3D('',#2999,#3000,#3001);
#3003=PLANE('',#3002);
#3004=ORIENTED_EDGE('',*,*,#949,.T.);
#3005=ORIENTED_EDGE('',*,*,#2994,.F.);
#3006=DIRECTION('',(-0.866025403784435,0.,-0.500000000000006));
#3007=VECTOR('',#3006,1.);
#3008=CARTESIAN_POINT('',(-293.,34.5,139.958548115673));
#3009=LINE('',#3008,#3007);
#3010=EDGE_CURVE('E1077',#2883,#2987,#3009,.T.);
#3011=ORIENTED_EDGE('',*,*,#3010,.F.);
#3012=ORIENTED_EDGE('',*,*,#2884,.T.);
#3013=EDGE_LOOP('',(#3004,#3005,#3011,#3012));
#3014=FACE_BOUND('',#3013,.T.);
#3015=ADVANCED_FACE('F2484',(#3014),#3003,.F.);
#3016=CARTESIAN_POINT('',(0.,34.5,0.));
#3017=DIRECTION('',(0.,1.,0.));
#3018=DIRECTION('',(0.,0.,1.));
#3019=AXIS2_PLACEMENT_3D('',#3016,#3017,#3018);
#3020=PLANE('',#3019);
#3021=CARTESIAN_POINT('',(-300.,34.5,144.));
#3022=DIRECTION('',(0.,1.,0.));
#3023=DIRECTION('',(0.,0.,1.));
#3024=AXIS2_PLACEMENT_3D('',#3021,#3022,#3023);
#3025=CIRCLE('',#3024,3.99999999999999);
#3026=CARTESIAN_POINT('',(-300.,34.5,148.));
#3027=VERTEX_POINT('',#3026);
#3028=EDGE_CURVE('E1630',#3027,#3027,#3025,.T.);
#3029=ORIENTED_EDGE('',*,*,#3028,.F.);
#3030=EDGE_LOOP('',(#3029));
#3031=FACE_BOUND('',#3030,.T.);
#3032=ORIENTED_EDGE('',*,*,#2892,.T.);
#3033=ORIENTED_EDGE('',*,*,#3010,.T.);
#3034=ORIENTED_EDGE('',*,*,#2988,.T.);
#3035=ORIENTED_EDGE('',*,*,#2964,.T.);
#3036=ORIENTED_EDGE('',*,*,#2940,.T.);
#3037=ORIENTED_EDGE('',*,*,#2916,.T.);
#3038=EDGE_LOOP('',(#3032,#3033,#3034,#3035,#3036,#3037));
#3039=FACE_BOUND('',#3038,.T.);
#3040=ADVANCED_FACE('F2494',(#3031,#3039),#3020,.T.);
#3041=CARTESIAN_POINT('',(-220.,34.5,148.041451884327));
#3042=DIRECTION('',(1.,0.,0.));
#3043=DIRECTION('',(0.,0.,-1.));
#3044=AXIS2_PLACEMENT_3D('',#3041,#3042,#3043);
#3045=PLANE('',#3044);
#3046=ORIENTED_EDGE('',*,*,#861,.T.);
#3047=DIRECTION('',(0.,1.,0.));
#3048=VECTOR('',#3047,1.);
#3049=CARTESIAN_POINT('',(-220.,34.5,139.958548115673));
#3050=LINE('',#3049,#3048);
#3051=CARTESIAN_POINT('',(-220.,34.5,139.958548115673));
#3052=VERTEX_POINT('',#3051);
#3053=EDGE_CURVE('E1045',#3052,#860,#3050,.T.);
#3054=ORIENTED_EDGE('',*,*,#3053,.F.);
#3055=DIRECTION('',(0.,0.,-1.));
#3056=VECTOR('',#3055,1.);
#3057=CARTESIAN_POINT('',(-220.,34.5,148.041451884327));
#3058=LINE('',#3057,#3056);
#3059=CARTESIAN_POINT('',(-220.,34.5,148.041451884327));
#3060=VERTEX_POINT('',#3059);
#3061=EDGE_CURVE('E1026',#3060,#3052,#3058,.T.);
#3062=ORIENTED_EDGE('',*,*,#3061,.F.);
#3063=DIRECTION('',(0.,1.,0.));
#3064=VECTOR('',#3063,1.);
#3065=CARTESIAN_POINT('',(-220.,34.5,148.041451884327));
#3066=LINE('',#3065,#3064);
#3067=EDGE_CURVE('E1061',#3060,#858,#3066,.T.);
#3068=ORIENTED_EDGE('',*,*,#3067,.T.);
#3069=EDGE_LOOP('',(#3046,#3054,#3062,#3068));
#3070=FACE_BOUND('',#3069,.T.);
#3071=ADVANCED_FACE('F2502',(#3070),#3045,.F.);
#3072=CARTESIAN_POINT('',(-227.,34.5,152.082903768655));
#3073=DIRECTION('',(0.499999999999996,0.,0.866025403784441));
#3074=DIRECTION('',(0.866025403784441,0.,-0.499999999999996));
#3075=AXIS2_PLACEMENT_3D('',#3072,#3073,#3074);
#3076=PLANE('',#3075);
#3077=ORIENTED_EDGE('',*,*,#869,.T.);
#3078=ORIENTED_EDGE('',*,*,#3067,.F.);
#3079=DIRECTION('',(0.866025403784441,0.,-0.499999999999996));
#3080=VECTOR('',#3079,1.);
#3081=CARTESIAN_POINT('',(-227.,34.5,152.082903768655));
#3082=LINE('',#3081,#3080);
#3083=CARTESIAN_POINT('',(-227.,34.5,152.082903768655));
#3084=VERTEX_POINT('',#3083);
#3085=EDGE_CURVE('E1042',#3084,#3060,#3082,.T.);
#3086=ORIENTED_EDGE('',*,*,#3085,.F.);
#3087=DIRECTION('',(0.,1.,0.));
#3088=VECTOR('',#3087,1.);
#3089=CARTESIAN_POINT('',(-227.,34.5,152.082903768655));
#3090=LINE('',#3089,#3088);
#3091=EDGE_CURVE('E1064',#3084,#868,#3090,.T.);
#3092=ORIENTED_EDGE('',*,*,#3091,.T.);
#3093=EDGE_LOOP('',(#3077,#3078,#3086,#3092));
#3094=FACE_BOUND('',#3093,.T.);
#3095=ADVANCED_FACE('F2507',(#3094),#3076,.F.);
#3096=CARTESIAN_POINT('',(-234.,34.5,148.041451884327));
#3097=DIRECTION('',(-0.500000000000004,0.,0.866025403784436));
#3098=DIRECTION('',(0.866025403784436,0.,0.500000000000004));
#3099=AXIS2_PLACEMENT_3D('',#3096,#3097,#3098);
#3100=PLANE('',#3099);
#3101=ORIENTED_EDGE('',*,*,#877,.T.);
#3102=ORIENTED_EDGE('',*,*,#3091,.F.);
#3103=DIRECTION('',(0.866025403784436,0.,0.500000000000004));
#3104=VECTOR('',#3103,1.);
#3105=CARTESIAN_POINT('',(-234.,34.5,148.041451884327));
#3106=LINE('',#3105,#3104);
#3107=CARTESIAN_POINT('',(-234.,34.5,148.041451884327));
#3108=VERTEX_POINT('',#3107);
#3109=EDGE_CURVE('E1039',#3108,#3084,#3106,.T.);
#3110=ORIENTED_EDGE('',*,*,#3109,.F.);
#3111=DIRECTION('',(0.,1.,0.));
#3112=VECTOR('',#3111,1.);
#3113=CARTESIAN_POINT('',(-234.,34.5,148.041451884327));
#3114=LINE('',#3113,#3112);
#3115=EDGE_CURVE('E1066',#3108,#876,#3114,.T.);
#3116=ORIENTED_EDGE('',*,*,#3115,.T.);
#3117=EDGE_LOOP('',(#3101,#3102,#3110,#3116));
#3118=FACE_BOUND('',#3117,.T.);
#3119=ADVANCED_FACE('F2517',(#3118),#3100,.F.);
#3120=CARTESIAN_POINT('',(-234.,34.5,139.958548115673));
#3121=DIRECTION('',(-1.,0.,0.));
#3122=DIRECTION('',(0.,0.,1.));
#3123=AXIS2_PLACEMENT_3D('',#3120,#3121,#3122);
#3124=PLANE('',#3123);
#3125=ORIENTED_EDGE('',*,*,#885,.T.);
#3126=ORIENTED_EDGE('',*,*,#3115,.F.);
#3127=DIRECTION('',(0.,0.,1.));
#3128=VECTOR('',#3127,1.);
#3129=CARTESIAN_POINT('',(-234.,34.5,139.958548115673));
#3130=LINE('',#3129,#3128);
#3131=CARTESIAN_POINT('',(-234.,34.5,139.958548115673));
#3132=VERTEX_POINT('',#3131);
#3133=EDGE_CURVE('E1036',#3132,#3108,#3130,.T.);
#3134=ORIENTED_EDGE('',*,*,#3133,.F.);
#3135=DIRECTION('',(0.,1.,0.));
#3136=VECTOR('',#3135,1.);
#3137=CARTESIAN_POINT('',(-234.,34.5,139.958548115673));
#3138=LINE('',#3137,#3136);
#3139=EDGE_CURVE('E1068',#3132,#884,#3138,.T.);
#3140=ORIENTED_EDGE('',*,*,#3139,.T.);
#3141=EDGE_LOOP('',(#3125,#3126,#3134,#3140));
#3142=FACE_BOUND('',#3141,.T.);
#3143=ADVANCED_FACE('F2527',(#3142),#3124,.F.);
#3144=CARTESIAN_POINT('',(-227.,34.5,135.917096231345));
#3145=DIRECTION('',(-0.499999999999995,0.,-0.866025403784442));
#3146=DIRECTION('',(-0.866025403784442,0.,0.499999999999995));
#3147=AXIS2_PLACEMENT_3D('',#3144,#3145,#3146);
#3148=PLANE('',#3147);
#3149=ORIENTED_EDGE('',*,*,#893,.T.);
#3150=ORIENTED_EDGE('',*,*,#3139,.F.);
#3151=DIRECTION('',(-0.866025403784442,0.,0.499999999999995));
#3152=VECTOR('',#3151,1.);
#3153=CARTESIAN_POINT('',(-227.,34.5,135.917096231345));
#3154=LINE('',#3153,#3152);
#3155=CARTESIAN_POINT('',(-227.,34.5,135.917096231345));
#3156=VERTEX_POINT('',#3155);
#3157=EDGE_CURVE('E1033',#3156,#3132,#3154,.T.);
#3158=ORIENTED_EDGE('',*,*,#3157,.F.);
#3159=DIRECTION('',(0.,1.,0.));
#3160=VECTOR('',#3159,1.);
#3161=CARTESIAN_POINT('',(-227.,34.5,135.917096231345));
#3162=LINE('',#3161,#3160);
#3163=EDGE_CURVE('E1070',#3156,#892,#3162,.T.);
#3164=ORIENTED_EDGE('',*,*,#3163,.T.);
#3165=EDGE_LOOP('',(#3149,#3150,#3158,#3164));
#3166=FACE_BOUND('',#3165,.T.);
#3167=ADVANCED_FACE('F2537',(#3166),#3148,.F.);
#3168=CARTESIAN_POINT('',(-220.,34.5,139.958548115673));
#3169=DIRECTION('',(0.500000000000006,0.,-0.866025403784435));
#3170=DIRECTION('',(-0.866025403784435,0.,-0.500000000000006));
#3171=AXIS2_PLACEMENT_3D('',#3168,#3169,#3170);
#3172=PLANE('',#3171);
#3173=ORIENTED_EDGE('',*,*,#899,.T.);
#3174=ORIENTED_EDGE('',*,*,#3163,.F.);
#3175=DIRECTION('',(-0.866025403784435,0.,-0.500000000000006));
#3176=VECTOR('',#3175,1.);
#3177=CARTESIAN_POINT('',(-220.,34.5,139.958548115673));
#3178=LINE('',#3177,#3176);
#3179=EDGE_CURVE('E1029',#3052,#3156,#3178,.T.);
#3180=ORIENTED_EDGE('',*,*,#3179,.F.);
#3181=ORIENTED_EDGE('',*,*,#3053,.T.);
#3182=EDGE_LOOP('',(#3173,#3174,#3180,#3181));
#3183=FACE_BOUND('',#3182,.T.);
#3184=ADVANCED_FACE('F2547',(#3183),#3172,.F.);
#3185=CARTESIAN_POINT('',(0.,34.5,0.));
#3186=DIRECTION('',(0.,1.,0.));
#3187=DIRECTION('',(0.,0.,1.));
#3188=AXIS2_PLACEMENT_3D('',#3185,#3186,#3187);
#3189=PLANE('',#3188);
#3190=CARTESIAN_POINT('',(-227.,34.5,144.));
#3191=DIRECTION('',(0.,1.,0.));
#3192=DIRECTION('',(0.,0.,1.));
#3193=AXIS2_PLACEMENT_3D('',#3190,#3191,#3192);
#3194=CIRCLE('',#3193,3.99999999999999);
#3195=CARTESIAN_POINT('',(-227.,34.5,148.));
#3196=VERTEX_POINT('',#3195);
#3197=EDGE_CURVE('E1642',#3196,#3196,#3194,.T.);
#3198=ORIENTED_EDGE('',*,*,#3197,.F.);
#3199=EDGE_LOOP('',(#3198));
#3200=FACE_BOUND('',#3199,.T.);
#3201=ORIENTED_EDGE('',*,*,#3061,.T.);
#3202=ORIENTED_EDGE('',*,*,#3179,.T.);
#3203=ORIENTED_EDGE('',*,*,#3157,.T.);
#3204=ORIENTED_EDGE('',*,*,#3133,.T.);
#3205=ORIENTED_EDGE('',*,*,#3109,.T.);
#3206=ORIENTED_EDGE('',*,*,#3085,.T.);
#3207=EDGE_LOOP('',(#3201,#3202,#3203,#3204,#3205,#3206));
#3208=FACE_BOUND('',#3207,.T.);
#3209=ADVANCED_FACE('F2557',(#3200,#3208),#3189,.T.);
#3210=CARTESIAN_POINT('',(-293.,34.5,192.041451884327));
#3211=DIRECTION('',(1.,0.,0.));
#3212=DIRECTION('',(0.,0.,-1.));
#3213=AXIS2_PLACEMENT_3D('',#3210,#3211,#3212);
#3214=PLANE('',#3213);
#3215=ORIENTED_EDGE('',*,*,#811,.T.);
#3216=DIRECTION('',(0.,1.,0.));
#3217=VECTOR('',#3216,1.);
#3218=CARTESIAN_POINT('',(-293.,34.5,183.958548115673));
#3219=LINE('',#3218,#3217);
#3220=CARTESIAN_POINT('',(-293.,34.5,183.958548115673));
#3221=VERTEX_POINT('',#3220);
#3222=EDGE_CURVE('E997',#3221,#810,#3219,.T.);
#3223=ORIENTED_EDGE('',*,*,#3222,.F.);
#3224=DIRECTION('',(0.,0.,-1.));
#3225=VECTOR('',#3224,1.);
#3226=CARTESIAN_POINT('',(-293.,34.5,192.041451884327));
#3227=LINE('',#3226,#3225);
#3228=CARTESIAN_POINT('',(-293.,34.5,192.041451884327));
#3229=VERTEX_POINT('',#3228);
#3230=EDGE_CURVE('E978',#3229,#3221,#3227,.T.);
#3231=ORIENTED_EDGE('',*,*,#3230,.F.);
#3232=DIRECTION('',(0.,1.,0.));
#3233=VECTOR('',#3232,1.);
#3234=CARTESIAN_POINT('',(-293.,34.5,192.041451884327));
#3235=LINE('',#3234,#3233);
#3236=EDGE_CURVE('E1013',#3229,#808,#3235,.T.);
#3237=ORIENTED_EDGE('',*,*,#3236,.T.);
#3238=EDGE_LOOP('',(#3215,#3223,#3231,#3237));
#3239=FACE_BOUND('',#3238,.T.);
#3240=ADVANCED_FACE('F2565',(#3239),#3214,.F.);
#3241=CARTESIAN_POINT('',(-300.,34.5,196.082903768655));
#3242=DIRECTION('',(0.499999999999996,0.,0.866025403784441));
#3243=DIRECTION('',(0.866025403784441,0.,-0.499999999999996));
#3244=AXIS2_PLACEMENT_3D('',#3241,#3242,#3243);
#3245=PLANE('',#3244);
#3246=ORIENTED_EDGE('',*,*,#819,.T.);
#3247=ORIENTED_EDGE('',*,*,#3236,.F.);
#3248=DIRECTION('',(0.866025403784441,0.,-0.499999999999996));
#3249=VECTOR('',#3248,1.);
#3250=CARTESIAN_POINT('',(-300.,34.5,196.082903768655));
#3251=LINE('',#3250,#3249);
#3252=CARTESIAN_POINT('',(-300.,34.5,196.082903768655));
#3253=VERTEX_POINT('',#3252);
#3254=EDGE_CURVE('E994',#3253,#3229,#3251,.T.);
#3255=ORIENTED_EDGE('',*,*,#3254,.F.);
#3256=DIRECTION('',(0.,1.,0.));
#3257=VECTOR('',#3256,1.);
#3258=CARTESIAN_POINT('',(-300.,34.5,196.082903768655));
#3259=LINE('',#3258,#3257);
#3260=EDGE_CURVE('E1016',#3253,#818,#3259,.T.);
#3261=ORIENTED_EDGE('',*,*,#3260,.T.);
#3262=EDGE_LOOP('',(#3246,#3247,#3255,#3261));
#3263=FACE_BOUND('',#3262,.T.);
#3264=ADVANCED_FACE('F2570',(#3263),#3245,.F.);
#3265=CARTESIAN_POINT('',(-307.,34.5,192.041451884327));
#3266=DIRECTION('',(-0.500000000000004,0.,0.866025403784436));
#3267=DIRECTION('',(0.866025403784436,0.,0.500000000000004));
#3268=AXIS2_PLACEMENT_3D('',#3265,#3266,#3267);
#3269=PLANE('',#3268);
#3270=ORIENTED_EDGE('',*,*,#827,.T.);
#3271=ORIENTED_EDGE('',*,*,#3260,.F.);
#3272=DIRECTION('',(0.866025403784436,0.,0.500000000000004));
#3273=VECTOR('',#3272,1.);
#3274=CARTESIAN_POINT('',(-307.,34.5,192.041451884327));
#3275=LINE('',#3274,#3273);
#3276=CARTESIAN_POINT('',(-307.,34.5,192.041451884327));
#3277=VERTEX_POINT('',#3276);
#3278=EDGE_CURVE('E991',#3277,#3253,#3275,.T.);
#3279=ORIENTED_EDGE('',*,*,#3278,.F.);
#3280=DIRECTION('',(0.,1.,0.));
#3281=VECTOR('',#3280,1.);
#3282=CARTESIAN_POINT('',(-307.,34.5,192.041451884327));
#3283=LINE('',#3282,#3281);
#3284=EDGE_CURVE('E1018',#3277,#826,#3283,.T.);
#3285=ORIENTED_EDGE('',*,*,#3284,.T.);
#3286=EDGE_LOOP('',(#3270,#3271,#3279,#3285));
#3287=FACE_BOUND('',#3286,.T.);
#3288=ADVANCED_FACE('F2580',(#3287),#3269,.F.);
#3289=CARTESIAN_POINT('',(-307.,34.5,183.958548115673));
#3290=DIRECTION('',(-1.,0.,0.));
#3291=DIRECTION('',(0.,0.,1.));
#3292=AXIS2_PLACEMENT_3D('',#3289,#3290,#3291);
#3293=PLANE('',#3292);
#3294=ORIENTED_EDGE('',*,*,#835,.T.);
#3295=ORIENTED_EDGE('',*,*,#3284,.F.);
#3296=DIRECTION('',(0.,0.,1.));
#3297=VECTOR('',#3296,1.);
#3298=CARTESIAN_POINT('',(-307.,34.5,183.958548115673));
#3299=LINE('',#3298,#3297);
#3300=CARTESIAN_POINT('',(-307.,34.5,183.958548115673));
#3301=VERTEX_POINT('',#3300);
#3302=EDGE_CURVE('E988',#3301,#3277,#3299,.T.);
#3303=ORIENTED_EDGE('',*,*,#3302,.F.);
#3304=DIRECTION('',(0.,1.,0.));
#3305=VECTOR('',#3304,1.);
#3306=CARTESIAN_POINT('',(-307.,34.5,183.958548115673));
#3307=LINE('',#3306,#3305);
#3308=EDGE_CURVE('E1020',#3301,#834,#3307,.T.);
#3309=ORIENTED_EDGE('',*,*,#3308,.T.);
#3310=EDGE_LOOP('',(#3294,#3295,#3303,#3309));
#3311=FACE_BOUND('',#3310,.T.);
#3312=ADVANCED_FACE('F2590',(#3311),#3293,.F.);
#3313=CARTESIAN_POINT('',(-300.,34.5,179.917096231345));
#3314=DIRECTION('',(-0.499999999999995,0.,-0.866025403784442));
#3315=DIRECTION('',(-0.866025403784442,0.,0.499999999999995));
#3316=AXIS2_PLACEMENT_3D('',#3313,#3314,#3315);
#3317=PLANE('',#3316);
#3318=ORIENTED_EDGE('',*,*,#843,.T.);
#3319=ORIENTED_EDGE('',*,*,#3308,.F.);
#3320=DIRECTION('',(-0.866025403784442,0.,0.499999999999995));
#3321=VECTOR('',#3320,1.);
#3322=CARTESIAN_POINT('',(-300.,34.5,179.917096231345));
#3323=LINE('',#3322,#3321);
#3324=CARTESIAN_POINT('',(-300.,34.5,179.917096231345));
#3325=VERTEX_POINT('',#3324);
#3326=EDGE_CURVE('E985',#3325,#3301,#3323,.T.);
#3327=ORIENTED_EDGE('',*,*,#3326,.F.);
#3328=DIRECTION('',(0.,1.,0.));
#3329=VECTOR('',#3328,1.);
#3330=CARTESIAN_POINT('',(-300.,34.5,179.917096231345));
#3331=LINE('',#3330,#3329);
#3332=EDGE_CURVE('E1022',#3325,#842,#3331,.T.);
#3333=ORIENTED_EDGE('',*,*,#3332,.T.);
#3334=EDGE_LOOP('',(#3318,#3319,#3327,#3333));
#3335=FACE_BOUND('',#3334,.T.);
#3336=ADVANCED_FACE('F2600',(#3335),#3317,.F.);
#3337=CARTESIAN_POINT('',(-293.,34.5,183.958548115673));
#3338=DIRECTION('',(0.500000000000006,0.,-0.866025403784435));
#3339=DIRECTION('',(-0.866025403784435,0.,-0.500000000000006));
#3340=AXIS2_PLACEMENT_3D('',#3337,#3338,#3339);
#3341=PLANE('',#3340);
#3342=ORIENTED_EDGE('',*,*,#849,.T.);
#3343=ORIENTED_EDGE('',*,*,#3332,.F.);
#3344=DIRECTION('',(-0.866025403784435,0.,-0.500000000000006));
#3345=VECTOR('',#3344,1.);
#3346=CARTESIAN_POINT('',(-293.,34.5,183.958548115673));
#3347=LINE('',#3346,#3345);
#3348=EDGE_CURVE('E981',#3221,#3325,#3347,.T.);
#3349=ORIENTED_EDGE('',*,*,#3348,.F.);
#3350=ORIENTED_EDGE('',*,*,#3222,.T.);
#3351=EDGE_LOOP('',(#3342,#3343,#3349,#3350));
#3352=FACE_BOUND('',#3351,.T.);
#3353=ADVANCED_FACE('F2610',(#3352),#3341,.F.);
#3354=CARTESIAN_POINT('',(0.,34.5,0.));
#3355=DIRECTION('',(0.,1.,0.));
#3356=DIRECTION('',(0.,0.,1.));
#3357=AXIS2_PLACEMENT_3D('',#3354,#3355,#3356);
#3358=PLANE('',#3357);
#3359=CARTESIAN_POINT('',(-300.,34.5,188.));
#3360=DIRECTION('',(0.,1.,0.));
#3361=DIRECTION('',(0.,0.,1.));
#3362=AXIS2_PLACEMENT_3D('',#3359,#3360,#3361);
#3363=CIRCLE('',#3362,3.99999999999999);
#3364=CARTESIAN_POINT('',(-300.,34.5,192.));
#3365=VERTEX_POINT('',#3364);
#3366=EDGE_CURVE('E1634',#3365,#3365,#3363,.T.);
#3367=ORIENTED_EDGE('',*,*,#3366,.F.);
#3368=EDGE_LOOP('',(#3367));
#3369=FACE_BOUND('',#3368,.T.);
#3370=ORIENTED_EDGE('',*,*,#3230,.T.);
#3371=ORIENTED_EDGE('',*,*,#3348,.T.);
#3372=ORIENTED_EDGE('',*,*,#3326,.T.);
#3373=ORIENTED_EDGE('',*,*,#3302,.T.);
#3374=ORIENTED_EDGE('',*,*,#3278,.T.);
#3375=ORIENTED_EDGE('',*,*,#3254,.T.);
#3376=EDGE_LOOP('',(#3370,#3371,#3372,#3373,#3374,#3375));
#3377=FACE_BOUND('',#3376,.T.);
#3378=ADVANCED_FACE('F2620',(#3369,#3377),#3358,.T.);
#3379=CARTESIAN_POINT('',(-220.,34.5,192.041451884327));
#3380=DIRECTION('',(1.,0.,0.));
#3381=DIRECTION('',(0.,0.,-1.));
#3382=AXIS2_PLACEMENT_3D('',#3379,#3380,#3381);
#3383=PLANE('',#3382);
#3384=ORIENTED_EDGE('',*,*,#761,.T.);
#3385=DIRECTION('',(0.,1.,0.));
#3386=VECTOR('',#3385,1.);
#3387=CARTESIAN_POINT('',(-220.,34.5,183.958548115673));
#3388=LINE('',#3387,#3386);
#3389=CARTESIAN_POINT('',(-220.,34.5,183.958548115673));
#3390=VERTEX_POINT('',#3389);
#3391=EDGE_CURVE('E949',#3390,#760,#3388,.T.);
#3392=ORIENTED_EDGE('',*,*,#3391,.F.);
#3393=DIRECTION('',(0.,0.,-1.));
#3394=VECTOR('',#3393,1.);
#3395=CARTESIAN_POINT('',(-220.,34.5,192.041451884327));
#3396=LINE('',#3395,#3394);
#3397=CARTESIAN_POINT('',(-220.,34.5,192.041451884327));
#3398=VERTEX_POINT('',#3397);
#3399=EDGE_CURVE('E930',#3398,#3390,#3396,.T.);
#3400=ORIENTED_EDGE('',*,*,#3399,.F.);
#3401=DIRECTION('',(0.,1.,0.));
#3402=VECTOR('',#3401,1.);
#3403=CARTESIAN_POINT('',(-220.,34.5,192.041451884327));
#3404=LINE('',#3403,#3402);
#3405=EDGE_CURVE('E965',#3398,#758,#3404,.T.);
#3406=ORIENTED_EDGE('',*,*,#3405,.T.);
#3407=EDGE_LOOP('',(#3384,#3392,#3400,#3406));
#3408=FACE_BOUND('',#3407,.T.);
#3409=ADVANCED_FACE('F2628',(#3408),#3383,.F.);
#3410=CARTESIAN_POINT('',(-227.,34.5,196.082903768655));
#3411=DIRECTION('',(0.499999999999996,0.,0.866025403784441));
#3412=DIRECTION('',(0.866025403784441,0.,-0.499999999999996));
#3413=AXIS2_PLACEMENT_3D('',#3410,#3411,#3412);
#3414=PLANE('',#3413);
#3415=ORIENTED_EDGE('',*,*,#769,.T.);
#3416=ORIENTED_EDGE('',*,*,#3405,.F.);
#3417=DIRECTION('',(0.866025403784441,0.,-0.499999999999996));
#3418=VECTOR('',#3417,1.);
#3419=CARTESIAN_POINT('',(-227.,34.5,196.082903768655));
#3420=LINE('',#3419,#3418);
#3421=CARTESIAN_POINT('',(-227.,34.5,196.082903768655));
#3422=VERTEX_POINT('',#3421);
#3423=EDGE_CURVE('E946',#3422,#3398,#3420,.T.);
#3424=ORIENTED_EDGE('',*,*,#3423,.F.);
#3425=DIRECTION('',(0.,1.,0.));
#3426=VECTOR('',#3425,1.);
#3427=CARTESIAN_POINT('',(-227.,34.5,196.082903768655));
#3428=LINE('',#3427,#3426);
#3429=EDGE_CURVE('E968',#3422,#768,#3428,.T.);
#3430=ORIENTED_EDGE('',*,*,#3429,.T.);
#3431=EDGE_LOOP('',(#3415,#3416,#3424,#3430));
#3432=FACE_BOUND('',#3431,.T.);
#3433=ADVANCED_FACE('F2633',(#3432),#3414,.F.);
#3434=CARTESIAN_POINT('',(-234.,34.5,192.041451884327));
#3435=DIRECTION('',(-0.500000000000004,0.,0.866025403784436));
#3436=DIRECTION('',(0.866025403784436,0.,0.500000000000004));
#3437=AXIS2_PLACEMENT_3D('',#3434,#3435,#3436);
#3438=PLANE('',#3437);
#3439=ORIENTED_EDGE('',*,*,#777,.T.);
#3440=ORIENTED_EDGE('',*,*,#3429,.F.);
#3441=DIRECTION('',(0.866025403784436,0.,0.500000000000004));
#3442=VECTOR('',#3441,1.);
#3443=CARTESIAN_POINT('',(-234.,34.5,192.041451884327));
#3444=LINE('',#3443,#3442);
#3445=CARTESIAN_POINT('',(-234.,34.5,192.041451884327));
#3446=VERTEX_POINT('',#3445);
#3447=EDGE_CURVE('E943',#3446,#3422,#3444,.T.);
#3448=ORIENTED_EDGE('',*,*,#3447,.F.);
#3449=DIRECTION('',(0.,1.,0.));
#3450=VECTOR('',#3449,1.);
#3451=CARTESIAN_POINT('',(-234.,34.5,192.041451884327));
#3452=LINE('',#3451,#3450);
#3453=EDGE_CURVE('E970',#3446,#776,#3452,.T.);
#3454=ORIENTED_EDGE('',*,*,#3453,.T.);
#3455=EDGE_LOOP('',(#3439,#3440,#3448,#3454));
#3456=FACE_BOUND('',#3455,.T.);
#3457=ADVANCED_FACE('F2643',(#3456),#3438,.F.);
#3458=CARTESIAN_POINT('',(-234.,34.5,183.958548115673));
#3459=DIRECTION('',(-1.,0.,0.));
#3460=DIRECTION('',(0.,0.,1.));
#3461=AXIS2_PLACEMENT_3D('',#3458,#3459,#3460);
#3462=PLANE('',#3461);
#3463=ORIENTED_EDGE('',*,*,#785,.T.);
#3464=ORIENTED_EDGE('',*,*,#3453,.F.);
#3465=DIRECTION('',(0.,0.,1.));
#3466=VECTOR('',#3465,1.);
#3467=CARTESIAN_POINT('',(-234.,34.5,183.958548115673));
#3468=LINE('',#3467,#3466);
#3469=CARTESIAN_POINT('',(-234.,34.5,183.958548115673));
#3470=VERTEX_POINT('',#3469);
#3471=EDGE_CURVE('E940',#3470,#3446,#3468,.T.);
#3472=ORIENTED_EDGE('',*,*,#3471,.F.);
#3473=DIRECTION('',(0.,1.,0.));
#3474=VECTOR('',#3473,1.);
#3475=CARTESIAN_POINT('',(-234.,34.5,183.958548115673));
#3476=LINE('',#3475,#3474);
#3477=EDGE_CURVE('E972',#3470,#784,#3476,.T.);
#3478=ORIENTED_EDGE('',*,*,#3477,.T.);
#3479=EDGE_LOOP('',(#3463,#3464,#3472,#3478));
#3480=FACE_BOUND('',#3479,.T.);
#3481=ADVANCED_FACE('F2653',(#3480),#3462,.F.);
#3482=CARTESIAN_POINT('',(-227.,34.5,179.917096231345));
#3483=DIRECTION('',(-0.499999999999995,0.,-0.866025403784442));
#3484=DIRECTION('',(-0.866025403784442,0.,0.499999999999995));
#3485=AXIS2_PLACEMENT_3D('',#3482,#3483,#3484);
#3486=PLANE('',#3485);
#3487=ORIENTED_EDGE('',*,*,#793,.T.);
#3488=ORIENTED_EDGE('',*,*,#3477,.F.);
#3489=DIRECTION('',(-0.866025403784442,0.,0.499999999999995));
#3490=VECTOR('',#3489,1.);
#3491=CARTESIAN_POINT('',(-227.,34.5,179.917096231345));
#3492=LINE('',#3491,#3490);
#3493=CARTESIAN_POINT('',(-227.,34.5,179.917096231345));
#3494=VERTEX_POINT('',#3493);
#3495=EDGE_CURVE('E937',#3494,#3470,#3492,.T.);
#3496=ORIENTED_EDGE('',*,*,#3495,.F.);
#3497=DIRECTION('',(0.,1.,0.));
#3498=VECTOR('',#3497,1.);
#3499=CARTESIAN_POINT('',(-227.,34.5,179.917096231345));
#3500=LINE('',#3499,#3498);
#3501=EDGE_CURVE('E974',#3494,#792,#3500,.T.);
#3502=ORIENTED_EDGE('',*,*,#3501,.T.);
#3503=EDGE_LOOP('',(#3487,#3488,#3496,#3502));
#3504=FACE_BOUND('',#3503,.T.);
#3505=ADVANCED_FACE('F2663',(#3504),#3486,.F.);
#3506=CARTESIAN_POINT('',(-220.,34.5,183.958548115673));
#3507=DIRECTION('',(0.500000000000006,0.,-0.866025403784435));
#3508=DIRECTION('',(-0.866025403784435,0.,-0.500000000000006));
#3509=AXIS2_PLACEMENT_3D('',#3506,#3507,#3508);
#3510=PLANE('',#3509);
#3511=ORIENTED_EDGE('',*,*,#799,.T.);
#3512=ORIENTED_EDGE('',*,*,#3501,.F.);
#3513=DIRECTION('',(-0.866025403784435,0.,-0.500000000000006));
#3514=VECTOR('',#3513,1.);
#3515=CARTESIAN_POINT('',(-220.,34.5,183.958548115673));
#3516=LINE('',#3515,#3514);
#3517=EDGE_CURVE('E933',#3390,#3494,#3516,.T.);
#3518=ORIENTED_EDGE('',*,*,#3517,.F.);
#3519=ORIENTED_EDGE('',*,*,#3391,.T.);
#3520=EDGE_LOOP('',(#3511,#3512,#3518,#3519));
#3521=FACE_BOUND('',#3520,.T.);
#3522=ADVANCED_FACE('F2673',(#3521),#3510,.F.);
#3523=CARTESIAN_POINT('',(0.,34.5,0.));
#3524=DIRECTION('',(0.,1.,0.));
#3525=DIRECTION('',(0.,0.,1.));
#3526=AXIS2_PLACEMENT_3D('',#3523,#3524,#3525);
#3527=PLANE('',#3526);
#3528=CARTESIAN_POINT('',(-227.,34.5,188.));
#3529=DIRECTION('',(0.,1.,0.));
#3530=DIRECTION('',(0.,0.,1.));
#3531=AXIS2_PLACEMENT_3D('',#3528,#3529,#3530);
#3532=CIRCLE('',#3531,3.99999999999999);
#3533=CARTESIAN_POINT('',(-227.,34.5,192.));
#3534=VERTEX_POINT('',#3533);
#3535=EDGE_CURVE('E1638',#3534,#3534,#3532,.T.);
#3536=ORIENTED_EDGE('',*,*,#3535,.F.);
#3537=EDGE_LOOP('',(#3536));
#3538=FACE_BOUND('',#3537,.T.);
#3539=ORIENTED_EDGE('',*,*,#3399,.T.);
#3540=ORIENTED_EDGE('',*,*,#3517,.T.);
#3541=ORIENTED_EDGE('',*,*,#3495,.T.);
#3542=ORIENTED_EDGE('',*,*,#3471,.T.);
#3543=ORIENTED_EDGE('',*,*,#3447,.T.);
#3544=ORIENTED_EDGE('',*,*,#3423,.T.);
#3545=EDGE_LOOP('',(#3539,#3540,#3541,#3542,#3543,#3544));
#3546=FACE_BOUND('',#3545,.T.);
#3547=ADVANCED_FACE('F2683',(#3538,#3546),#3527,.T.);
#3548=CARTESIAN_POINT('',(236.,34.5,148.041451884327));
#3549=DIRECTION('',(1.,0.,0.));
#3550=DIRECTION('',(0.,0.,-1.));
#3551=AXIS2_PLACEMENT_3D('',#3548,#3549,#3550);
#3552=PLANE('',#3551);
#3553=ORIENTED_EDGE('',*,*,#711,.T.);
#3554=DIRECTION('',(0.,1.,0.));
#3555=VECTOR('',#3554,1.);
#3556=CARTESIAN_POINT('',(236.,34.5,139.958548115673));
#3557=LINE('',#3556,#3555);
#3558=CARTESIAN_POINT('',(236.,34.5,139.958548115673));
#3559=VERTEX_POINT('',#3558);
#3560=EDGE_CURVE('E901',#3559,#710,#3557,.T.);
#3561=ORIENTED_EDGE('',*,*,#3560,.F.);
#3562=DIRECTION('',(0.,0.,-1.));
#3563=VECTOR('',#3562,1.);
#3564=CARTESIAN_POINT('',(236.,34.5,148.041451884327));
#3565=LINE('',#3564,#3563);
#3566=CARTESIAN_POINT('',(236.,34.5,148.041451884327));
#3567=VERTEX_POINT('',#3566);
#3568=EDGE_CURVE('E882',#3567,#3559,#3565,.T.);
#3569=ORIENTED_EDGE('',*,*,#3568,.F.);
#3570=DIRECTION('',(0.,1.,0.));
#3571=VECTOR('',#3570,1.);
#3572=CARTESIAN_POINT('',(236.,34.5,148.041451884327));
#3573=LINE('',#3572,#3571);
#3574=EDGE_CURVE('E917',#3567,#708,#3573,.T.);
#3575=ORIENTED_EDGE('',*,*,#3574,.T.);
#3576=EDGE_LOOP('',(#3553,#3561,#3569,#3575));
#3577=FACE_BOUND('',#3576,.T.);
#3578=ADVANCED_FACE('F2691',(#3577),#3552,.F.);
#3579=CARTESIAN_POINT('',(229.,34.5,152.082903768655));
#3580=DIRECTION('',(0.499999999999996,0.,0.866025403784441));
#3581=DIRECTION('',(0.866025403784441,0.,-0.499999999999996));
#3582=AXIS2_PLACEMENT_3D('',#3579,#3580,#3581);
#3583=PLANE('',#3582);
#3584=ORIENTED_EDGE('',*,*,#719,.T.);
#3585=ORIENTED_EDGE('',*,*,#3574,.F.);
#3586=DIRECTION('',(0.866025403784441,0.,-0.499999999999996));
#3587=VECTOR('',#3586,1.);
#3588=CARTESIAN_POINT('',(229.,34.5,152.082903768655));
#3589=LINE('',#3588,#3587);
#3590=CARTESIAN_POINT('',(229.,34.5,152.082903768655));
#3591=VERTEX_POINT('',#3590);
#3592=EDGE_CURVE('E898',#3591,#3567,#3589,.T.);
#3593=ORIENTED_EDGE('',*,*,#3592,.F.);
#3594=DIRECTION('',(0.,1.,0.));
#3595=VECTOR('',#3594,1.);
#3596=CARTESIAN_POINT('',(229.,34.5,152.082903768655));
#3597=LINE('',#3596,#3595);
#3598=EDGE_CURVE('E920',#3591,#718,#3597,.T.);
#3599=ORIENTED_EDGE('',*,*,#3598,.T.);
#3600=EDGE_LOOP('',(#3584,#3585,#3593,#3599));
#3601=FACE_BOUND('',#3600,.T.);
#3602=ADVANCED_FACE('F2696',(#3601),#3583,.F.);
#3603=CARTESIAN_POINT('',(222.,34.5,148.041451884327));
#3604=DIRECTION('',(-0.500000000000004,0.,0.866025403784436));
#3605=DIRECTION('',(0.866025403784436,0.,0.500000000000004));
#3606=AXIS2_PLACEMENT_3D('',#3603,#3604,#3605);
#3607=PLANE('',#3606);
#3608=ORIENTED_EDGE('',*,*,#727,.T.);
#3609=ORIENTED_EDGE('',*,*,#3598,.F.);
#3610=DIRECTION('',(0.866025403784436,0.,0.500000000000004));
#3611=VECTOR('',#3610,1.);
#3612=CARTESIAN_POINT('',(222.,34.5,148.041451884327));
#3613=LINE('',#3612,#3611);
#3614=CARTESIAN_POINT('',(222.,34.5,148.041451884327));
#3615=VERTEX_POINT('',#3614);
#3616=EDGE_CURVE('E895',#3615,#3591,#3613,.T.);
#3617=ORIENTED_EDGE('',*,*,#3616,.F.);
#3618=DIRECTION('',(0.,1.,0.));
#3619=VECTOR('',#3618,1.);
#3620=CARTESIAN_POINT('',(222.,34.5,148.041451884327));
#3621=LINE('',#3620,#3619);
#3622=EDGE_CURVE('E922',#3615,#726,#3621,.T.);
#3623=ORIENTED_EDGE('',*,*,#3622,.T.);
#3624=EDGE_LOOP('',(#3608,#3609,#3617,#3623));
#3625=FACE_BOUND('',#3624,.T.);
#3626=ADVANCED_FACE('F2706',(#3625),#3607,.F.);
#3627=CARTESIAN_POINT('',(222.,34.5,139.958548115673));
#3628=DIRECTION('',(-1.,0.,0.));
#3629=DIRECTION('',(0.,0.,1.));
#3630=AXIS2_PLACEMENT_3D('',#3627,#3628,#3629);
#3631=PLANE('',#3630);
#3632=ORIENTED_EDGE('',*,*,#735,.T.);
#3633=ORIENTED_EDGE('',*,*,#3622,.F.);
#3634=DIRECTION('',(0.,0.,1.));
#3635=VECTOR('',#3634,1.);
#3636=CARTESIAN_POINT('',(222.,34.5,139.958548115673));
#3637=LINE('',#3636,#3635);
#3638=CARTESIAN_POINT('',(222.,34.5,139.958548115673));
#3639=VERTEX_POINT('',#3638);
#3640=EDGE_CURVE('E892',#3639,#3615,#3637,.T.);
#3641=ORIENTED_EDGE('',*,*,#3640,.F.);
#3642=DIRECTION('',(0.,1.,0.));
#3643=VECTOR('',#3642,1.);
#3644=CARTESIAN_POINT('',(222.,34.5,139.958548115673));
#3645=LINE('',#3644,#3643);
#3646=EDGE_CURVE('E924',#3639,#734,#3645,.T.);
#3647=ORIENTED_EDGE('',*,*,#3646,.T.);
#3648=EDGE_LOOP('',(#3632,#3633,#3641,#3647));
#3649=FACE_BOUND('',#3648,.T.);
#3650=ADVANCED_FACE('F2716',(#3649),#3631,.F.);
#3651=CARTESIAN_POINT('',(229.,34.5,135.917096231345));
#3652=DIRECTION('',(-0.499999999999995,0.,-0.866025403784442));
#3653=DIRECTION('',(-0.866025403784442,0.,0.499999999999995));
#3654=AXIS2_PLACEMENT_3D('',#3651,#3652,#3653);
#3655=PLANE('',#3654);
#3656=ORIENTED_EDGE('',*,*,#743,.T.);
#3657=ORIENTED_EDGE('',*,*,#3646,.F.);
#3658=DIRECTION('',(-0.866025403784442,0.,0.499999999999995));
#3659=VECTOR('',#3658,1.);
#3660=CARTESIAN_POINT('',(229.,34.5,135.917096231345));
#3661=LINE('',#3660,#3659);
#3662=CARTESIAN_POINT('',(229.,34.5,135.917096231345));
#3663=VERTEX_POINT('',#3662);
#3664=EDGE_CURVE('E889',#3663,#3639,#3661,.T.);
#3665=ORIENTED_EDGE('',*,*,#3664,.F.);
#3666=DIRECTION('',(0.,1.,0.));
#3667=VECTOR('',#3666,1.);
#3668=CARTESIAN_POINT('',(229.,34.5,135.917096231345));
#3669=LINE('',#3668,#3667);
#3670=EDGE_CURVE('E926',#3663,#742,#3669,.T.);
#3671=ORIENTED_EDGE('',*,*,#3670,.T.);
#3672=EDGE_LOOP('',(#3656,#3657,#3665,#3671));
#3673=FACE_BOUND('',#3672,.T.);
#3674=ADVANCED_FACE('F2726',(#3673),#3655,.F.);
#3675=CARTESIAN_POINT('',(236.,34.5,139.958548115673));
#3676=DIRECTION('',(0.500000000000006,0.,-0.866025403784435));
#3677=DIRECTION('',(-0.866025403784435,0.,-0.500000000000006));
#3678=AXIS2_PLACEMENT_3D('',#3675,#3676,#3677);
#3679=PLANE('',#3678);
#3680=ORIENTED_EDGE('',*,*,#749,.T.);
#3681=ORIENTED_EDGE('',*,*,#3670,.F.);
#3682=DIRECTION('',(-0.866025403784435,0.,-0.500000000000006));
#3683=VECTOR('',#3682,1.);
#3684=CARTESIAN_POINT('',(236.,34.5,139.958548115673));
#3685=LINE('',#3684,#3683);
#3686=EDGE_CURVE('E885',#3559,#3663,#3685,.T.);
#3687=ORIENTED_EDGE('',*,*,#3686,.F.);
#3688=ORIENTED_EDGE('',*,*,#3560,.T.);
#3689=EDGE_LOOP('',(#3680,#3681,#3687,#3688));
#3690=FACE_BOUND('',#3689,.T.);
#3691=ADVANCED_FACE('F2736',(#3690),#3679,.F.);
#3692=CARTESIAN_POINT('',(0.,34.5,0.));
#3693=DIRECTION('',(0.,1.,0.));
#3694=DIRECTION('',(0.,0.,1.));
#3695=AXIS2_PLACEMENT_3D('',#3692,#3693,#3694);
#3696=PLANE('',#3695);
#3697=CARTESIAN_POINT('',(229.,34.5,144.));
#3698=DIRECTION('',(0.,1.,0.));
#3699=DIRECTION('',(0.,0.,1.));
#3700=AXIS2_PLACEMENT_3D('',#3697,#3698,#3699);
#3701=CIRCLE('',#3700,3.99999999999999);
#3702=CARTESIAN_POINT('',(229.,34.5,148.));
#3703=VERTEX_POINT('',#3702);
#3704=EDGE_CURVE('E1646',#3703,#3703,#3701,.T.);
#3705=ORIENTED_EDGE('',*,*,#3704,.F.);
#3706=EDGE_LOOP('',(#3705));
#3707=FACE_BOUND('',#3706,.T.);
#3708=ORIENTED_EDGE('',*,*,#3568,.T.);
#3709=ORIENTED_EDGE('',*,*,#3686,.T.);
#3710=ORIENTED_EDGE('',*,*,#3664,.T.);
#3711=ORIENTED_EDGE('',*,*,#3640,.T.);
#3712=ORIENTED_EDGE('',*,*,#3616,.T.);
#3713=ORIENTED_EDGE('',*,*,#3592,.T.);
#3714=EDGE_LOOP('',(#3708,#3709,#3710,#3711,#3712,#3713));
#3715=FACE_BOUND('',#3714,.T.);
#3716=ADVANCED_FACE('F2746',(#3707,#3715),#3696,.T.);
#3717=CARTESIAN_POINT('',(236.,34.5,192.041451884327));
#3718=DIRECTION('',(1.,0.,0.));
#3719=DIRECTION('',(0.,0.,-1.));
#3720=AXIS2_PLACEMENT_3D('',#3717,#3718,#3719);
#3721=PLANE('',#3720);
#3722=ORIENTED_EDGE('',*,*,#661,.T.);
#3723=DIRECTION('',(0.,1.,0.));
#3724=VECTOR('',#3723,1.);
#3725=CARTESIAN_POINT('',(236.,34.5,183.958548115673));
#3726=LINE('',#3725,#3724);
#3727=CARTESIAN_POINT('',(236.,34.5,183.958548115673));
#3728=VERTEX_POINT('',#3727);
#3729=EDGE_CURVE('E853',#3728,#660,#3726,.T.);
#3730=ORIENTED_EDGE('',*,*,#3729,.F.);
#3731=DIRECTION('',(0.,0.,-1.));
#3732=VECTOR('',#3731,1.);
#3733=CARTESIAN_POINT('',(236.,34.5,192.041451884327));
#3734=LINE('',#3733,#3732);
#3735=CARTESIAN_POINT('',(236.,34.5,192.041451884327));
#3736=VERTEX_POINT('',#3735);
#3737=EDGE_CURVE('E834',#3736,#3728,#3734,.T.);
#3738=ORIENTED_EDGE('',*,*,#3737,.F.);
#3739=DIRECTION('',(0.,1.,0.));
#3740=VECTOR('',#3739,1.);
#3741=CARTESIAN_POINT('',(236.,34.5,192.041451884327));
#3742=LINE('',#3741,#3740);
#3743=EDGE_CURVE('E869',#3736,#658,#3742,.T.);
#3744=ORIENTED_EDGE('',*,*,#3743,.T.);
#3745=EDGE_LOOP('',(#3722,#3730,#3738,#3744));
#3746=FACE_BOUND('',#3745,.T.);
#3747=ADVANCED_FACE('F2754',(#3746),#3721,.F.);
#3748=CARTESIAN_POINT('',(229.,34.5,196.082903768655));
#3749=DIRECTION('',(0.499999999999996,0.,0.866025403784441));
#3750=DIRECTION('',(0.866025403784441,0.,-0.499999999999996));
#3751=AXIS2_PLACEMENT_3D('',#3748,#3749,#3750);
#3752=PLANE('',#3751);
#3753=ORIENTED_EDGE('',*,*,#669,.T.);
#3754=ORIENTED_EDGE('',*,*,#3743,.F.);
#3755=DIRECTION('',(0.866025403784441,0.,-0.499999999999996));
#3756=VECTOR('',#3755,1.);
#3757=CARTESIAN_POINT('',(229.,34.5,196.082903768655));
#3758=LINE('',#3757,#3756);
#3759=CARTESIAN_POINT('',(229.,34.5,196.082903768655));
#3760=VERTEX_POINT('',#3759);
#3761=EDGE_CURVE('E850',#3760,#3736,#3758,.T.);
#3762=ORIENTED_EDGE('',*,*,#3761,.F.);
#3763=DIRECTION('',(0.,1.,0.));
#3764=VECTOR('',#3763,1.);
#3765=CARTESIAN_POINT('',(229.,34.5,196.082903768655));
#3766=LINE('',#3765,#3764);
#3767=EDGE_CURVE('E872',#3760,#668,#3766,.T.);
#3768=ORIENTED_EDGE('',*,*,#3767,.T.);
#3769=EDGE_LOOP('',(#3753,#3754,#3762,#3768));
#3770=FACE_BOUND('',#3769,.T.);
#3771=ADVANCED_FACE('F2759',(#3770),#3752,.F.);
#3772=CARTESIAN_POINT('',(222.,34.5,192.041451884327));
#3773=DIRECTION('',(-0.500000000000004,0.,0.866025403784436));
#3774=DIRECTION('',(0.866025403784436,0.,0.500000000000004));
#3775=AXIS2_PLACEMENT_3D('',#3772,#3773,#3774);
#3776=PLANE('',#3775);
#3777=ORIENTED_EDGE('',*,*,#677,.T.);
#3778=ORIENTED_EDGE('',*,*,#3767,.F.);
#3779=DIRECTION('',(0.866025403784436,0.,0.500000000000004));
#3780=VECTOR('',#3779,1.);
#3781=CARTESIAN_POINT('',(222.,34.5,192.041451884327));
#3782=LINE('',#3781,#3780);
#3783=CARTESIAN_POINT('',(222.,34.5,192.041451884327));
#3784=VERTEX_POINT('',#3783);
#3785=EDGE_CURVE('E847',#3784,#3760,#3782,.T.);
#3786=ORIENTED_EDGE('',*,*,#3785,.F.);
#3787=DIRECTION('',(0.,1.,0.));
#3788=VECTOR('',#3787,1.);
#3789=CARTESIAN_POINT('',(222.,34.5,192.041451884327));
#3790=LINE('',#3789,#3788);
#3791=EDGE_CURVE('E874',#3784,#676,#3790,.T.);
#3792=ORIENTED_EDGE('',*,*,#3791,.T.);
#3793=EDGE_LOOP('',(#3777,#3778,#3786,#3792));
#3794=FACE_BOUND('',#3793,.T.);
#3795=ADVANCED_FACE('F2769',(#3794),#3776,.F.);
#3796=CARTESIAN_POINT('',(222.,34.5,183.958548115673));
#3797=DIRECTION('',(-1.,0.,0.));
#3798=DIRECTION('',(0.,0.,1.));
#3799=AXIS2_PLACEMENT_3D('',#3796,#3797,#3798);
#3800=PLANE('',#3799);
#3801=ORIENTED_EDGE('',*,*,#685,.T.);
#3802=ORIENTED_EDGE('',*,*,#3791,.F.);
#3803=DIRECTION('',(0.,0.,1.));
#3804=VECTOR('',#3803,1.);
#3805=CARTESIAN_POINT('',(222.,34.5,183.958548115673));
#3806=LINE('',#3805,#3804);
#3807=CARTESIAN_POINT('',(222.,34.5,183.958548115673));
#3808=VERTEX_POINT('',#3807);
#3809=EDGE_CURVE('E844',#3808,#3784,#3806,.T.);
#3810=ORIENTED_EDGE('',*,*,#3809,.F.);
#3811=DIRECTION('',(0.,1.,0.));
#3812=VECTOR('',#3811,1.);
#3813=CARTESIAN_POINT('',(222.,34.5,183.958548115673));
#3814=LINE('',#3813,#3812);
#3815=EDGE_CURVE('E876',#3808,#684,#3814,.T.);
#3816=ORIENTED_EDGE('',*,*,#3815,.T.);
#3817=EDGE_LOOP('',(#3801,#3802,#3810,#3816));
#3818=FACE_BOUND('',#3817,.T.);
#3819=ADVANCED_FACE('F2779',(#3818),#3800,.F.);
#3820=CARTESIAN_POINT('',(229.,34.5,179.917096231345));
#3821=DIRECTION('',(-0.499999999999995,0.,-0.866025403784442));
#3822=DIRECTION('',(-0.866025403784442,0.,0.499999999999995));
#3823=AXIS2_PLACEMENT_3D('',#3820,#3821,#3822);
#3824=PLANE('',#3823);
#3825=ORIENTED_EDGE('',*,*,#693,.T.);
#3826=ORIENTED_EDGE('',*,*,#3815,.F.);
#3827=DIRECTION('',(-0.866025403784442,0.,0.499999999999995));
#3828=VECTOR('',#3827,1.);
#3829=CARTESIAN_POINT('',(229.,34.5,179.917096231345));
#3830=LINE('',#3829,#3828);
#3831=CARTESIAN_POINT('',(229.,34.5,179.917096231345));
#3832=VERTEX_POINT('',#3831);
#3833=EDGE_CURVE('E841',#3832,#3808,#3830,.T.);
#3834=ORIENTED_EDGE('',*,*,#3833,.F.);
#3835=DIRECTION('',(0.,1.,0.));
#3836=VECTOR('',#3835,1.);
#3837=CARTESIAN_POINT('',(229.,34.5,179.917096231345));
#3838=LINE('',#3837,#3836);
#3839=EDGE_CURVE('E878',#3832,#692,#3838,.T.);
#3840=ORIENTED_EDGE('',*,*,#3839,.T.);
#3841=EDGE_LOOP('',(#3825,#3826,#3834,#3840));
#3842=FACE_BOUND('',#3841,.T.);
#3843=ADVANCED_FACE('F2789',(#3842),#3824,.F.);
#3844=CARTESIAN_POINT('',(236.,34.5,183.958548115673));
#3845=DIRECTION('',(0.500000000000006,0.,-0.866025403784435));
#3846=DIRECTION('',(-0.866025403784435,0.,-0.500000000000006));
#3847=AXIS2_PLACEMENT_3D('',#3844,#3845,#3846);
#3848=PLANE('',#3847);
#3849=ORIENTED_EDGE('',*,*,#699,.T.);
#3850=ORIENTED_EDGE('',*,*,#3839,.F.);
#3851=DIRECTION('',(-0.866025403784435,0.,-0.500000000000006));
#3852=VECTOR('',#3851,1.);
#3853=CARTESIAN_POINT('',(236.,34.5,183.958548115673));
#3854=LINE('',#3853,#3852);
#3855=EDGE_CURVE('E837',#3728,#3832,#3854,.T.);
#3856=ORIENTED_EDGE('',*,*,#3855,.F.);
#3857=ORIENTED_EDGE('',*,*,#3729,.T.);
#3858=EDGE_LOOP('',(#3849,#3850,#3856,#3857));
#3859=FACE_BOUND('',#3858,.T.);
#3860=ADVANCED_FACE('F2799',(#3859),#3848,.F.);
#3861=CARTESIAN_POINT('',(0.,34.5,0.));
#3862=DIRECTION('',(0.,1.,0.));
#3863=DIRECTION('',(0.,0.,1.));
#3864=AXIS2_PLACEMENT_3D('',#3861,#3862,#3863);
#3865=PLANE('',#3864);
#3866=CARTESIAN_POINT('',(229.,34.5,188.));
#3867=DIRECTION('',(0.,1.,0.));
#3868=DIRECTION('',(0.,0.,1.));
#3869=AXIS2_PLACEMENT_3D('',#3866,#3867,#3868);
#3870=CIRCLE('',#3869,3.99999999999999);
#3871=CARTESIAN_POINT('',(229.,34.5,192.));
#3872=VERTEX_POINT('',#3871);
#3873=EDGE_CURVE('E1650',#3872,#3872,#3870,.T.);
#3874=ORIENTED_EDGE('',*,*,#3873,.F.);
#3875=EDGE_LOOP('',(#3874));
#3876=FACE_BOUND('',#3875,.T.);
#3877=ORIENTED_EDGE('',*,*,#3737,.T.);
#3878=ORIENTED_EDGE('',*,*,#3855,.T.);
#3879=ORIENTED_EDGE('',*,*,#3833,.T.);
#3880=ORIENTED_EDGE('',*,*,#3809,.T.);
#3881=ORIENTED_EDGE('',*,*,#3785,.T.);
#3882=ORIENTED_EDGE('',*,*,#3761,.T.);
#3883=EDGE_LOOP('',(#3877,#3878,#3879,#3880,#3881,#3882));
#3884=FACE_BOUND('',#3883,.T.);
#3885=ADVANCED_FACE('F2809',(#3876,#3884),#3865,.T.);
#3886=CARTESIAN_POINT('',(309.,34.5,148.041451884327));
#3887=DIRECTION('',(1.,0.,0.));
#3888=DIRECTION('',(0.,0.,-1.));
#3889=AXIS2_PLACEMENT_3D('',#3886,#3887,#3888);
#3890=PLANE('',#3889);
#3891=ORIENTED_EDGE('',*,*,#611,.T.);
#3892=DIRECTION('',(0.,1.,0.));
#3893=VECTOR('',#3892,1.);
#3894=CARTESIAN_POINT('',(309.,34.5,139.958548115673));
#3895=LINE('',#3894,#3893);
#3896=CARTESIAN_POINT('',(309.,34.5,139.958548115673));
#3897=VERTEX_POINT('',#3896);
#3898=EDGE_CURVE('E806',#3897,#610,#3895,.T.);
#3899=ORIENTED_EDGE('',*,*,#3898,.F.);
#3900=DIRECTION('',(0.,0.,-1.));
#3901=VECTOR('',#3900,1.);
#3902=CARTESIAN_POINT('',(309.,34.5,148.041451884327));
#3903=LINE('',#3902,#3901);
#3904=CARTESIAN_POINT('',(309.,34.5,148.041451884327));
#3905=VERTEX_POINT('',#3904);
#3906=EDGE_CURVE('E787',#3905,#3897,#3903,.T.);
#3907=ORIENTED_EDGE('',*,*,#3906,.F.);
#3908=DIRECTION('',(0.,1.,0.));
#3909=VECTOR('',#3908,1.);
#3910=CARTESIAN_POINT('',(309.,34.5,148.041451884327));
#3911=LINE('',#3910,#3909);
#3912=EDGE_CURVE('E822',#3905,#608,#3911,.T.);
#3913=ORIENTED_EDGE('',*,*,#3912,.T.);
#3914=EDGE_LOOP('',(#3891,#3899,#3907,#3913));
#3915=FACE_BOUND('',#3914,.T.);
#3916=ADVANCED_FACE('F2817',(#3915),#3890,.F.);
#3917=CARTESIAN_POINT('',(302.,34.5,152.082903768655));
#3918=DIRECTION('',(0.499999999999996,0.,0.866025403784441));
#3919=DIRECTION('',(0.866025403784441,0.,-0.499999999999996));
#3920=AXIS2_PLACEMENT_3D('',#3917,#3918,#3919);
#3921=PLANE('',#3920);
#3922=ORIENTED_EDGE('',*,*,#619,.T.);
#3923=ORIENTED_EDGE('',*,*,#3912,.F.);
#3924=DIRECTION('',(0.866025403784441,0.,-0.499999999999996));
#3925=VECTOR('',#3924,1.);
#3926=CARTESIAN_POINT('',(302.,34.5,152.082903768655));
#3927=LINE('',#3926,#3925);
#3928=CARTESIAN_POINT('',(302.,34.5,152.082903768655));
#3929=VERTEX_POINT('',#3928);
#3930=EDGE_CURVE('E803',#3929,#3905,#3927,.T.);
#3931=ORIENTED_EDGE('',*,*,#3930,.F.);
#3932=DIRECTION('',(0.,1.,0.));
#3933=VECTOR('',#3932,1.);
#3934=CARTESIAN_POINT('',(302.,34.5,152.082903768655));
#3935=LINE('',#3934,#3933);
#3936=EDGE_CURVE('E825',#3929,#618,#3935,.T.);
#3937=ORIENTED_EDGE('',*,*,#3936,.T.);
#3938=EDGE_LOOP('',(#3922,#3923,#3931,#3937));
#3939=FACE_BOUND('',#3938,.T.);
#3940=ADVANCED_FACE('F2822',(#3939),#3921,.F.);
#3941=CARTESIAN_POINT('',(295.,34.5,148.041451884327));
#3942=DIRECTION('',(-0.500000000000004,0.,0.866025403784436));
#3943=DIRECTION('',(0.866025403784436,0.,0.500000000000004));
#3944=AXIS2_PLACEMENT_3D('',#3941,#3942,#3943);
#3945=PLANE('',#3944);
#3946=ORIENTED_EDGE('',*,*,#627,.T.);
#3947=ORIENTED_EDGE('',*,*,#3936,.F.);
#3948=DIRECTION('',(0.866025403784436,0.,0.500000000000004));
#3949=VECTOR('',#3948,1.);
#3950=CARTESIAN_POINT('',(295.,34.5,148.041451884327));
#3951=LINE('',#3950,#3949);
#3952=CARTESIAN_POINT('',(295.,34.5,148.041451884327));
#3953=VERTEX_POINT('',#3952);
#3954=EDGE_CURVE('E800',#3953,#3929,#3951,.T.);
#3955=ORIENTED_EDGE('',*,*,#3954,.F.);
#3956=DIRECTION('',(0.,1.,0.));
#3957=VECTOR('',#3956,1.);
#3958=CARTESIAN_POINT('',(295.,34.5,148.041451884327));
#3959=LINE('',#3958,#3957);
#3960=EDGE_CURVE('E827',#3953,#626,#3959,.T.);
#3961=ORIENTED_EDGE('',*,*,#3960,.T.);
#3962=EDGE_LOOP('',(#3946,#3947,#3955,#3961));
#3963=FACE_BOUND('',#3962,.T.);
#3964=ADVANCED_FACE('F2831',(#3963),#3945,.F.);
#3965=CARTESIAN_POINT('',(295.,34.5,139.958548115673));
#3966=DIRECTION('',(-1.,0.,0.));
#3967=DIRECTION('',(0.,0.,1.));
#3968=AXIS2_PLACEMENT_3D('',#3965,#3966,#3967);
#3969=PLANE('',#3968);
#3970=ORIENTED_EDGE('',*,*,#635,.T.);
#3971=ORIENTED_EDGE('',*,*,#3960,.F.);
#3972=DIRECTION('',(0.,0.,1.));
#3973=VECTOR('',#3972,1.);
#3974=CARTESIAN_POINT('',(295.,34.5,139.958548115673));
#3975=LINE('',#3974,#3973);
#3976=CARTESIAN_POINT('',(295.,34.5,139.958548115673));
#3977=VERTEX_POINT('',#3976);
#3978=EDGE_CURVE('E797',#3977,#3953,#3975,.T.);
#3979=ORIENTED_EDGE('',*,*,#3978,.F.);
#3980=DIRECTION('',(0.,1.,0.));
#3981=VECTOR('',#3980,1.);
#3982=CARTESIAN_POINT('',(295.,34.5,139.958548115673));
#3983=LINE('',#3982,#3981);
#3984=EDGE_CURVE('E829',#3977,#634,#3983,.T.);
#3985=ORIENTED_EDGE('',*,*,#3984,.T.);
#3986=EDGE_LOOP('',(#3970,#3971,#3979,#3985));
#3987=FACE_BOUND('',#3986,.T.);
#3988=ADVANCED_FACE('F2841',(#3987),#3969,.F.);
#3989=CARTESIAN_POINT('',(302.,34.5,135.917096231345));
#3990=DIRECTION('',(-0.499999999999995,0.,-0.866025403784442));
#3991=DIRECTION('',(-0.866025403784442,0.,0.499999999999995));
#3992=AXIS2_PLACEMENT_3D('',#3989,#3990,#3991);
#3993=PLANE('',#3992);
#3994=ORIENTED_EDGE('',*,*,#643,.T.);
#3995=ORIENTED_EDGE('',*,*,#3984,.F.);
#3996=DIRECTION('',(-0.866025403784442,0.,0.499999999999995));
#3997=VECTOR('',#3996,1.);
#3998=CARTESIAN_POINT('',(302.,34.5,135.917096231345));
#3999=LINE('',#3998,#3997);
#4000=CARTESIAN_POINT('',(302.,34.5,135.917096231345));
#4001=VERTEX_POINT('',#4000);
#4002=EDGE_CURVE('E794',#4001,#3977,#3999,.T.);
#4003=ORIENTED_EDGE('',*,*,#4002,.F.);
#4004=DIRECTION('',(0.,1.,0.));
#4005=VECTOR('',#4004,1.);
#4006=CARTESIAN_POINT('',(302.,34.5,135.917096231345));
#4007=LINE('',#4006,#4005);
#4008=EDGE_CURVE('E831',#4001,#642,#4007,.T.);
#4009=ORIENTED_EDGE('',*,*,#4008,.T.);
#4010=EDGE_LOOP('',(#3994,#3995,#4003,#4009));
#4011=FACE_BOUND('',#4010,.T.);
#4012=ADVANCED_FACE('F2851',(#4011),#3993,.F.);
#4013=CARTESIAN_POINT('',(309.,34.5,139.958548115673));
#4014=DIRECTION('',(0.500000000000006,0.,-0.866025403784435));
#4015=DIRECTION('',(-0.866025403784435,0.,-0.500000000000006));
#4016=AXIS2_PLACEMENT_3D('',#4013,#4014,#4015);
#4017=PLANE('',#4016);
#4018=ORIENTED_EDGE('',*,*,#649,.T.);
#4019=ORIENTED_EDGE('',*,*,#4008,.F.);
#4020=DIRECTION('',(-0.866025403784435,0.,-0.500000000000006));
#4021=VECTOR('',#4020,1.);
#4022=CARTESIAN_POINT('',(309.,34.5,139.958548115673));
#4023=LINE('',#4022,#4021);
#4024=EDGE_CURVE('E790',#3897,#4001,#4023,.T.);
#4025=ORIENTED_EDGE('',*,*,#4024,.F.);
#4026=ORIENTED_EDGE('',*,*,#3898,.T.);
#4027=EDGE_LOOP('',(#4018,#4019,#4025,#4026));
#4028=FACE_BOUND('',#4027,.T.);
#4029=ADVANCED_FACE('F2861',(#4028),#4017,.F.);
#4030=CARTESIAN_POINT('',(0.,34.5,0.));
#4031=DIRECTION('',(0.,1.,0.));
#4032=DIRECTION('',(0.,0.,1.));
#4033=AXIS2_PLACEMENT_3D('',#4030,#4031,#4032);
#4034=PLANE('',#4033);
#4035=CARTESIAN_POINT('',(302.,34.5,144.));
#4036=DIRECTION('',(0.,1.,0.));
#4037=DIRECTION('',(0.,0.,1.));
#4038=AXIS2_PLACEMENT_3D('',#4035,#4036,#4037);
#4039=CIRCLE('',#4038,3.99999999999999);
#4040=CARTESIAN_POINT('',(302.,34.5,148.));
#4041=VERTEX_POINT('',#4040);
#4042=EDGE_CURVE('E1658',#4041,#4041,#4039,.T.);
#4043=ORIENTED_EDGE('',*,*,#4042,.F.);
#4044=EDGE_LOOP('',(#4043));
#4045=FACE_BOUND('',#4044,.T.);
#4046=ORIENTED_EDGE('',*,*,#3906,.T.);
#4047=ORIENTED_EDGE('',*,*,#4024,.T.);
#4048=ORIENTED_EDGE('',*,*,#4002,.T.);
#4049=ORIENTED_EDGE('',*,*,#3978,.T.);
#4050=ORIENTED_EDGE('',*,*,#3954,.T.);
#4051=ORIENTED_EDGE('',*,*,#3930,.T.);
#4052=EDGE_LOOP('',(#4046,#4047,#4048,#4049,#4050,#4051));
#4053=FACE_BOUND('',#4052,.T.);
#4054=ADVANCED_FACE('F2871',(#4045,#4053),#4034,.T.);
#4055=CARTESIAN_POINT('',(309.,34.5,192.041451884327));
#4056=DIRECTION('',(1.,0.,0.));
#4057=DIRECTION('',(0.,0.,-1.));
#4058=AXIS2_PLACEMENT_3D('',#4055,#4056,#4057);
#4059=PLANE('',#4058);
#4060=ORIENTED_EDGE('',*,*,#561,.T.);
#4061=DIRECTION('',(0.,1.,0.));
#4062=VECTOR('',#4061,1.);
#4063=CARTESIAN_POINT('',(309.,34.5,183.958548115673));
#4064=LINE('',#4063,#4062);
#4065=CARTESIAN_POINT('',(309.,34.5,183.958548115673));
#4066=VERTEX_POINT('',#4065);
#4067=EDGE_CURVE('E727',#4066,#560,#4064,.T.);
#4068=ORIENTED_EDGE('',*,*,#4067,.F.);
#4069=DIRECTION('',(0.,0.,-1.));
#4070=VECTOR('',#4069,1.);
#4071=CARTESIAN_POINT('',(309.,34.5,192.041451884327));
#4072=LINE('',#4071,#4070);
#4073=CARTESIAN_POINT('',(309.,34.5,192.041451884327));
#4074=VERTEX_POINT('',#4073);
#4075=EDGE_CURVE('E731',#4074,#4066,#4072,.T.);
#4076=ORIENTED_EDGE('',*,*,#4075,.F.);
#4077=DIRECTION('',(0.,1.,0.));
#4078=VECTOR('',#4077,1.);
#4079=CARTESIAN_POINT('',(309.,34.5,192.041451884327));
#4080=LINE('',#4079,#4078);
#4081=EDGE_CURVE('E778',#4074,#558,#4080,.T.);
#4082=ORIENTED_EDGE('',*,*,#4081,.T.);
#4083=EDGE_LOOP('',(#4060,#4068,#4076,#4082));
#4084=FACE_BOUND('',#4083,.T.);
#4085=ADVANCED_FACE('F729',(#4084),#4059,.F.);
#4086=CARTESIAN_POINT('',(302.,34.5,196.082903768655));
#4087=DIRECTION('',(0.499999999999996,0.,0.866025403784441));
#4088=DIRECTION('',(0.866025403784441,0.,-0.499999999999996));
#4089=AXIS2_PLACEMENT_3D('',#4086,#4087,#4088);
#4090=PLANE('',#4089);
#4091=ORIENTED_EDGE('',*,*,#569,.T.);
#4092=ORIENTED_EDGE('',*,*,#4081,.F.);
#4093=DIRECTION('',(0.866025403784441,0.,-0.499999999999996));
#4094=VECTOR('',#4093,1.);
#4095=CARTESIAN_POINT('',(302.,34.5,196.082903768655));
#4096=LINE('',#4095,#4094);
#4097=CARTESIAN_POINT('',(302.,34.5,196.082903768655));
#4098=VERTEX_POINT('',#4097);
#4099=EDGE_CURVE('E737',#4098,#4074,#4096,.T.);
#4100=ORIENTED_EDGE('',*,*,#4099,.F.);
#4101=DIRECTION('',(0.,1.,0.));
#4102=VECTOR('',#4101,1.);
#4103=CARTESIAN_POINT('',(302.,34.5,196.082903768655));
#4104=LINE('',#4103,#4102);
#4105=EDGE_CURVE('E780',#4098,#568,#4104,.T.);
#4106=ORIENTED_EDGE('',*,*,#4105,.T.);
#4107=EDGE_LOOP('',(#4091,#4092,#4100,#4106));
#4108=FACE_BOUND('',#4107,.T.);
#4109=ADVANCED_FACE('F2883',(#4108),#4090,.F.);
#4110=CARTESIAN_POINT('',(295.,34.5,192.041451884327));
#4111=DIRECTION('',(-0.500000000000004,0.,0.866025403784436));
#4112=DIRECTION('',(0.866025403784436,0.,0.500000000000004));
#4113=AXIS2_PLACEMENT_3D('',#4110,#4111,#4112);
#4114=PLANE('',#4113);
#4115=ORIENTED_EDGE('',*,*,#577,.T.);
#4116=ORIENTED_EDGE('',*,*,#4105,.F.);
#4117=DIRECTION('',(0.866025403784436,0.,0.500000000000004));
#4118=VECTOR('',#4117,1.);
#4119=CARTESIAN_POINT('',(295.,34.5,192.041451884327));
#4120=LINE('',#4119,#4118);
#4121=CARTESIAN_POINT('',(295.,34.5,192.041451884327));
#4122=VERTEX_POINT('',#4121);
#4123=EDGE_CURVE('E763',#4122,#4098,#4120,.T.);
#4124=ORIENTED_EDGE('',*,*,#4123,.F.);
#4125=DIRECTION('',(0.,1.,0.));
#4126=VECTOR('',#4125,1.);
#4127=CARTESIAN_POINT('',(295.,34.5,192.041451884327));
#4128=LINE('',#4127,#4126);
#4129=EDGE_CURVE('E782',#4122,#576,#4128,.T.);
#4130=ORIENTED_EDGE('',*,*,#4129,.T.);
#4131=EDGE_LOOP('',(#4115,#4116,#4124,#4130));
#4132=FACE_BOUND('',#4131,.T.);
#4133=ADVANCED_FACE('F2892',(#4132),#4114,.F.);
#4134=CARTESIAN_POINT('',(295.,34.5,183.958548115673));
#4135=DIRECTION('',(-1.,0.,0.));
#4136=DIRECTION('',(0.,0.,1.));
#4137=AXIS2_PLACEMENT_3D('',#4134,#4135,#4136);
#4138=PLANE('',#4137);
#4139=ORIENTED_EDGE('',*,*,#585,.T.);
#4140=ORIENTED_EDGE('',*,*,#4129,.F.);
#4141=DIRECTION('',(0.,0.,1.));
#4142=VECTOR('',#4141,1.);
#4143=CARTESIAN_POINT('',(295.,34.5,183.958548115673));
#4144=LINE('',#4143,#4142);
#4145=CARTESIAN_POINT('',(295.,34.5,183.958548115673));
#4146=VERTEX_POINT('',#4145);
#4147=EDGE_CURVE('E760',#4146,#4122,#4144,.T.);
#4148=ORIENTED_EDGE('',*,*,#4147,.F.);
#4149=DIRECTION('',(0.,1.,0.));
#4150=VECTOR('',#4149,1.);
#4151=CARTESIAN_POINT('',(295.,34.5,183.958548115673));
#4152=LINE('',#4151,#4150);
#4153=EDGE_CURVE('E784',#4146,#584,#4152,.T.);
#4154=ORIENTED_EDGE('',*,*,#4153,.T.);
#4155=EDGE_LOOP('',(#4139,#4140,#4148,#4154));
#4156=FACE_BOUND('',#4155,.T.);
#4157=ADVANCED_FACE('F2902',(#4156),#4138,.F.);
#4158=CARTESIAN_POINT('',(302.,34.5,179.917096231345));
#4159=DIRECTION('',(-0.499999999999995,0.,-0.866025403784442));
#4160=DIRECTION('',(-0.866025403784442,0.,0.499999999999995));
#4161=AXIS2_PLACEMENT_3D('',#4158,#4159,#4160);
#4162=PLANE('',#4161);
#4163=ORIENTED_EDGE('',*,*,#593,.T.);
#4164=ORIENTED_EDGE('',*,*,#4153,.F.);
#4165=DIRECTION('',(-0.866025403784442,0.,0.499999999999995));
#4166=VECTOR('',#4165,1.);
#4167=CARTESIAN_POINT('',(302.,34.5,179.917096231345));
#4168=LINE('',#4167,#4166);
#4169=CARTESIAN_POINT('',(302.,34.5,179.917096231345));
#4170=VERTEX_POINT('',#4169);
#4171=EDGE_CURVE('E745',#4170,#4146,#4168,.T.);
#4172=ORIENTED_EDGE('',*,*,#4171,.F.);
#4173=DIRECTION('',(0.,1.,0.));
#4174=VECTOR('',#4173,1.);
#4175=CARTESIAN_POINT('',(302.,34.5,179.917096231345));
#4176=LINE('',#4175,#4174);
#4177=EDGE_CURVE('E736',#4170,#592,#4176,.T.);
#4178=ORIENTED_EDGE('',*,*,#4177,.T.);
#4179=EDGE_LOOP('',(#4163,#4164,#4172,#4178));
#4180=FACE_BOUND('',#4179,.T.);
#4181=ADVANCED_FACE('F2912',(#4180),#4162,.F.);
#4182=CARTESIAN_POINT('',(309.,34.5,183.958548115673));
#4183=DIRECTION('',(0.500000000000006,0.,-0.866025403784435));
#4184=DIRECTION('',(-0.866025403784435,0.,-0.500000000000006));
#4185=AXIS2_PLACEMENT_3D('',#4182,#4183,#4184);
#4186=PLANE('',#4185);
#4187=ORIENTED_EDGE('',*,*,#599,.T.);
#4188=ORIENTED_EDGE('',*,*,#4177,.F.);
#4189=DIRECTION('',(-0.866025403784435,0.,-0.500000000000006));
#4190=VECTOR('',#4189,1.);
#4191=CARTESIAN_POINT('',(309.,34.5,183.958548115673));
#4192=LINE('',#4191,#4190);
#4193=EDGE_CURVE('E740',#4066,#4170,#4192,.T.);
#4194=ORIENTED_EDGE('',*,*,#4193,.F.);
#4195=ORIENTED_EDGE('',*,*,#4067,.T.);
#4196=EDGE_LOOP('',(#4187,#4188,#4194,#4195));
#4197=FACE_BOUND('',#4196,.T.);
#4198=ADVANCED_FACE('F741',(#4197),#4186,.F.);
#4199=CARTESIAN_POINT('',(0.,34.5,0.));
#4200=DIRECTION('',(0.,1.,0.));
#4201=DIRECTION('',(0.,0.,1.));
#4202=AXIS2_PLACEMENT_3D('',#4199,#4200,#4201);
#4203=PLANE('',#4202);
#4204=CARTESIAN_POINT('',(302.,34.5,188.));
#4205=DIRECTION('',(0.,1.,0.));
#4206=DIRECTION('',(0.,0.,1.));
#4207=AXIS2_PLACEMENT_3D('',#4204,#4205,#4206);
#4208=CIRCLE('',#4207,3.99999999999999);
#4209=CARTESIAN_POINT('',(302.,34.5,192.));
#4210=VERTEX_POINT('',#4209);
#4211=EDGE_CURVE('E1654',#4210,#4210,#4208,.T.);
#4212=ORIENTED_EDGE('',*,*,#4211,.F.);
#4213=EDGE_LOOP('',(#4212));
#4214=FACE_BOUND('',#4213,.T.);
#4215=ORIENTED_EDGE('',*,*,#4075,.T.);
#4216=ORIENTED_EDGE('',*,*,#4193,.T.);
#4217=ORIENTED_EDGE('',*,*,#4171,.T.);
#4218=ORIENTED_EDGE('',*,*,#4147,.T.);
#4219=ORIENTED_EDGE('',*,*,#4123,.T.);
#4220=ORIENTED_EDGE('',*,*,#4099,.T.);
#4221=EDGE_LOOP('',(#4215,#4216,#4217,#4218,#4219,#4220));
#4222=FACE_BOUND('',#4221,.T.);
#4223=ADVANCED_FACE('F747',(#4214,#4222),#4203,.T.);
#4224=CARTESIAN_POINT('',(-300.,0.,-188.));
#4225=DIRECTION('',(0.,1.,0.));
#4226=DIRECTION('',(0.,0.,1.));
#4227=AXIS2_PLACEMENT_3D('',#4224,#4225,#4226);
#4228=CYLINDRICAL_SURFACE('',#4227,3.99999999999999);
#4229=ORIENTED_EDGE('',*,*,#2521,.T.);
#4230=EDGE_LOOP('',(#4229));
#4231=FACE_BOUND('',#4230,.T.);
#4232=ORIENTED_EDGE('',*,*,#533,.F.);
#4233=EDGE_LOOP('',(#4232));
#4234=FACE_BOUND('',#4233,.T.);
#4235=ADVANCED_FACE('F1714',(#4231,#4234),#4228,.F.);
#4236=CARTESIAN_POINT('',(-300.,0.,-144.));
#4237=DIRECTION('',(0.,1.,0.));
#4238=DIRECTION('',(0.,0.,1.));
#4239=AXIS2_PLACEMENT_3D('',#4236,#4237,#4238);
#4240=CYLINDRICAL_SURFACE('',#4239,3.99999999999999);
#4241=ORIENTED_EDGE('',*,*,#2690,.T.);
#4242=EDGE_LOOP('',(#4241));
#4243=FACE_BOUND('',#4242,.T.);
#4244=ORIENTED_EDGE('',*,*,#522,.F.);
#4245=EDGE_LOOP('',(#4244));
#4246=FACE_BOUND('',#4245,.T.);
#4247=ADVANCED_FACE('F1711',(#4243,#4246),#4240,.F.);
#4248=CARTESIAN_POINT('',(-227.,0.,-144.));
#4249=DIRECTION('',(0.,1.,0.));
#4250=DIRECTION('',(0.,0.,1.));
#4251=AXIS2_PLACEMENT_3D('',#4248,#4249,#4250);
#4252=CYLINDRICAL_SURFACE('',#4251,3.99999999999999);
#4253=ORIENTED_EDGE('',*,*,#2859,.T.);
#4254=EDGE_LOOP('',(#4253));
#4255=FACE_BOUND('',#4254,.T.);
#4256=ORIENTED_EDGE('',*,*,#511,.F.);
#4257=EDGE_LOOP('',(#4256));
#4258=FACE_BOUND('',#4257,.T.);
#4259=ADVANCED_FACE('F1713',(#4255,#4258),#4252,.F.);
#4260=CARTESIAN_POINT('',(-227.,0.,-188.));
#4261=DIRECTION('',(0.,1.,0.));
#4262=DIRECTION('',(0.,0.,1.));
#4263=AXIS2_PLACEMENT_3D('',#4260,#4261,#4262);
#4264=CYLINDRICAL_SURFACE('',#4263,3.99999999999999);
#4265=ORIENTED_EDGE('',*,*,#2352,.T.);
#4266=EDGE_LOOP('',(#4265));
#4267=FACE_BOUND('',#4266,.T.);
#4268=ORIENTED_EDGE('',*,*,#500,.F.);
#4269=EDGE_LOOP('',(#4268));
#4270=FACE_BOUND('',#4269,.T.);
#4271=ADVANCED_FACE('F1721',(#4267,#4270),#4264,.F.);
#4272=CARTESIAN_POINT('',(-300.,0.,144.));
#4273=DIRECTION('',(0.,1.,0.));
#4274=DIRECTION('',(0.,0.,1.));
#4275=AXIS2_PLACEMENT_3D('',#4272,#4273,#4274);
#4276=CYLINDRICAL_SURFACE('',#4275,3.99999999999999);
#4277=ORIENTED_EDGE('',*,*,#3028,.T.);
#4278=EDGE_LOOP('',(#4277));
#4279=FACE_BOUND('',#4278,.T.);
#4280=ORIENTED_EDGE('',*,*,#489,.F.);
#4281=EDGE_LOOP('',(#4280));
#4282=FACE_BOUND('',#4281,.T.);
#4283=ADVANCED_FACE('F3074',(#4279,#4282),#4276,.F.);
#4284=CARTESIAN_POINT('',(-300.,0.,188.));
#4285=DIRECTION('',(0.,1.,0.));
#4286=DIRECTION('',(0.,0.,1.));
#4287=AXIS2_PLACEMENT_3D('',#4284,#4285,#4286);
#4288=CYLINDRICAL_SURFACE('',#4287,3.99999999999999);
#4289=ORIENTED_EDGE('',*,*,#3366,.T.);
#4290=EDGE_LOOP('',(#4289));
#4291=FACE_BOUND('',#4290,.T.);
#4292=ORIENTED_EDGE('',*,*,#478,.F.);
#4293=EDGE_LOOP('',(#4292));
#4294=FACE_BOUND('',#4293,.T.);
#4295=ADVANCED_FACE('F3084',(#4291,#4294),#4288,.F.);
#4296=CARTESIAN_POINT('',(-227.,0.,188.));
#4297=DIRECTION('',(0.,1.,0.));
#4298=DIRECTION('',(0.,0.,1.));
#4299=AXIS2_PLACEMENT_3D('',#4296,#4297,#4298);
#4300=CYLINDRICAL_SURFACE('',#4299,3.99999999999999);
#4301=ORIENTED_EDGE('',*,*,#3535,.T.);
#4302=EDGE_LOOP('',(#4301));
#4303=FACE_BOUND('',#4302,.T.);
#4304=ORIENTED_EDGE('',*,*,#467,.F.);
#4305=EDGE_LOOP('',(#4304));
#4306=FACE_BOUND('',#4305,.T.);
#4307=ADVANCED_FACE('F3094',(#4303,#4306),#4300,.F.);
#4308=CARTESIAN_POINT('',(-227.,0.,144.));
#4309=DIRECTION('',(0.,1.,0.));
#4310=DIRECTION('',(0.,0.,1.));
#4311=AXIS2_PLACEMENT_3D('',#4308,#4309,#4310);
#4312=CYLINDRICAL_SURFACE('',#4311,3.99999999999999);
#4313=ORIENTED_EDGE('',*,*,#3197,.T.);
#4314=EDGE_LOOP('',(#4313));
#4315=FACE_BOUND('',#4314,.T.);
#4316=ORIENTED_EDGE('',*,*,#456,.F.);
#4317=EDGE_LOOP('',(#4316));
#4318=FACE_BOUND('',#4317,.T.);
#4319=ADVANCED_FACE('F3104',(#4315,#4318),#4312,.F.);
#4320=CARTESIAN_POINT('',(229.,0.,144.));
#4321=DIRECTION('',(0.,1.,0.));
#4322=DIRECTION('',(0.,0.,1.));
#4323=AXIS2_PLACEMENT_3D('',#4320,#4321,#4322);
#4324=CYLINDRICAL_SURFACE('',#4323,3.99999999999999);
#4325=ORIENTED_EDGE('',*,*,#3704,.T.);
#4326=EDGE_LOOP('',(#4325));
#4327=FACE_BOUND('',#4326,.T.);
#4328=ORIENTED_EDGE('',*,*,#445,.F.);
#4329=EDGE_LOOP('',(#4328));
#4330=FACE_BOUND('',#4329,.T.);
#4331=ADVANCED_FACE('F3114',(#4327,#4330),#4324,.F.);
#4332=CARTESIAN_POINT('',(229.,0.,188.));
#4333=DIRECTION('',(0.,1.,0.));
#4334=DIRECTION('',(0.,0.,1.));
#4335=AXIS2_PLACEMENT_3D('',#4332,#4333,#4334);
#4336=CYLINDRICAL_SURFACE('',#4335,3.99999999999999);
#4337=ORIENTED_EDGE('',*,*,#3873,.T.);
#4338=EDGE_LOOP('',(#4337));
#4339=FACE_BOUND('',#4338,.T.);
#4340=ORIENTED_EDGE('',*,*,#434,.F.);
#4341=EDGE_LOOP('',(#4340));
#4342=FACE_BOUND('',#4341,.T.);
#4343=ADVANCED_FACE('F3124',(#4339,#4342),#4336,.F.);
#4344=CARTESIAN_POINT('',(302.,0.,188.));
#4345=DIRECTION('',(0.,1.,0.));
#4346=DIRECTION('',(0.,0.,1.));
#4347=AXIS2_PLACEMENT_3D('',#4344,#4345,#4346);
#4348=CYLINDRICAL_SURFACE('',#4347,3.99999999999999);
#4349=ORIENTED_EDGE('',*,*,#4211,.T.);
#4350=EDGE_LOOP('',(#4349));
#4351=FACE_BOUND('',#4350,.T.);
#4352=ORIENTED_EDGE('',*,*,#423,.F.);
#4353=EDGE_LOOP('',(#4352));
#4354=FACE_BOUND('',#4353,.T.);
#4355=ADVANCED_FACE('F3134',(#4351,#4354),#4348,.F.);
#4356=CARTESIAN_POINT('',(302.,0.,144.));
#4357=DIRECTION('',(0.,1.,0.));
#4358=DIRECTION('',(0.,0.,1.));
#4359=AXIS2_PLACEMENT_3D('',#4356,#4357,#4358);
#4360=CYLINDRICAL_SURFACE('',#4359,3.99999999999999);
#4361=ORIENTED_EDGE('',*,*,#4042,.T.);
#4362=EDGE_LOOP('',(#4361));
#4363=FACE_BOUND('',#4362,.T.);
#4364=ORIENTED_EDGE('',*,*,#412,.F.);
#4365=EDGE_LOOP('',(#4364));
#4366=FACE_BOUND('',#4365,.T.);
#4367=ADVANCED_FACE('F3144',(#4363,#4366),#4360,.F.);
#4368=CARTESIAN_POINT('',(229.,0.,-188.));
#4369=DIRECTION('',(0.,1.,0.));
#4370=DIRECTION('',(0.,0.,1.));
#4371=AXIS2_PLACEMENT_3D('',#4368,#4369,#4370);
#4372=CYLINDRICAL_SURFACE('',#4371,3.99999999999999);
#4373=ORIENTED_EDGE('',*,*,#2183,.T.);
#4374=EDGE_LOOP('',(#4373));
#4375=FACE_BOUND('',#4374,.T.);
#4376=ORIENTED_EDGE('',*,*,#401,.F.);
#4377=EDGE_LOOP('',(#4376));
#4378=FACE_BOUND('',#4377,.T.);
#4379=ADVANCED_FACE('F3154',(#4375,#4378),#4372,.F.);
#4380=CARTESIAN_POINT('',(229.,0.,-144.));
#4381=DIRECTION('',(0.,1.,0.));
#4382=DIRECTION('',(0.,0.,1.));
#4383=AXIS2_PLACEMENT_3D('',#4380,#4381,#4382);
#4384=CYLINDRICAL_SURFACE('',#4383,3.99999999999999);
#4385=ORIENTED_EDGE('',*,*,#2014,.T.);
#4386=EDGE_LOOP('',(#4385));
#4387=FACE_BOUND('',#4386,.T.);
#4388=ORIENTED_EDGE('',*,*,#390,.F.);
#4389=EDGE_LOOP('',(#4388));
#4390=FACE_BOUND('',#4389,.T.);
#4391=ADVANCED_FACE('F3164',(#4387,#4390),#4384,.F.);
#4392=CARTESIAN_POINT('',(302.,0.,-144.));
#4393=DIRECTION('',(0.,1.,0.));
#4394=DIRECTION('',(0.,0.,1.));
#4395=AXIS2_PLACEMENT_3D('',#4392,#4393,#4394);
#4396=CYLINDRICAL_SURFACE('',#4395,3.99999999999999);
#4397=ORIENTED_EDGE('',*,*,#1676,.T.);
#4398=EDGE_LOOP('',(#4397));
#4399=FACE_BOUND('',#4398,.T.);
#4400=ORIENTED_EDGE('',*,*,#379,.F.);
#4401=EDGE_LOOP('',(#4400));
#4402=FACE_BOUND('',#4401,.T.);
#4403=ADVANCED_FACE('F3174',(#4399,#4402),#4396,.F.);
#4404=CARTESIAN_POINT('',(302.,0.,-188.));
#4405=DIRECTION('',(0.,1.,0.));
#4406=DIRECTION('',(0.,0.,1.));
#4407=AXIS2_PLACEMENT_3D('',#4404,#4405,#4406);
#4408=CYLINDRICAL_SURFACE('',#4407,3.99999999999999);
#4409=ORIENTED_EDGE('',*,*,#1845,.T.);
#4410=EDGE_LOOP('',(#4409));
#4411=FACE_BOUND('',#4410,.T.);
#4412=ORIENTED_EDGE('',*,*,#368,.F.);
#4413=EDGE_LOOP('',(#4412));
#4414=FACE_BOUND('',#4413,.T.);
#4415=ADVANCED_FACE('F3184',(#4411,#4414),#4408,.F.);
#4416=CLOSED_SHELL('',(#58,#100,#139,#163,#196,#235,#268,#290,#355,#547,#1410,#1432,#1454,#1471,
#1488,#1500,#1512,#1519,#1550,#1574,#1598,#1622,#1646,#1663,#1688,#1719,#1743,#1767,#1791,#1815,
#1832,#1857,#1888,#1912,#1936,#1960,#1984,#2001,#2026,#2057,#2081,#2105,#2129,#2153,#2170,#2195,
#2226,#2250,#2274,#2298,#2322,#2339,#2364,#2395,#2419,#2443,#2467,#2491,#2508,#2533,#2564,#2588,
#2612,#2636,#2660,#2677,#2702,#2733,#2757,#2781,#2805,#2829,#2846,#2871,#2902,#2926,#2950,#2974,
#2998,#3015,#3040,#3071,#3095,#3119,#3143,#3167,#3184,#3209,#3240,#3264,#3288,#3312,#3336,#3353,
#3378,#3409,#3433,#3457,#3481,#3505,#3522,#3547,#3578,#3602,#3626,#3650,#3674,#3691,#3716,#3747,
#3771,#3795,#3819,#3843,#3860,#3885,#3916,#3940,#3964,#3988,#4012,#4029,#4054,#4085,#4109,#4133,
#4157,#4181,#4198,#4223,#4235,#4247,#4259,#4271,#4283,#4295,#4307,#4319,#4331,#4343,#4355,#4367,
#4379,#4391,#4403,#4415));
#4417=MANIFOLD_SOLID_BREP('B2',#4416);
#4418=ADVANCED_BREP_SHAPE_REPRESENTATION('',(#18,#4417),#14);
#4419=SHAPE_DEFINITION_REPRESENTATION(#9,#4418);
ENDSEC;
END-ISO-10303-21;
